VERSION 5.8 ;
BUSBITCHARS "[]" ;
DIVIDERCHAR "/" ;
UNITS
    DATABASE MICRONS 1000 ;
END UNITS

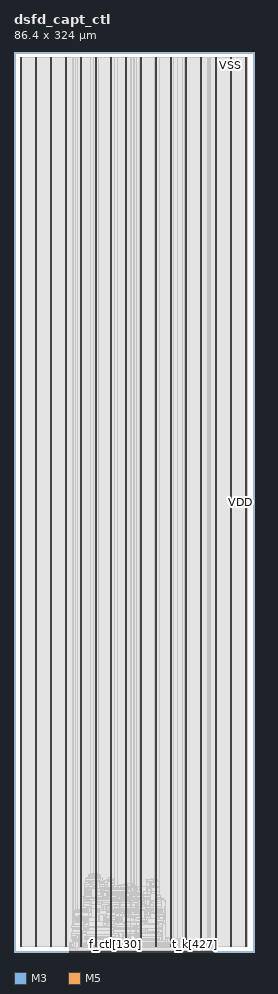
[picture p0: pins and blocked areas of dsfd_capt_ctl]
MACRO dsfd_capt_ctl
  FOREIGN dsfd_capt_ctl 0 0 ;
  CLASS BLOCK ;
  SIZE 86.4 BY 324 ;
  PIN ck[0]
    DIRECTION INPUT ;
    USE SIGNAL ;
    PORT
      LAYER M3 ;
        RECT  31.644 0 31.662 0.037 ;
    END
  END ck[0]
  PIN f_ctl[0]
    DIRECTION INPUT ;
    USE SIGNAL ;
    PORT
      LAYER M3 ;
        RECT  31.716 0 31.734 0.037 ;
    END
  END f_ctl[0]
  PIN f_ctl[100]
    DIRECTION INPUT ;
    USE SIGNAL ;
    PORT
      LAYER M5 ;
        RECT  48.816 0 48.84 0.084 ;
    END
  END f_ctl[100]
  PIN f_ctl[101]
    DIRECTION INPUT ;
    USE SIGNAL ;
    PORT
      LAYER M5 ;
        RECT  48.912 0 48.936 0.084 ;
    END
  END f_ctl[101]
  PIN f_ctl[102]
    DIRECTION INPUT ;
    USE SIGNAL ;
    PORT
      LAYER M5 ;
        RECT  49.008 0 49.032 0.084 ;
    END
  END f_ctl[102]
  PIN f_ctl[103]
    DIRECTION INPUT ;
    USE SIGNAL ;
    PORT
      LAYER M5 ;
        RECT  49.104 0 49.128 0.084 ;
    END
  END f_ctl[103]
  PIN f_ctl[104]
    DIRECTION INPUT ;
    USE SIGNAL ;
    PORT
      LAYER M5 ;
        RECT  49.2 0 49.224 0.084 ;
    END
  END f_ctl[104]
  PIN f_ctl[105]
    DIRECTION INPUT ;
    USE SIGNAL ;
    PORT
      LAYER M5 ;
        RECT  49.296 0 49.32 0.084 ;
    END
  END f_ctl[105]
  PIN f_ctl[106]
    DIRECTION INPUT ;
    USE SIGNAL ;
    PORT
      LAYER M5 ;
        RECT  49.392 0 49.416 0.084 ;
    END
  END f_ctl[106]
  PIN f_ctl[107]
    DIRECTION INPUT ;
    USE SIGNAL ;
    PORT
      LAYER M5 ;
        RECT  49.488 0 49.512 0.084 ;
    END
  END f_ctl[107]
  PIN f_ctl[108]
    DIRECTION INPUT ;
    USE SIGNAL ;
    PORT
      LAYER M5 ;
        RECT  49.584 0 49.608 0.084 ;
    END
  END f_ctl[108]
  PIN f_ctl[109]
    DIRECTION INPUT ;
    USE SIGNAL ;
    PORT
      LAYER M5 ;
        RECT  49.68 0 49.704 0.084 ;
    END
  END f_ctl[109]
  PIN f_ctl[10]
    DIRECTION INPUT ;
    USE SIGNAL ;
    PORT
      LAYER M3 ;
        RECT  32.436 0 32.454 0.037 ;
    END
  END f_ctl[10]
  PIN f_ctl[110]
    DIRECTION INPUT ;
    USE SIGNAL ;
    PORT
      LAYER M5 ;
        RECT  49.776 0 49.8 0.084 ;
    END
  END f_ctl[110]
  PIN f_ctl[111]
    DIRECTION INPUT ;
    USE SIGNAL ;
    PORT
      LAYER M5 ;
        RECT  49.872 0 49.896 0.084 ;
    END
  END f_ctl[111]
  PIN f_ctl[112]
    DIRECTION INPUT ;
    USE SIGNAL ;
    PORT
      LAYER M5 ;
        RECT  49.968 0 49.992 0.084 ;
    END
  END f_ctl[112]
  PIN f_ctl[113]
    DIRECTION INPUT ;
    USE SIGNAL ;
    PORT
      LAYER M5 ;
        RECT  50.064 0 50.088 0.084 ;
    END
  END f_ctl[113]
  PIN f_ctl[114]
    DIRECTION INPUT ;
    USE SIGNAL ;
    PORT
      LAYER M5 ;
        RECT  50.16 0 50.184 0.084 ;
    END
  END f_ctl[114]
  PIN f_ctl[115]
    DIRECTION INPUT ;
    USE SIGNAL ;
    PORT
      LAYER M5 ;
        RECT  50.256 0 50.28 0.084 ;
    END
  END f_ctl[115]
  PIN f_ctl[116]
    DIRECTION INPUT ;
    USE SIGNAL ;
    PORT
      LAYER M5 ;
        RECT  50.352 0 50.376 0.084 ;
    END
  END f_ctl[116]
  PIN f_ctl[117]
    DIRECTION INPUT ;
    USE SIGNAL ;
    PORT
      LAYER M5 ;
        RECT  50.448 0 50.472 0.084 ;
    END
  END f_ctl[117]
  PIN f_ctl[118]
    DIRECTION INPUT ;
    USE SIGNAL ;
    PORT
      LAYER M5 ;
        RECT  50.544 0 50.568 0.084 ;
    END
  END f_ctl[118]
  PIN f_ctl[119]
    DIRECTION INPUT ;
    USE SIGNAL ;
    PORT
      LAYER M5 ;
        RECT  50.64 0 50.664 0.084 ;
    END
  END f_ctl[119]
  PIN f_ctl[11]
    DIRECTION INPUT ;
    USE SIGNAL ;
    PORT
      LAYER M3 ;
        RECT  32.508 0 32.526 0.037 ;
    END
  END f_ctl[11]
  PIN f_ctl[120]
    DIRECTION INPUT ;
    USE SIGNAL ;
    PORT
      LAYER M5 ;
        RECT  50.736 0 50.76 0.084 ;
    END
  END f_ctl[120]
  PIN f_ctl[121]
    DIRECTION INPUT ;
    USE SIGNAL ;
    PORT
      LAYER M5 ;
        RECT  50.832 0 50.856 0.084 ;
    END
  END f_ctl[121]
  PIN f_ctl[122]
    DIRECTION INPUT ;
    USE SIGNAL ;
    PORT
      LAYER M5 ;
        RECT  50.928 0 50.952 0.084 ;
    END
  END f_ctl[122]
  PIN f_ctl[123]
    DIRECTION INPUT ;
    USE SIGNAL ;
    PORT
      LAYER M5 ;
        RECT  51.024 0 51.048 0.084 ;
    END
  END f_ctl[123]
  PIN f_ctl[124]
    DIRECTION INPUT ;
    USE SIGNAL ;
    PORT
      LAYER M5 ;
        RECT  51.12 0 51.144 0.084 ;
    END
  END f_ctl[124]
  PIN f_ctl[125]
    DIRECTION INPUT ;
    USE SIGNAL ;
    PORT
      LAYER M5 ;
        RECT  51.216 0 51.24 0.084 ;
    END
  END f_ctl[125]
  PIN f_ctl[126]
    DIRECTION INPUT ;
    USE SIGNAL ;
    PORT
      LAYER M5 ;
        RECT  51.312 0 51.336 0.084 ;
    END
  END f_ctl[126]
  PIN f_ctl[127]
    DIRECTION INPUT ;
    USE SIGNAL ;
    PORT
      LAYER M3 ;
        RECT  36.252 0 36.27 0.037 ;
    END
  END f_ctl[127]
  PIN f_ctl[128]
    DIRECTION INPUT ;
    USE SIGNAL ;
    PORT
      LAYER M3 ;
        RECT  36.324 0 36.342 0.037 ;
    END
  END f_ctl[128]
  PIN f_ctl[129]
    DIRECTION INPUT ;
    USE SIGNAL ;
    PORT
      LAYER M3 ;
        RECT  36.396 0 36.414 0.037 ;
    END
  END f_ctl[129]
  PIN f_ctl[12]
    DIRECTION INPUT ;
    USE SIGNAL ;
    PORT
      LAYER M3 ;
        RECT  32.58 0 32.598 0.037 ;
    END
  END f_ctl[12]
  PIN f_ctl[130]
    DIRECTION INPUT ;
    USE SIGNAL ;
    PORT
      LAYER M3 ;
        RECT  36.468 0 36.486 0.037 ;
    END
  END f_ctl[130]
  PIN f_ctl[131]
    DIRECTION INPUT ;
    USE SIGNAL ;
    PORT
      LAYER M3 ;
        RECT  36.54 0 36.558 0.037 ;
    END
  END f_ctl[131]
  PIN f_ctl[132]
    DIRECTION INPUT ;
    USE SIGNAL ;
    PORT
      LAYER M3 ;
        RECT  36.612 0 36.63 0.037 ;
    END
  END f_ctl[132]
  PIN f_ctl[133]
    DIRECTION INPUT ;
    USE SIGNAL ;
    PORT
      LAYER M3 ;
        RECT  36.684 0 36.702 0.037 ;
    END
  END f_ctl[133]
  PIN f_ctl[134]
    DIRECTION INPUT ;
    USE SIGNAL ;
    PORT
      LAYER M3 ;
        RECT  36.756 0 36.774 0.037 ;
    END
  END f_ctl[134]
  PIN f_ctl[135]
    DIRECTION INPUT ;
    USE SIGNAL ;
    PORT
      LAYER M3 ;
        RECT  36.828 0 36.846 0.037 ;
    END
  END f_ctl[135]
  PIN f_ctl[136]
    DIRECTION INPUT ;
    USE SIGNAL ;
    PORT
      LAYER M3 ;
        RECT  36.9 0 36.918 0.037 ;
    END
  END f_ctl[136]
  PIN f_ctl[137]
    DIRECTION INPUT ;
    USE SIGNAL ;
    PORT
      LAYER M3 ;
        RECT  36.972 0 36.99 0.037 ;
    END
  END f_ctl[137]
  PIN f_ctl[138]
    DIRECTION INPUT ;
    USE SIGNAL ;
    PORT
      LAYER M3 ;
        RECT  37.044 0 37.062 0.037 ;
    END
  END f_ctl[138]
  PIN f_ctl[139]
    DIRECTION INPUT ;
    USE SIGNAL ;
    PORT
      LAYER M3 ;
        RECT  37.116 0 37.134 0.037 ;
    END
  END f_ctl[139]
  PIN f_ctl[13]
    DIRECTION INPUT ;
    USE SIGNAL ;
    PORT
      LAYER M3 ;
        RECT  32.652 0 32.67 0.037 ;
    END
  END f_ctl[13]
  PIN f_ctl[140]
    DIRECTION INPUT ;
    USE SIGNAL ;
    PORT
      LAYER M3 ;
        RECT  37.188 0 37.206 0.037 ;
    END
  END f_ctl[140]
  PIN f_ctl[141]
    DIRECTION INPUT ;
    USE SIGNAL ;
    PORT
      LAYER M3 ;
        RECT  37.26 0 37.278 0.037 ;
    END
  END f_ctl[141]
  PIN f_ctl[142]
    DIRECTION INPUT ;
    USE SIGNAL ;
    PORT
      LAYER M3 ;
        RECT  37.332 0 37.35 0.037 ;
    END
  END f_ctl[142]
  PIN f_ctl[143]
    DIRECTION INPUT ;
    USE SIGNAL ;
    PORT
      LAYER M3 ;
        RECT  37.404 0 37.422 0.037 ;
    END
  END f_ctl[143]
  PIN f_ctl[144]
    DIRECTION INPUT ;
    USE SIGNAL ;
    PORT
      LAYER M3 ;
        RECT  37.476 0 37.494 0.037 ;
    END
  END f_ctl[144]
  PIN f_ctl[145]
    DIRECTION INPUT ;
    USE SIGNAL ;
    PORT
      LAYER M3 ;
        RECT  37.548 0 37.566 0.037 ;
    END
  END f_ctl[145]
  PIN f_ctl[146]
    DIRECTION INPUT ;
    USE SIGNAL ;
    PORT
      LAYER M3 ;
        RECT  37.62 0 37.638 0.037 ;
    END
  END f_ctl[146]
  PIN f_ctl[147]
    DIRECTION INPUT ;
    USE SIGNAL ;
    PORT
      LAYER M3 ;
        RECT  37.692 0 37.71 0.037 ;
    END
  END f_ctl[147]
  PIN f_ctl[148]
    DIRECTION INPUT ;
    USE SIGNAL ;
    PORT
      LAYER M3 ;
        RECT  37.764 0 37.782 0.037 ;
    END
  END f_ctl[148]
  PIN f_ctl[149]
    DIRECTION INPUT ;
    USE SIGNAL ;
    PORT
      LAYER M3 ;
        RECT  37.836 0 37.854 0.037 ;
    END
  END f_ctl[149]
  PIN f_ctl[14]
    DIRECTION INPUT ;
    USE SIGNAL ;
    PORT
      LAYER M3 ;
        RECT  32.724 0 32.742 0.037 ;
    END
  END f_ctl[14]
  PIN f_ctl[150]
    DIRECTION INPUT ;
    USE SIGNAL ;
    PORT
      LAYER M3 ;
        RECT  37.908 0 37.926 0.037 ;
    END
  END f_ctl[150]
  PIN f_ctl[151]
    DIRECTION INPUT ;
    USE SIGNAL ;
    PORT
      LAYER M3 ;
        RECT  37.98 0 37.998 0.037 ;
    END
  END f_ctl[151]
  PIN f_ctl[152]
    DIRECTION INPUT ;
    USE SIGNAL ;
    PORT
      LAYER M3 ;
        RECT  38.052 0 38.07 0.037 ;
    END
  END f_ctl[152]
  PIN f_ctl[153]
    DIRECTION INPUT ;
    USE SIGNAL ;
    PORT
      LAYER M3 ;
        RECT  38.124 0 38.142 0.037 ;
    END
  END f_ctl[153]
  PIN f_ctl[154]
    DIRECTION INPUT ;
    USE SIGNAL ;
    PORT
      LAYER M3 ;
        RECT  38.196 0 38.214 0.037 ;
    END
  END f_ctl[154]
  PIN f_ctl[155]
    DIRECTION INPUT ;
    USE SIGNAL ;
    PORT
      LAYER M3 ;
        RECT  38.268 0 38.286 0.037 ;
    END
  END f_ctl[155]
  PIN f_ctl[156]
    DIRECTION INPUT ;
    USE SIGNAL ;
    PORT
      LAYER M3 ;
        RECT  38.34 0 38.358 0.037 ;
    END
  END f_ctl[156]
  PIN f_ctl[157]
    DIRECTION INPUT ;
    USE SIGNAL ;
    PORT
      LAYER M3 ;
        RECT  38.412 0 38.43 0.037 ;
    END
  END f_ctl[157]
  PIN f_ctl[158]
    DIRECTION INPUT ;
    USE SIGNAL ;
    PORT
      LAYER M3 ;
        RECT  38.484 0 38.502 0.037 ;
    END
  END f_ctl[158]
  PIN f_ctl[159]
    DIRECTION INPUT ;
    USE SIGNAL ;
    PORT
      LAYER M3 ;
        RECT  29.34 0 29.358 0.037 ;
    END
  END f_ctl[159]
  PIN f_ctl[15]
    DIRECTION INPUT ;
    USE SIGNAL ;
    PORT
      LAYER M3 ;
        RECT  32.796 0 32.814 0.037 ;
    END
  END f_ctl[15]
  PIN f_ctl[160]
    DIRECTION INPUT ;
    USE SIGNAL ;
    PORT
      LAYER M3 ;
        RECT  29.412 0 29.43 0.037 ;
    END
  END f_ctl[160]
  PIN f_ctl[161]
    DIRECTION INPUT ;
    USE SIGNAL ;
    PORT
      LAYER M3 ;
        RECT  29.484 0 29.502 0.037 ;
    END
  END f_ctl[161]
  PIN f_ctl[162]
    DIRECTION INPUT ;
    USE SIGNAL ;
    PORT
      LAYER M3 ;
        RECT  29.556 0 29.574 0.037 ;
    END
  END f_ctl[162]
  PIN f_ctl[16]
    DIRECTION INPUT ;
    USE SIGNAL ;
    PORT
      LAYER M3 ;
        RECT  32.868 0 32.886 0.037 ;
    END
  END f_ctl[16]
  PIN f_ctl[17]
    DIRECTION INPUT ;
    USE SIGNAL ;
    PORT
      LAYER M3 ;
        RECT  32.94 0 32.958 0.037 ;
    END
  END f_ctl[17]
  PIN f_ctl[18]
    DIRECTION INPUT ;
    USE SIGNAL ;
    PORT
      LAYER M3 ;
        RECT  33.012 0 33.03 0.037 ;
    END
  END f_ctl[18]
  PIN f_ctl[19]
    DIRECTION INPUT ;
    USE SIGNAL ;
    PORT
      LAYER M3 ;
        RECT  33.084 0 33.102 0.037 ;
    END
  END f_ctl[19]
  PIN f_ctl[1]
    DIRECTION INPUT ;
    USE SIGNAL ;
    PORT
      LAYER M3 ;
        RECT  31.788 0 31.806 0.037 ;
    END
  END f_ctl[1]
  PIN f_ctl[20]
    DIRECTION INPUT ;
    USE SIGNAL ;
    PORT
      LAYER M3 ;
        RECT  33.156 0 33.174 0.037 ;
    END
  END f_ctl[20]
  PIN f_ctl[21]
    DIRECTION INPUT ;
    USE SIGNAL ;
    PORT
      LAYER M3 ;
        RECT  33.228 0 33.246 0.037 ;
    END
  END f_ctl[21]
  PIN f_ctl[22]
    DIRECTION INPUT ;
    USE SIGNAL ;
    PORT
      LAYER M3 ;
        RECT  33.3 0 33.318 0.037 ;
    END
  END f_ctl[22]
  PIN f_ctl[23]
    DIRECTION INPUT ;
    USE SIGNAL ;
    PORT
      LAYER M3 ;
        RECT  33.372 0 33.39 0.037 ;
    END
  END f_ctl[23]
  PIN f_ctl[24]
    DIRECTION INPUT ;
    USE SIGNAL ;
    PORT
      LAYER M3 ;
        RECT  33.444 0 33.462 0.037 ;
    END
  END f_ctl[24]
  PIN f_ctl[25]
    DIRECTION INPUT ;
    USE SIGNAL ;
    PORT
      LAYER M3 ;
        RECT  33.516 0 33.534 0.037 ;
    END
  END f_ctl[25]
  PIN f_ctl[26]
    DIRECTION INPUT ;
    USE SIGNAL ;
    PORT
      LAYER M3 ;
        RECT  33.588 0 33.606 0.037 ;
    END
  END f_ctl[26]
  PIN f_ctl[27]
    DIRECTION INPUT ;
    USE SIGNAL ;
    PORT
      LAYER M3 ;
        RECT  33.66 0 33.678 0.037 ;
    END
  END f_ctl[27]
  PIN f_ctl[28]
    DIRECTION INPUT ;
    USE SIGNAL ;
    PORT
      LAYER M3 ;
        RECT  33.732 0 33.75 0.037 ;
    END
  END f_ctl[28]
  PIN f_ctl[29]
    DIRECTION INPUT ;
    USE SIGNAL ;
    PORT
      LAYER M3 ;
        RECT  33.804 0 33.822 0.037 ;
    END
  END f_ctl[29]
  PIN f_ctl[2]
    DIRECTION INPUT ;
    USE SIGNAL ;
    PORT
      LAYER M3 ;
        RECT  31.86 0 31.878 0.037 ;
    END
  END f_ctl[2]
  PIN f_ctl[30]
    DIRECTION INPUT ;
    USE SIGNAL ;
    PORT
      LAYER M3 ;
        RECT  33.876 0 33.894 0.037 ;
    END
  END f_ctl[30]
  PIN f_ctl[31]
    DIRECTION INPUT ;
    USE SIGNAL ;
    PORT
      LAYER M3 ;
        RECT  33.948 0 33.966 0.037 ;
    END
  END f_ctl[31]
  PIN f_ctl[32]
    DIRECTION INPUT ;
    USE SIGNAL ;
    PORT
      LAYER M3 ;
        RECT  34.02 0 34.038 0.037 ;
    END
  END f_ctl[32]
  PIN f_ctl[33]
    DIRECTION INPUT ;
    USE SIGNAL ;
    PORT
      LAYER M3 ;
        RECT  34.092 0 34.11 0.037 ;
    END
  END f_ctl[33]
  PIN f_ctl[34]
    DIRECTION INPUT ;
    USE SIGNAL ;
    PORT
      LAYER M3 ;
        RECT  34.164 0 34.182 0.037 ;
    END
  END f_ctl[34]
  PIN f_ctl[35]
    DIRECTION INPUT ;
    USE SIGNAL ;
    PORT
      LAYER M3 ;
        RECT  34.236 0 34.254 0.037 ;
    END
  END f_ctl[35]
  PIN f_ctl[36]
    DIRECTION INPUT ;
    USE SIGNAL ;
    PORT
      LAYER M3 ;
        RECT  34.308 0 34.326 0.037 ;
    END
  END f_ctl[36]
  PIN f_ctl[37]
    DIRECTION INPUT ;
    USE SIGNAL ;
    PORT
      LAYER M3 ;
        RECT  34.38 0 34.398 0.037 ;
    END
  END f_ctl[37]
  PIN f_ctl[38]
    DIRECTION INPUT ;
    USE SIGNAL ;
    PORT
      LAYER M3 ;
        RECT  34.452 0 34.47 0.037 ;
    END
  END f_ctl[38]
  PIN f_ctl[39]
    DIRECTION INPUT ;
    USE SIGNAL ;
    PORT
      LAYER M3 ;
        RECT  34.524 0 34.542 0.037 ;
    END
  END f_ctl[39]
  PIN f_ctl[3]
    DIRECTION INPUT ;
    USE SIGNAL ;
    PORT
      LAYER M3 ;
        RECT  31.932 0 31.95 0.037 ;
    END
  END f_ctl[3]
  PIN f_ctl[40]
    DIRECTION INPUT ;
    USE SIGNAL ;
    PORT
      LAYER M3 ;
        RECT  34.596 0 34.614 0.037 ;
    END
  END f_ctl[40]
  PIN f_ctl[41]
    DIRECTION INPUT ;
    USE SIGNAL ;
    PORT
      LAYER M3 ;
        RECT  34.668 0 34.686 0.037 ;
    END
  END f_ctl[41]
  PIN f_ctl[42]
    DIRECTION INPUT ;
    USE SIGNAL ;
    PORT
      LAYER M3 ;
        RECT  34.74 0 34.758 0.037 ;
    END
  END f_ctl[42]
  PIN f_ctl[43]
    DIRECTION INPUT ;
    USE SIGNAL ;
    PORT
      LAYER M3 ;
        RECT  34.812 0 34.83 0.037 ;
    END
  END f_ctl[43]
  PIN f_ctl[44]
    DIRECTION INPUT ;
    USE SIGNAL ;
    PORT
      LAYER M3 ;
        RECT  34.884 0 34.902 0.037 ;
    END
  END f_ctl[44]
  PIN f_ctl[45]
    DIRECTION INPUT ;
    USE SIGNAL ;
    PORT
      LAYER M3 ;
        RECT  34.956 0 34.974 0.037 ;
    END
  END f_ctl[45]
  PIN f_ctl[46]
    DIRECTION INPUT ;
    USE SIGNAL ;
    PORT
      LAYER M3 ;
        RECT  35.028 0 35.046 0.037 ;
    END
  END f_ctl[46]
  PIN f_ctl[47]
    DIRECTION INPUT ;
    USE SIGNAL ;
    PORT
      LAYER M3 ;
        RECT  35.1 0 35.118 0.037 ;
    END
  END f_ctl[47]
  PIN f_ctl[48]
    DIRECTION INPUT ;
    USE SIGNAL ;
    PORT
      LAYER M3 ;
        RECT  35.172 0 35.19 0.037 ;
    END
  END f_ctl[48]
  PIN f_ctl[49]
    DIRECTION INPUT ;
    USE SIGNAL ;
    PORT
      LAYER M3 ;
        RECT  35.244 0 35.262 0.037 ;
    END
  END f_ctl[49]
  PIN f_ctl[4]
    DIRECTION INPUT ;
    USE SIGNAL ;
    PORT
      LAYER M3 ;
        RECT  32.004 0 32.022 0.037 ;
    END
  END f_ctl[4]
  PIN f_ctl[50]
    DIRECTION INPUT ;
    USE SIGNAL ;
    PORT
      LAYER M3 ;
        RECT  35.316 0 35.334 0.037 ;
    END
  END f_ctl[50]
  PIN f_ctl[51]
    DIRECTION INPUT ;
    USE SIGNAL ;
    PORT
      LAYER M3 ;
        RECT  35.388 0 35.406 0.037 ;
    END
  END f_ctl[51]
  PIN f_ctl[52]
    DIRECTION INPUT ;
    USE SIGNAL ;
    PORT
      LAYER M3 ;
        RECT  35.46 0 35.478 0.037 ;
    END
  END f_ctl[52]
  PIN f_ctl[53]
    DIRECTION INPUT ;
    USE SIGNAL ;
    PORT
      LAYER M3 ;
        RECT  35.532 0 35.55 0.037 ;
    END
  END f_ctl[53]
  PIN f_ctl[54]
    DIRECTION INPUT ;
    USE SIGNAL ;
    PORT
      LAYER M3 ;
        RECT  35.604 0 35.622 0.037 ;
    END
  END f_ctl[54]
  PIN f_ctl[55]
    DIRECTION INPUT ;
    USE SIGNAL ;
    PORT
      LAYER M3 ;
        RECT  35.676 0 35.694 0.037 ;
    END
  END f_ctl[55]
  PIN f_ctl[56]
    DIRECTION INPUT ;
    USE SIGNAL ;
    PORT
      LAYER M3 ;
        RECT  35.748 0 35.766 0.037 ;
    END
  END f_ctl[56]
  PIN f_ctl[57]
    DIRECTION INPUT ;
    USE SIGNAL ;
    PORT
      LAYER M3 ;
        RECT  35.82 0 35.838 0.037 ;
    END
  END f_ctl[57]
  PIN f_ctl[58]
    DIRECTION INPUT ;
    USE SIGNAL ;
    PORT
      LAYER M3 ;
        RECT  35.892 0 35.91 0.037 ;
    END
  END f_ctl[58]
  PIN f_ctl[59]
    DIRECTION INPUT ;
    USE SIGNAL ;
    PORT
      LAYER M3 ;
        RECT  35.964 0 35.982 0.037 ;
    END
  END f_ctl[59]
  PIN f_ctl[5]
    DIRECTION INPUT ;
    USE SIGNAL ;
    PORT
      LAYER M3 ;
        RECT  32.076 0 32.094 0.037 ;
    END
  END f_ctl[5]
  PIN f_ctl[60]
    DIRECTION INPUT ;
    USE SIGNAL ;
    PORT
      LAYER M3 ;
        RECT  36.036 0 36.054 0.037 ;
    END
  END f_ctl[60]
  PIN f_ctl[61]
    DIRECTION INPUT ;
    USE SIGNAL ;
    PORT
      LAYER M3 ;
        RECT  36.108 0 36.126 0.037 ;
    END
  END f_ctl[61]
  PIN f_ctl[62]
    DIRECTION INPUT ;
    USE SIGNAL ;
    PORT
      LAYER M3 ;
        RECT  36.18 0 36.198 0.037 ;
    END
  END f_ctl[62]
  PIN f_ctl[63]
    DIRECTION INPUT ;
    USE SIGNAL ;
    PORT
      LAYER M5 ;
        RECT  45.264 0 45.288 0.084 ;
    END
  END f_ctl[63]
  PIN f_ctl[64]
    DIRECTION INPUT ;
    USE SIGNAL ;
    PORT
      LAYER M5 ;
        RECT  45.36 0 45.384 0.084 ;
    END
  END f_ctl[64]
  PIN f_ctl[65]
    DIRECTION INPUT ;
    USE SIGNAL ;
    PORT
      LAYER M5 ;
        RECT  45.456 0 45.48 0.084 ;
    END
  END f_ctl[65]
  PIN f_ctl[66]
    DIRECTION INPUT ;
    USE SIGNAL ;
    PORT
      LAYER M5 ;
        RECT  45.552 0 45.576 0.084 ;
    END
  END f_ctl[66]
  PIN f_ctl[67]
    DIRECTION INPUT ;
    USE SIGNAL ;
    PORT
      LAYER M5 ;
        RECT  45.648 0 45.672 0.084 ;
    END
  END f_ctl[67]
  PIN f_ctl[68]
    DIRECTION INPUT ;
    USE SIGNAL ;
    PORT
      LAYER M5 ;
        RECT  45.744 0 45.768 0.084 ;
    END
  END f_ctl[68]
  PIN f_ctl[69]
    DIRECTION INPUT ;
    USE SIGNAL ;
    PORT
      LAYER M5 ;
        RECT  45.84 0 45.864 0.084 ;
    END
  END f_ctl[69]
  PIN f_ctl[6]
    DIRECTION INPUT ;
    USE SIGNAL ;
    PORT
      LAYER M3 ;
        RECT  32.148 0 32.166 0.037 ;
    END
  END f_ctl[6]
  PIN f_ctl[70]
    DIRECTION INPUT ;
    USE SIGNAL ;
    PORT
      LAYER M5 ;
        RECT  45.936 0 45.96 0.084 ;
    END
  END f_ctl[70]
  PIN f_ctl[71]
    DIRECTION INPUT ;
    USE SIGNAL ;
    PORT
      LAYER M5 ;
        RECT  46.032 0 46.056 0.084 ;
    END
  END f_ctl[71]
  PIN f_ctl[72]
    DIRECTION INPUT ;
    USE SIGNAL ;
    PORT
      LAYER M5 ;
        RECT  46.128 0 46.152 0.084 ;
    END
  END f_ctl[72]
  PIN f_ctl[73]
    DIRECTION INPUT ;
    USE SIGNAL ;
    PORT
      LAYER M5 ;
        RECT  46.224 0 46.248 0.084 ;
    END
  END f_ctl[73]
  PIN f_ctl[74]
    DIRECTION INPUT ;
    USE SIGNAL ;
    PORT
      LAYER M5 ;
        RECT  46.32 0 46.344 0.084 ;
    END
  END f_ctl[74]
  PIN f_ctl[75]
    DIRECTION INPUT ;
    USE SIGNAL ;
    PORT
      LAYER M5 ;
        RECT  46.416 0 46.44 0.084 ;
    END
  END f_ctl[75]
  PIN f_ctl[76]
    DIRECTION INPUT ;
    USE SIGNAL ;
    PORT
      LAYER M5 ;
        RECT  46.512 0 46.536 0.084 ;
    END
  END f_ctl[76]
  PIN f_ctl[77]
    DIRECTION INPUT ;
    USE SIGNAL ;
    PORT
      LAYER M5 ;
        RECT  46.608 0 46.632 0.084 ;
    END
  END f_ctl[77]
  PIN f_ctl[78]
    DIRECTION INPUT ;
    USE SIGNAL ;
    PORT
      LAYER M5 ;
        RECT  46.704 0 46.728 0.084 ;
    END
  END f_ctl[78]
  PIN f_ctl[79]
    DIRECTION INPUT ;
    USE SIGNAL ;
    PORT
      LAYER M5 ;
        RECT  46.8 0 46.824 0.084 ;
    END
  END f_ctl[79]
  PIN f_ctl[7]
    DIRECTION INPUT ;
    USE SIGNAL ;
    PORT
      LAYER M3 ;
        RECT  32.22 0 32.238 0.037 ;
    END
  END f_ctl[7]
  PIN f_ctl[80]
    DIRECTION INPUT ;
    USE SIGNAL ;
    PORT
      LAYER M5 ;
        RECT  46.896 0 46.92 0.084 ;
    END
  END f_ctl[80]
  PIN f_ctl[81]
    DIRECTION INPUT ;
    USE SIGNAL ;
    PORT
      LAYER M5 ;
        RECT  46.992 0 47.016 0.084 ;
    END
  END f_ctl[81]
  PIN f_ctl[82]
    DIRECTION INPUT ;
    USE SIGNAL ;
    PORT
      LAYER M5 ;
        RECT  47.088 0 47.112 0.084 ;
    END
  END f_ctl[82]
  PIN f_ctl[83]
    DIRECTION INPUT ;
    USE SIGNAL ;
    PORT
      LAYER M5 ;
        RECT  47.184 0 47.208 0.084 ;
    END
  END f_ctl[83]
  PIN f_ctl[84]
    DIRECTION INPUT ;
    USE SIGNAL ;
    PORT
      LAYER M5 ;
        RECT  47.28 0 47.304 0.084 ;
    END
  END f_ctl[84]
  PIN f_ctl[85]
    DIRECTION INPUT ;
    USE SIGNAL ;
    PORT
      LAYER M5 ;
        RECT  47.376 0 47.4 0.084 ;
    END
  END f_ctl[85]
  PIN f_ctl[86]
    DIRECTION INPUT ;
    USE SIGNAL ;
    PORT
      LAYER M5 ;
        RECT  47.472 0 47.496 0.084 ;
    END
  END f_ctl[86]
  PIN f_ctl[87]
    DIRECTION INPUT ;
    USE SIGNAL ;
    PORT
      LAYER M5 ;
        RECT  47.568 0 47.592 0.084 ;
    END
  END f_ctl[87]
  PIN f_ctl[88]
    DIRECTION INPUT ;
    USE SIGNAL ;
    PORT
      LAYER M5 ;
        RECT  47.664 0 47.688 0.084 ;
    END
  END f_ctl[88]
  PIN f_ctl[89]
    DIRECTION INPUT ;
    USE SIGNAL ;
    PORT
      LAYER M5 ;
        RECT  47.76 0 47.784 0.084 ;
    END
  END f_ctl[89]
  PIN f_ctl[8]
    DIRECTION INPUT ;
    USE SIGNAL ;
    PORT
      LAYER M3 ;
        RECT  32.292 0 32.31 0.037 ;
    END
  END f_ctl[8]
  PIN f_ctl[90]
    DIRECTION INPUT ;
    USE SIGNAL ;
    PORT
      LAYER M5 ;
        RECT  47.856 0 47.88 0.084 ;
    END
  END f_ctl[90]
  PIN f_ctl[91]
    DIRECTION INPUT ;
    USE SIGNAL ;
    PORT
      LAYER M5 ;
        RECT  47.952 0 47.976 0.084 ;
    END
  END f_ctl[91]
  PIN f_ctl[92]
    DIRECTION INPUT ;
    USE SIGNAL ;
    PORT
      LAYER M5 ;
        RECT  48.048 0 48.072 0.084 ;
    END
  END f_ctl[92]
  PIN f_ctl[93]
    DIRECTION INPUT ;
    USE SIGNAL ;
    PORT
      LAYER M5 ;
        RECT  48.144 0 48.168 0.084 ;
    END
  END f_ctl[93]
  PIN f_ctl[94]
    DIRECTION INPUT ;
    USE SIGNAL ;
    PORT
      LAYER M5 ;
        RECT  48.24 0 48.264 0.084 ;
    END
  END f_ctl[94]
  PIN f_ctl[95]
    DIRECTION INPUT ;
    USE SIGNAL ;
    PORT
      LAYER M5 ;
        RECT  48.336 0 48.36 0.084 ;
    END
  END f_ctl[95]
  PIN f_ctl[96]
    DIRECTION INPUT ;
    USE SIGNAL ;
    PORT
      LAYER M5 ;
        RECT  48.432 0 48.456 0.084 ;
    END
  END f_ctl[96]
  PIN f_ctl[97]
    DIRECTION INPUT ;
    USE SIGNAL ;
    PORT
      LAYER M5 ;
        RECT  48.528 0 48.552 0.084 ;
    END
  END f_ctl[97]
  PIN f_ctl[98]
    DIRECTION INPUT ;
    USE SIGNAL ;
    PORT
      LAYER M5 ;
        RECT  48.624 0 48.648 0.084 ;
    END
  END f_ctl[98]
  PIN f_ctl[99]
    DIRECTION INPUT ;
    USE SIGNAL ;
    PORT
      LAYER M5 ;
        RECT  48.72 0 48.744 0.084 ;
    END
  END f_ctl[99]
  PIN f_ctl[9]
    DIRECTION INPUT ;
    USE SIGNAL ;
    PORT
      LAYER M3 ;
        RECT  32.364 0 32.382 0.037 ;
    END
  END f_ctl[9]
  PIN f_sb[0]
    DIRECTION INPUT ;
    USE SIGNAL ;
    PORT
      LAYER M3 ;
        RECT  29.628 0 29.646 0.037 ;
    END
  END f_sb[0]
  PIN f_sb[10]
    DIRECTION INPUT ;
    USE SIGNAL ;
    PORT
      LAYER M3 ;
        RECT  30.348 0 30.366 0.037 ;
    END
  END f_sb[10]
  PIN f_sb[11]
    DIRECTION INPUT ;
    USE SIGNAL ;
    PORT
      LAYER M3 ;
        RECT  30.42 0 30.438 0.037 ;
    END
  END f_sb[11]
  PIN f_sb[12]
    DIRECTION INPUT ;
    USE SIGNAL ;
    PORT
      LAYER M3 ;
        RECT  30.492 0 30.51 0.037 ;
    END
  END f_sb[12]
  PIN f_sb[13]
    DIRECTION INPUT ;
    USE SIGNAL ;
    PORT
      LAYER M3 ;
        RECT  30.564 0 30.582 0.037 ;
    END
  END f_sb[13]
  PIN f_sb[14]
    DIRECTION INPUT ;
    USE SIGNAL ;
    PORT
      LAYER M3 ;
        RECT  30.636 0 30.654 0.037 ;
    END
  END f_sb[14]
  PIN f_sb[15]
    DIRECTION INPUT ;
    USE SIGNAL ;
    PORT
      LAYER M3 ;
        RECT  30.708 0 30.726 0.037 ;
    END
  END f_sb[15]
  PIN f_sb[1]
    DIRECTION INPUT ;
    USE SIGNAL ;
    PORT
      LAYER M3 ;
        RECT  29.7 0 29.718 0.037 ;
    END
  END f_sb[1]
  PIN f_sb[2]
    DIRECTION INPUT ;
    USE SIGNAL ;
    PORT
      LAYER M3 ;
        RECT  29.772 0 29.79 0.037 ;
    END
  END f_sb[2]
  PIN f_sb[3]
    DIRECTION INPUT ;
    USE SIGNAL ;
    PORT
      LAYER M3 ;
        RECT  29.844 0 29.862 0.037 ;
    END
  END f_sb[3]
  PIN f_sb[4]
    DIRECTION INPUT ;
    USE SIGNAL ;
    PORT
      LAYER M3 ;
        RECT  29.916 0 29.934 0.037 ;
    END
  END f_sb[4]
  PIN f_sb[5]
    DIRECTION INPUT ;
    USE SIGNAL ;
    PORT
      LAYER M3 ;
        RECT  29.988 0 30.006 0.037 ;
    END
  END f_sb[5]
  PIN f_sb[6]
    DIRECTION INPUT ;
    USE SIGNAL ;
    PORT
      LAYER M3 ;
        RECT  30.06 0 30.078 0.037 ;
    END
  END f_sb[6]
  PIN f_sb[7]
    DIRECTION INPUT ;
    USE SIGNAL ;
    PORT
      LAYER M3 ;
        RECT  30.132 0 30.15 0.037 ;
    END
  END f_sb[7]
  PIN f_sb[8]
    DIRECTION INPUT ;
    USE SIGNAL ;
    PORT
      LAYER M3 ;
        RECT  30.204 0 30.222 0.037 ;
    END
  END f_sb[8]
  PIN f_sb[9]
    DIRECTION INPUT ;
    USE SIGNAL ;
    PORT
      LAYER M3 ;
        RECT  30.276 0 30.294 0.037 ;
    END
  END f_sb[9]
  PIN rst[0]
    DIRECTION INPUT ;
    USE SIGNAL ;
    PORT
      LAYER M3 ;
        RECT  30.78 0 30.798 0.037 ;
    END
  END rst[0]
  PIN t_k[0]
    DIRECTION OUTPUT ;
    USE SIGNAL ;
    PORT
      LAYER M3 ;
        RECT  30.852 0 30.87 0.037 ;
    END
  END t_k[0]
  PIN t_k[100]
    DIRECTION OUTPUT ;
    USE SIGNAL ;
    PORT
      LAYER M5 ;
        RECT  53.808 0 53.832 0.084 ;
    END
  END t_k[100]
  PIN t_k[101]
    DIRECTION OUTPUT ;
    USE SIGNAL ;
    PORT
      LAYER M5 ;
        RECT  53.904 0 53.928 0.084 ;
    END
  END t_k[101]
  PIN t_k[102]
    DIRECTION OUTPUT ;
    USE SIGNAL ;
    PORT
      LAYER M5 ;
        RECT  54 0 54.024 0.084 ;
    END
  END t_k[102]
  PIN t_k[103]
    DIRECTION OUTPUT ;
    USE SIGNAL ;
    PORT
      LAYER M5 ;
        RECT  54.096 0 54.12 0.084 ;
    END
  END t_k[103]
  PIN t_k[104]
    DIRECTION OUTPUT ;
    USE SIGNAL ;
    PORT
      LAYER M5 ;
        RECT  54.192 0 54.216 0.084 ;
    END
  END t_k[104]
  PIN t_k[105]
    DIRECTION OUTPUT ;
    USE SIGNAL ;
    PORT
      LAYER M5 ;
        RECT  54.288 0 54.312 0.084 ;
    END
  END t_k[105]
  PIN t_k[106]
    DIRECTION OUTPUT ;
    USE SIGNAL ;
    PORT
      LAYER M5 ;
        RECT  54.384 0 54.408 0.084 ;
    END
  END t_k[106]
  PIN t_k[107]
    DIRECTION OUTPUT ;
    USE SIGNAL ;
    PORT
      LAYER M5 ;
        RECT  42.192 0 42.216 0.084 ;
    END
  END t_k[107]
  PIN t_k[108]
    DIRECTION OUTPUT ;
    USE SIGNAL ;
    PORT
      LAYER M5 ;
        RECT  42.288 0 42.312 0.084 ;
    END
  END t_k[108]
  PIN t_k[109]
    DIRECTION OUTPUT ;
    USE SIGNAL ;
    PORT
      LAYER M5 ;
        RECT  42.384 0 42.408 0.084 ;
    END
  END t_k[109]
  PIN t_k[10]
    DIRECTION OUTPUT ;
    USE SIGNAL ;
    PORT
      LAYER M3 ;
        RECT  31.572 0 31.59 0.037 ;
    END
  END t_k[10]
  PIN t_k[110]
    DIRECTION OUTPUT ;
    USE SIGNAL ;
    PORT
      LAYER M5 ;
        RECT  42.48 0 42.504 0.084 ;
    END
  END t_k[110]
  PIN t_k[111]
    DIRECTION OUTPUT ;
    USE SIGNAL ;
    PORT
      LAYER M5 ;
        RECT  42.576 0 42.6 0.084 ;
    END
  END t_k[111]
  PIN t_k[112]
    DIRECTION OUTPUT ;
    USE SIGNAL ;
    PORT
      LAYER M5 ;
        RECT  42.672 0 42.696 0.084 ;
    END
  END t_k[112]
  PIN t_k[113]
    DIRECTION OUTPUT ;
    USE SIGNAL ;
    PORT
      LAYER M5 ;
        RECT  42.768 0 42.792 0.084 ;
    END
  END t_k[113]
  PIN t_k[114]
    DIRECTION OUTPUT ;
    USE SIGNAL ;
    PORT
      LAYER M5 ;
        RECT  42.864 0 42.888 0.084 ;
    END
  END t_k[114]
  PIN t_k[115]
    DIRECTION OUTPUT ;
    USE SIGNAL ;
    PORT
      LAYER M5 ;
        RECT  42.96 0 42.984 0.084 ;
    END
  END t_k[115]
  PIN t_k[116]
    DIRECTION OUTPUT ;
    USE SIGNAL ;
    PORT
      LAYER M5 ;
        RECT  43.056 0 43.08 0.084 ;
    END
  END t_k[116]
  PIN t_k[117]
    DIRECTION OUTPUT ;
    USE SIGNAL ;
    PORT
      LAYER M5 ;
        RECT  43.152 0 43.176 0.084 ;
    END
  END t_k[117]
  PIN t_k[118]
    DIRECTION OUTPUT ;
    USE SIGNAL ;
    PORT
      LAYER M5 ;
        RECT  43.248 0 43.272 0.084 ;
    END
  END t_k[118]
  PIN t_k[119]
    DIRECTION OUTPUT ;
    USE SIGNAL ;
    PORT
      LAYER M5 ;
        RECT  43.344 0 43.368 0.084 ;
    END
  END t_k[119]
  PIN t_k[11]
    DIRECTION OUTPUT ;
    USE SIGNAL ;
    PORT
      LAYER M5 ;
        RECT  39.12 0 39.144 0.084 ;
    END
  END t_k[11]
  PIN t_k[120]
    DIRECTION OUTPUT ;
    USE SIGNAL ;
    PORT
      LAYER M5 ;
        RECT  43.44 0 43.464 0.084 ;
    END
  END t_k[120]
  PIN t_k[121]
    DIRECTION OUTPUT ;
    USE SIGNAL ;
    PORT
      LAYER M5 ;
        RECT  43.536 0 43.56 0.084 ;
    END
  END t_k[121]
  PIN t_k[122]
    DIRECTION OUTPUT ;
    USE SIGNAL ;
    PORT
      LAYER M5 ;
        RECT  43.632 0 43.656 0.084 ;
    END
  END t_k[122]
  PIN t_k[123]
    DIRECTION OUTPUT ;
    USE SIGNAL ;
    PORT
      LAYER M5 ;
        RECT  43.728 0 43.752 0.084 ;
    END
  END t_k[123]
  PIN t_k[124]
    DIRECTION OUTPUT ;
    USE SIGNAL ;
    PORT
      LAYER M5 ;
        RECT  43.824 0 43.848 0.084 ;
    END
  END t_k[124]
  PIN t_k[125]
    DIRECTION OUTPUT ;
    USE SIGNAL ;
    PORT
      LAYER M5 ;
        RECT  43.92 0 43.944 0.084 ;
    END
  END t_k[125]
  PIN t_k[126]
    DIRECTION OUTPUT ;
    USE SIGNAL ;
    PORT
      LAYER M5 ;
        RECT  44.016 0 44.04 0.084 ;
    END
  END t_k[126]
  PIN t_k[127]
    DIRECTION OUTPUT ;
    USE SIGNAL ;
    PORT
      LAYER M5 ;
        RECT  44.112 0 44.136 0.084 ;
    END
  END t_k[127]
  PIN t_k[128]
    DIRECTION OUTPUT ;
    USE SIGNAL ;
    PORT
      LAYER M5 ;
        RECT  44.208 0 44.232 0.084 ;
    END
  END t_k[128]
  PIN t_k[129]
    DIRECTION OUTPUT ;
    USE SIGNAL ;
    PORT
      LAYER M5 ;
        RECT  44.304 0 44.328 0.084 ;
    END
  END t_k[129]
  PIN t_k[12]
    DIRECTION OUTPUT ;
    USE SIGNAL ;
    PORT
      LAYER M5 ;
        RECT  39.216 0 39.24 0.084 ;
    END
  END t_k[12]
  PIN t_k[130]
    DIRECTION OUTPUT ;
    USE SIGNAL ;
    PORT
      LAYER M5 ;
        RECT  44.4 0 44.424 0.084 ;
    END
  END t_k[130]
  PIN t_k[131]
    DIRECTION OUTPUT ;
    USE SIGNAL ;
    PORT
      LAYER M5 ;
        RECT  44.496 0 44.52 0.084 ;
    END
  END t_k[131]
  PIN t_k[132]
    DIRECTION OUTPUT ;
    USE SIGNAL ;
    PORT
      LAYER M5 ;
        RECT  44.592 0 44.616 0.084 ;
    END
  END t_k[132]
  PIN t_k[133]
    DIRECTION OUTPUT ;
    USE SIGNAL ;
    PORT
      LAYER M5 ;
        RECT  44.688 0 44.712 0.084 ;
    END
  END t_k[133]
  PIN t_k[134]
    DIRECTION OUTPUT ;
    USE SIGNAL ;
    PORT
      LAYER M5 ;
        RECT  44.784 0 44.808 0.084 ;
    END
  END t_k[134]
  PIN t_k[135]
    DIRECTION OUTPUT ;
    USE SIGNAL ;
    PORT
      LAYER M5 ;
        RECT  44.88 0 44.904 0.084 ;
    END
  END t_k[135]
  PIN t_k[136]
    DIRECTION OUTPUT ;
    USE SIGNAL ;
    PORT
      LAYER M5 ;
        RECT  44.976 0 45 0.084 ;
    END
  END t_k[136]
  PIN t_k[137]
    DIRECTION OUTPUT ;
    USE SIGNAL ;
    PORT
      LAYER M5 ;
        RECT  45.072 0 45.096 0.084 ;
    END
  END t_k[137]
  PIN t_k[138]
    DIRECTION OUTPUT ;
    USE SIGNAL ;
    PORT
      LAYER M5 ;
        RECT  45.168 0 45.192 0.084 ;
    END
  END t_k[138]
  PIN t_k[139]
    DIRECTION OUTPUT ;
    USE SIGNAL ;
    PORT
      LAYER M3 ;
        RECT  52.956 0 52.974 0.037 ;
    END
  END t_k[139]
  PIN t_k[13]
    DIRECTION OUTPUT ;
    USE SIGNAL ;
    PORT
      LAYER M5 ;
        RECT  39.312 0 39.336 0.084 ;
    END
  END t_k[13]
  PIN t_k[140]
    DIRECTION OUTPUT ;
    USE SIGNAL ;
    PORT
      LAYER M3 ;
        RECT  53.028 0 53.046 0.037 ;
    END
  END t_k[140]
  PIN t_k[141]
    DIRECTION OUTPUT ;
    USE SIGNAL ;
    PORT
      LAYER M3 ;
        RECT  53.1 0 53.118 0.037 ;
    END
  END t_k[141]
  PIN t_k[142]
    DIRECTION OUTPUT ;
    USE SIGNAL ;
    PORT
      LAYER M3 ;
        RECT  53.172 0 53.19 0.037 ;
    END
  END t_k[142]
  PIN t_k[143]
    DIRECTION OUTPUT ;
    USE SIGNAL ;
    PORT
      LAYER M3 ;
        RECT  53.244 0 53.262 0.037 ;
    END
  END t_k[143]
  PIN t_k[144]
    DIRECTION OUTPUT ;
    USE SIGNAL ;
    PORT
      LAYER M3 ;
        RECT  53.316 0 53.334 0.037 ;
    END
  END t_k[144]
  PIN t_k[145]
    DIRECTION OUTPUT ;
    USE SIGNAL ;
    PORT
      LAYER M3 ;
        RECT  53.388 0 53.406 0.037 ;
    END
  END t_k[145]
  PIN t_k[146]
    DIRECTION OUTPUT ;
    USE SIGNAL ;
    PORT
      LAYER M3 ;
        RECT  53.46 0 53.478 0.037 ;
    END
  END t_k[146]
  PIN t_k[147]
    DIRECTION OUTPUT ;
    USE SIGNAL ;
    PORT
      LAYER M3 ;
        RECT  53.532 0 53.55 0.037 ;
    END
  END t_k[147]
  PIN t_k[148]
    DIRECTION OUTPUT ;
    USE SIGNAL ;
    PORT
      LAYER M3 ;
        RECT  53.604 0 53.622 0.037 ;
    END
  END t_k[148]
  PIN t_k[149]
    DIRECTION OUTPUT ;
    USE SIGNAL ;
    PORT
      LAYER M3 ;
        RECT  53.676 0 53.694 0.037 ;
    END
  END t_k[149]
  PIN t_k[14]
    DIRECTION OUTPUT ;
    USE SIGNAL ;
    PORT
      LAYER M5 ;
        RECT  39.408 0 39.432 0.084 ;
    END
  END t_k[14]
  PIN t_k[150]
    DIRECTION OUTPUT ;
    USE SIGNAL ;
    PORT
      LAYER M3 ;
        RECT  53.748 0 53.766 0.037 ;
    END
  END t_k[150]
  PIN t_k[151]
    DIRECTION OUTPUT ;
    USE SIGNAL ;
    PORT
      LAYER M3 ;
        RECT  53.82 0 53.838 0.037 ;
    END
  END t_k[151]
  PIN t_k[152]
    DIRECTION OUTPUT ;
    USE SIGNAL ;
    PORT
      LAYER M3 ;
        RECT  53.892 0 53.91 0.037 ;
    END
  END t_k[152]
  PIN t_k[153]
    DIRECTION OUTPUT ;
    USE SIGNAL ;
    PORT
      LAYER M3 ;
        RECT  53.964 0 53.982 0.037 ;
    END
  END t_k[153]
  PIN t_k[154]
    DIRECTION OUTPUT ;
    USE SIGNAL ;
    PORT
      LAYER M3 ;
        RECT  54.036 0 54.054 0.037 ;
    END
  END t_k[154]
  PIN t_k[155]
    DIRECTION OUTPUT ;
    USE SIGNAL ;
    PORT
      LAYER M3 ;
        RECT  54.108 0 54.126 0.037 ;
    END
  END t_k[155]
  PIN t_k[156]
    DIRECTION OUTPUT ;
    USE SIGNAL ;
    PORT
      LAYER M3 ;
        RECT  54.18 0 54.198 0.037 ;
    END
  END t_k[156]
  PIN t_k[157]
    DIRECTION OUTPUT ;
    USE SIGNAL ;
    PORT
      LAYER M3 ;
        RECT  54.252 0 54.27 0.037 ;
    END
  END t_k[157]
  PIN t_k[158]
    DIRECTION OUTPUT ;
    USE SIGNAL ;
    PORT
      LAYER M3 ;
        RECT  54.324 0 54.342 0.037 ;
    END
  END t_k[158]
  PIN t_k[159]
    DIRECTION OUTPUT ;
    USE SIGNAL ;
    PORT
      LAYER M3 ;
        RECT  54.396 0 54.414 0.037 ;
    END
  END t_k[159]
  PIN t_k[15]
    DIRECTION OUTPUT ;
    USE SIGNAL ;
    PORT
      LAYER M5 ;
        RECT  39.504 0 39.528 0.084 ;
    END
  END t_k[15]
  PIN t_k[160]
    DIRECTION OUTPUT ;
    USE SIGNAL ;
    PORT
      LAYER M3 ;
        RECT  54.468 0 54.486 0.037 ;
    END
  END t_k[160]
  PIN t_k[161]
    DIRECTION OUTPUT ;
    USE SIGNAL ;
    PORT
      LAYER M3 ;
        RECT  54.54 0 54.558 0.037 ;
    END
  END t_k[161]
  PIN t_k[162]
    DIRECTION OUTPUT ;
    USE SIGNAL ;
    PORT
      LAYER M3 ;
        RECT  54.612 0 54.63 0.037 ;
    END
  END t_k[162]
  PIN t_k[163]
    DIRECTION OUTPUT ;
    USE SIGNAL ;
    PORT
      LAYER M3 ;
        RECT  54.684 0 54.702 0.037 ;
    END
  END t_k[163]
  PIN t_k[164]
    DIRECTION OUTPUT ;
    USE SIGNAL ;
    PORT
      LAYER M3 ;
        RECT  54.756 0 54.774 0.037 ;
    END
  END t_k[164]
  PIN t_k[165]
    DIRECTION OUTPUT ;
    USE SIGNAL ;
    PORT
      LAYER M3 ;
        RECT  54.828 0 54.846 0.037 ;
    END
  END t_k[165]
  PIN t_k[166]
    DIRECTION OUTPUT ;
    USE SIGNAL ;
    PORT
      LAYER M3 ;
        RECT  54.9 0 54.918 0.037 ;
    END
  END t_k[166]
  PIN t_k[167]
    DIRECTION OUTPUT ;
    USE SIGNAL ;
    PORT
      LAYER M3 ;
        RECT  54.972 0 54.99 0.037 ;
    END
  END t_k[167]
  PIN t_k[168]
    DIRECTION OUTPUT ;
    USE SIGNAL ;
    PORT
      LAYER M3 ;
        RECT  55.044 0 55.062 0.037 ;
    END
  END t_k[168]
  PIN t_k[169]
    DIRECTION OUTPUT ;
    USE SIGNAL ;
    PORT
      LAYER M3 ;
        RECT  55.116 0 55.134 0.037 ;
    END
  END t_k[169]
  PIN t_k[16]
    DIRECTION OUTPUT ;
    USE SIGNAL ;
    PORT
      LAYER M5 ;
        RECT  39.6 0 39.624 0.084 ;
    END
  END t_k[16]
  PIN t_k[170]
    DIRECTION OUTPUT ;
    USE SIGNAL ;
    PORT
      LAYER M3 ;
        RECT  55.188 0 55.206 0.037 ;
    END
  END t_k[170]
  PIN t_k[171]
    DIRECTION OUTPUT ;
    USE SIGNAL ;
    PORT
      LAYER M3 ;
        RECT  48.348 0 48.366 0.037 ;
    END
  END t_k[171]
  PIN t_k[172]
    DIRECTION OUTPUT ;
    USE SIGNAL ;
    PORT
      LAYER M3 ;
        RECT  48.42 0 48.438 0.037 ;
    END
  END t_k[172]
  PIN t_k[173]
    DIRECTION OUTPUT ;
    USE SIGNAL ;
    PORT
      LAYER M3 ;
        RECT  48.492 0 48.51 0.037 ;
    END
  END t_k[173]
  PIN t_k[174]
    DIRECTION OUTPUT ;
    USE SIGNAL ;
    PORT
      LAYER M3 ;
        RECT  48.564 0 48.582 0.037 ;
    END
  END t_k[174]
  PIN t_k[175]
    DIRECTION OUTPUT ;
    USE SIGNAL ;
    PORT
      LAYER M3 ;
        RECT  48.636 0 48.654 0.037 ;
    END
  END t_k[175]
  PIN t_k[176]
    DIRECTION OUTPUT ;
    USE SIGNAL ;
    PORT
      LAYER M3 ;
        RECT  48.708 0 48.726 0.037 ;
    END
  END t_k[176]
  PIN t_k[177]
    DIRECTION OUTPUT ;
    USE SIGNAL ;
    PORT
      LAYER M3 ;
        RECT  48.78 0 48.798 0.037 ;
    END
  END t_k[177]
  PIN t_k[178]
    DIRECTION OUTPUT ;
    USE SIGNAL ;
    PORT
      LAYER M3 ;
        RECT  48.852 0 48.87 0.037 ;
    END
  END t_k[178]
  PIN t_k[179]
    DIRECTION OUTPUT ;
    USE SIGNAL ;
    PORT
      LAYER M3 ;
        RECT  48.924 0 48.942 0.037 ;
    END
  END t_k[179]
  PIN t_k[17]
    DIRECTION OUTPUT ;
    USE SIGNAL ;
    PORT
      LAYER M5 ;
        RECT  39.696 0 39.72 0.084 ;
    END
  END t_k[17]
  PIN t_k[180]
    DIRECTION OUTPUT ;
    USE SIGNAL ;
    PORT
      LAYER M3 ;
        RECT  48.996 0 49.014 0.037 ;
    END
  END t_k[180]
  PIN t_k[181]
    DIRECTION OUTPUT ;
    USE SIGNAL ;
    PORT
      LAYER M3 ;
        RECT  49.068 0 49.086 0.037 ;
    END
  END t_k[181]
  PIN t_k[182]
    DIRECTION OUTPUT ;
    USE SIGNAL ;
    PORT
      LAYER M3 ;
        RECT  49.14 0 49.158 0.037 ;
    END
  END t_k[182]
  PIN t_k[183]
    DIRECTION OUTPUT ;
    USE SIGNAL ;
    PORT
      LAYER M3 ;
        RECT  49.212 0 49.23 0.037 ;
    END
  END t_k[183]
  PIN t_k[184]
    DIRECTION OUTPUT ;
    USE SIGNAL ;
    PORT
      LAYER M3 ;
        RECT  49.284 0 49.302 0.037 ;
    END
  END t_k[184]
  PIN t_k[185]
    DIRECTION OUTPUT ;
    USE SIGNAL ;
    PORT
      LAYER M3 ;
        RECT  49.356 0 49.374 0.037 ;
    END
  END t_k[185]
  PIN t_k[186]
    DIRECTION OUTPUT ;
    USE SIGNAL ;
    PORT
      LAYER M3 ;
        RECT  49.428 0 49.446 0.037 ;
    END
  END t_k[186]
  PIN t_k[187]
    DIRECTION OUTPUT ;
    USE SIGNAL ;
    PORT
      LAYER M3 ;
        RECT  49.5 0 49.518 0.037 ;
    END
  END t_k[187]
  PIN t_k[188]
    DIRECTION OUTPUT ;
    USE SIGNAL ;
    PORT
      LAYER M3 ;
        RECT  49.572 0 49.59 0.037 ;
    END
  END t_k[188]
  PIN t_k[189]
    DIRECTION OUTPUT ;
    USE SIGNAL ;
    PORT
      LAYER M3 ;
        RECT  49.644 0 49.662 0.037 ;
    END
  END t_k[189]
  PIN t_k[18]
    DIRECTION OUTPUT ;
    USE SIGNAL ;
    PORT
      LAYER M5 ;
        RECT  39.792 0 39.816 0.084 ;
    END
  END t_k[18]
  PIN t_k[190]
    DIRECTION OUTPUT ;
    USE SIGNAL ;
    PORT
      LAYER M3 ;
        RECT  49.716 0 49.734 0.037 ;
    END
  END t_k[190]
  PIN t_k[191]
    DIRECTION OUTPUT ;
    USE SIGNAL ;
    PORT
      LAYER M3 ;
        RECT  49.788 0 49.806 0.037 ;
    END
  END t_k[191]
  PIN t_k[192]
    DIRECTION OUTPUT ;
    USE SIGNAL ;
    PORT
      LAYER M3 ;
        RECT  49.86 0 49.878 0.037 ;
    END
  END t_k[192]
  PIN t_k[193]
    DIRECTION OUTPUT ;
    USE SIGNAL ;
    PORT
      LAYER M3 ;
        RECT  49.932 0 49.95 0.037 ;
    END
  END t_k[193]
  PIN t_k[194]
    DIRECTION OUTPUT ;
    USE SIGNAL ;
    PORT
      LAYER M3 ;
        RECT  50.004 0 50.022 0.037 ;
    END
  END t_k[194]
  PIN t_k[195]
    DIRECTION OUTPUT ;
    USE SIGNAL ;
    PORT
      LAYER M3 ;
        RECT  50.076 0 50.094 0.037 ;
    END
  END t_k[195]
  PIN t_k[196]
    DIRECTION OUTPUT ;
    USE SIGNAL ;
    PORT
      LAYER M3 ;
        RECT  50.148 0 50.166 0.037 ;
    END
  END t_k[196]
  PIN t_k[197]
    DIRECTION OUTPUT ;
    USE SIGNAL ;
    PORT
      LAYER M3 ;
        RECT  50.22 0 50.238 0.037 ;
    END
  END t_k[197]
  PIN t_k[198]
    DIRECTION OUTPUT ;
    USE SIGNAL ;
    PORT
      LAYER M3 ;
        RECT  50.292 0 50.31 0.037 ;
    END
  END t_k[198]
  PIN t_k[199]
    DIRECTION OUTPUT ;
    USE SIGNAL ;
    PORT
      LAYER M3 ;
        RECT  50.364 0 50.382 0.037 ;
    END
  END t_k[199]
  PIN t_k[19]
    DIRECTION OUTPUT ;
    USE SIGNAL ;
    PORT
      LAYER M5 ;
        RECT  39.888 0 39.912 0.084 ;
    END
  END t_k[19]
  PIN t_k[1]
    DIRECTION OUTPUT ;
    USE SIGNAL ;
    PORT
      LAYER M3 ;
        RECT  30.924 0 30.942 0.037 ;
    END
  END t_k[1]
  PIN t_k[200]
    DIRECTION OUTPUT ;
    USE SIGNAL ;
    PORT
      LAYER M3 ;
        RECT  50.436 0 50.454 0.037 ;
    END
  END t_k[200]
  PIN t_k[201]
    DIRECTION OUTPUT ;
    USE SIGNAL ;
    PORT
      LAYER M3 ;
        RECT  50.508 0 50.526 0.037 ;
    END
  END t_k[201]
  PIN t_k[202]
    DIRECTION OUTPUT ;
    USE SIGNAL ;
    PORT
      LAYER M3 ;
        RECT  50.58 0 50.598 0.037 ;
    END
  END t_k[202]
  PIN t_k[203]
    DIRECTION OUTPUT ;
    USE SIGNAL ;
    PORT
      LAYER M3 ;
        RECT  46.044 0 46.062 0.037 ;
    END
  END t_k[203]
  PIN t_k[204]
    DIRECTION OUTPUT ;
    USE SIGNAL ;
    PORT
      LAYER M3 ;
        RECT  46.116 0 46.134 0.037 ;
    END
  END t_k[204]
  PIN t_k[205]
    DIRECTION OUTPUT ;
    USE SIGNAL ;
    PORT
      LAYER M3 ;
        RECT  46.188 0 46.206 0.037 ;
    END
  END t_k[205]
  PIN t_k[206]
    DIRECTION OUTPUT ;
    USE SIGNAL ;
    PORT
      LAYER M3 ;
        RECT  46.26 0 46.278 0.037 ;
    END
  END t_k[206]
  PIN t_k[207]
    DIRECTION OUTPUT ;
    USE SIGNAL ;
    PORT
      LAYER M3 ;
        RECT  46.332 0 46.35 0.037 ;
    END
  END t_k[207]
  PIN t_k[208]
    DIRECTION OUTPUT ;
    USE SIGNAL ;
    PORT
      LAYER M3 ;
        RECT  46.404 0 46.422 0.037 ;
    END
  END t_k[208]
  PIN t_k[209]
    DIRECTION OUTPUT ;
    USE SIGNAL ;
    PORT
      LAYER M3 ;
        RECT  46.476 0 46.494 0.037 ;
    END
  END t_k[209]
  PIN t_k[20]
    DIRECTION OUTPUT ;
    USE SIGNAL ;
    PORT
      LAYER M5 ;
        RECT  39.984 0 40.008 0.084 ;
    END
  END t_k[20]
  PIN t_k[210]
    DIRECTION OUTPUT ;
    USE SIGNAL ;
    PORT
      LAYER M3 ;
        RECT  46.548 0 46.566 0.037 ;
    END
  END t_k[210]
  PIN t_k[211]
    DIRECTION OUTPUT ;
    USE SIGNAL ;
    PORT
      LAYER M3 ;
        RECT  46.62 0 46.638 0.037 ;
    END
  END t_k[211]
  PIN t_k[212]
    DIRECTION OUTPUT ;
    USE SIGNAL ;
    PORT
      LAYER M3 ;
        RECT  46.692 0 46.71 0.037 ;
    END
  END t_k[212]
  PIN t_k[213]
    DIRECTION OUTPUT ;
    USE SIGNAL ;
    PORT
      LAYER M3 ;
        RECT  46.764 0 46.782 0.037 ;
    END
  END t_k[213]
  PIN t_k[214]
    DIRECTION OUTPUT ;
    USE SIGNAL ;
    PORT
      LAYER M3 ;
        RECT  46.836 0 46.854 0.037 ;
    END
  END t_k[214]
  PIN t_k[215]
    DIRECTION OUTPUT ;
    USE SIGNAL ;
    PORT
      LAYER M3 ;
        RECT  46.908 0 46.926 0.037 ;
    END
  END t_k[215]
  PIN t_k[216]
    DIRECTION OUTPUT ;
    USE SIGNAL ;
    PORT
      LAYER M3 ;
        RECT  46.98 0 46.998 0.037 ;
    END
  END t_k[216]
  PIN t_k[217]
    DIRECTION OUTPUT ;
    USE SIGNAL ;
    PORT
      LAYER M3 ;
        RECT  47.052 0 47.07 0.037 ;
    END
  END t_k[217]
  PIN t_k[218]
    DIRECTION OUTPUT ;
    USE SIGNAL ;
    PORT
      LAYER M3 ;
        RECT  47.124 0 47.142 0.037 ;
    END
  END t_k[218]
  PIN t_k[219]
    DIRECTION OUTPUT ;
    USE SIGNAL ;
    PORT
      LAYER M3 ;
        RECT  47.196 0 47.214 0.037 ;
    END
  END t_k[219]
  PIN t_k[21]
    DIRECTION OUTPUT ;
    USE SIGNAL ;
    PORT
      LAYER M5 ;
        RECT  40.08 0 40.104 0.084 ;
    END
  END t_k[21]
  PIN t_k[220]
    DIRECTION OUTPUT ;
    USE SIGNAL ;
    PORT
      LAYER M3 ;
        RECT  47.268 0 47.286 0.037 ;
    END
  END t_k[220]
  PIN t_k[221]
    DIRECTION OUTPUT ;
    USE SIGNAL ;
    PORT
      LAYER M3 ;
        RECT  47.34 0 47.358 0.037 ;
    END
  END t_k[221]
  PIN t_k[222]
    DIRECTION OUTPUT ;
    USE SIGNAL ;
    PORT
      LAYER M3 ;
        RECT  47.412 0 47.43 0.037 ;
    END
  END t_k[222]
  PIN t_k[223]
    DIRECTION OUTPUT ;
    USE SIGNAL ;
    PORT
      LAYER M3 ;
        RECT  47.484 0 47.502 0.037 ;
    END
  END t_k[223]
  PIN t_k[224]
    DIRECTION OUTPUT ;
    USE SIGNAL ;
    PORT
      LAYER M3 ;
        RECT  47.556 0 47.574 0.037 ;
    END
  END t_k[224]
  PIN t_k[225]
    DIRECTION OUTPUT ;
    USE SIGNAL ;
    PORT
      LAYER M3 ;
        RECT  47.628 0 47.646 0.037 ;
    END
  END t_k[225]
  PIN t_k[226]
    DIRECTION OUTPUT ;
    USE SIGNAL ;
    PORT
      LAYER M3 ;
        RECT  47.7 0 47.718 0.037 ;
    END
  END t_k[226]
  PIN t_k[227]
    DIRECTION OUTPUT ;
    USE SIGNAL ;
    PORT
      LAYER M3 ;
        RECT  47.772 0 47.79 0.037 ;
    END
  END t_k[227]
  PIN t_k[228]
    DIRECTION OUTPUT ;
    USE SIGNAL ;
    PORT
      LAYER M3 ;
        RECT  47.844 0 47.862 0.037 ;
    END
  END t_k[228]
  PIN t_k[229]
    DIRECTION OUTPUT ;
    USE SIGNAL ;
    PORT
      LAYER M3 ;
        RECT  47.916 0 47.934 0.037 ;
    END
  END t_k[229]
  PIN t_k[22]
    DIRECTION OUTPUT ;
    USE SIGNAL ;
    PORT
      LAYER M5 ;
        RECT  40.176 0 40.2 0.084 ;
    END
  END t_k[22]
  PIN t_k[230]
    DIRECTION OUTPUT ;
    USE SIGNAL ;
    PORT
      LAYER M3 ;
        RECT  47.988 0 48.006 0.037 ;
    END
  END t_k[230]
  PIN t_k[231]
    DIRECTION OUTPUT ;
    USE SIGNAL ;
    PORT
      LAYER M3 ;
        RECT  48.06 0 48.078 0.037 ;
    END
  END t_k[231]
  PIN t_k[232]
    DIRECTION OUTPUT ;
    USE SIGNAL ;
    PORT
      LAYER M3 ;
        RECT  48.132 0 48.15 0.037 ;
    END
  END t_k[232]
  PIN t_k[233]
    DIRECTION OUTPUT ;
    USE SIGNAL ;
    PORT
      LAYER M3 ;
        RECT  48.204 0 48.222 0.037 ;
    END
  END t_k[233]
  PIN t_k[234]
    DIRECTION OUTPUT ;
    USE SIGNAL ;
    PORT
      LAYER M3 ;
        RECT  48.276 0 48.294 0.037 ;
    END
  END t_k[234]
  PIN t_k[235]
    DIRECTION OUTPUT ;
    USE SIGNAL ;
    PORT
      LAYER M3 ;
        RECT  55.26 0 55.278 0.037 ;
    END
  END t_k[235]
  PIN t_k[236]
    DIRECTION OUTPUT ;
    USE SIGNAL ;
    PORT
      LAYER M3 ;
        RECT  55.332 0 55.35 0.037 ;
    END
  END t_k[236]
  PIN t_k[237]
    DIRECTION OUTPUT ;
    USE SIGNAL ;
    PORT
      LAYER M3 ;
        RECT  55.404 0 55.422 0.037 ;
    END
  END t_k[237]
  PIN t_k[238]
    DIRECTION OUTPUT ;
    USE SIGNAL ;
    PORT
      LAYER M3 ;
        RECT  55.476 0 55.494 0.037 ;
    END
  END t_k[238]
  PIN t_k[239]
    DIRECTION OUTPUT ;
    USE SIGNAL ;
    PORT
      LAYER M3 ;
        RECT  55.548 0 55.566 0.037 ;
    END
  END t_k[239]
  PIN t_k[23]
    DIRECTION OUTPUT ;
    USE SIGNAL ;
    PORT
      LAYER M5 ;
        RECT  40.272 0 40.296 0.084 ;
    END
  END t_k[23]
  PIN t_k[240]
    DIRECTION OUTPUT ;
    USE SIGNAL ;
    PORT
      LAYER M3 ;
        RECT  55.62 0 55.638 0.037 ;
    END
  END t_k[240]
  PIN t_k[241]
    DIRECTION OUTPUT ;
    USE SIGNAL ;
    PORT
      LAYER M3 ;
        RECT  55.692 0 55.71 0.037 ;
    END
  END t_k[241]
  PIN t_k[242]
    DIRECTION OUTPUT ;
    USE SIGNAL ;
    PORT
      LAYER M3 ;
        RECT  55.764 0 55.782 0.037 ;
    END
  END t_k[242]
  PIN t_k[243]
    DIRECTION OUTPUT ;
    USE SIGNAL ;
    PORT
      LAYER M3 ;
        RECT  55.836 0 55.854 0.037 ;
    END
  END t_k[243]
  PIN t_k[244]
    DIRECTION OUTPUT ;
    USE SIGNAL ;
    PORT
      LAYER M3 ;
        RECT  55.908 0 55.926 0.037 ;
    END
  END t_k[244]
  PIN t_k[245]
    DIRECTION OUTPUT ;
    USE SIGNAL ;
    PORT
      LAYER M3 ;
        RECT  55.98 0 55.998 0.037 ;
    END
  END t_k[245]
  PIN t_k[246]
    DIRECTION OUTPUT ;
    USE SIGNAL ;
    PORT
      LAYER M3 ;
        RECT  56.052 0 56.07 0.037 ;
    END
  END t_k[246]
  PIN t_k[247]
    DIRECTION OUTPUT ;
    USE SIGNAL ;
    PORT
      LAYER M3 ;
        RECT  56.124 0 56.142 0.037 ;
    END
  END t_k[247]
  PIN t_k[248]
    DIRECTION OUTPUT ;
    USE SIGNAL ;
    PORT
      LAYER M3 ;
        RECT  56.196 0 56.214 0.037 ;
    END
  END t_k[248]
  PIN t_k[249]
    DIRECTION OUTPUT ;
    USE SIGNAL ;
    PORT
      LAYER M3 ;
        RECT  56.268 0 56.286 0.037 ;
    END
  END t_k[249]
  PIN t_k[24]
    DIRECTION OUTPUT ;
    USE SIGNAL ;
    PORT
      LAYER M5 ;
        RECT  40.368 0 40.392 0.084 ;
    END
  END t_k[24]
  PIN t_k[250]
    DIRECTION OUTPUT ;
    USE SIGNAL ;
    PORT
      LAYER M3 ;
        RECT  56.34 0 56.358 0.037 ;
    END
  END t_k[250]
  PIN t_k[251]
    DIRECTION OUTPUT ;
    USE SIGNAL ;
    PORT
      LAYER M3 ;
        RECT  56.412 0 56.43 0.037 ;
    END
  END t_k[251]
  PIN t_k[252]
    DIRECTION OUTPUT ;
    USE SIGNAL ;
    PORT
      LAYER M3 ;
        RECT  56.484 0 56.502 0.037 ;
    END
  END t_k[252]
  PIN t_k[253]
    DIRECTION OUTPUT ;
    USE SIGNAL ;
    PORT
      LAYER M3 ;
        RECT  56.556 0 56.574 0.037 ;
    END
  END t_k[253]
  PIN t_k[254]
    DIRECTION OUTPUT ;
    USE SIGNAL ;
    PORT
      LAYER M3 ;
        RECT  56.628 0 56.646 0.037 ;
    END
  END t_k[254]
  PIN t_k[255]
    DIRECTION OUTPUT ;
    USE SIGNAL ;
    PORT
      LAYER M3 ;
        RECT  56.7 0 56.718 0.037 ;
    END
  END t_k[255]
  PIN t_k[256]
    DIRECTION OUTPUT ;
    USE SIGNAL ;
    PORT
      LAYER M3 ;
        RECT  56.772 0 56.79 0.037 ;
    END
  END t_k[256]
  PIN t_k[257]
    DIRECTION OUTPUT ;
    USE SIGNAL ;
    PORT
      LAYER M3 ;
        RECT  56.844 0 56.862 0.037 ;
    END
  END t_k[257]
  PIN t_k[258]
    DIRECTION OUTPUT ;
    USE SIGNAL ;
    PORT
      LAYER M3 ;
        RECT  56.916 0 56.934 0.037 ;
    END
  END t_k[258]
  PIN t_k[259]
    DIRECTION OUTPUT ;
    USE SIGNAL ;
    PORT
      LAYER M3 ;
        RECT  56.988 0 57.006 0.037 ;
    END
  END t_k[259]
  PIN t_k[25]
    DIRECTION OUTPUT ;
    USE SIGNAL ;
    PORT
      LAYER M5 ;
        RECT  40.464 0 40.488 0.084 ;
    END
  END t_k[25]
  PIN t_k[260]
    DIRECTION OUTPUT ;
    USE SIGNAL ;
    PORT
      LAYER M3 ;
        RECT  57.06 0 57.078 0.037 ;
    END
  END t_k[260]
  PIN t_k[261]
    DIRECTION OUTPUT ;
    USE SIGNAL ;
    PORT
      LAYER M3 ;
        RECT  57.132 0 57.15 0.037 ;
    END
  END t_k[261]
  PIN t_k[262]
    DIRECTION OUTPUT ;
    USE SIGNAL ;
    PORT
      LAYER M3 ;
        RECT  57.204 0 57.222 0.037 ;
    END
  END t_k[262]
  PIN t_k[263]
    DIRECTION OUTPUT ;
    USE SIGNAL ;
    PORT
      LAYER M3 ;
        RECT  57.276 0 57.294 0.037 ;
    END
  END t_k[263]
  PIN t_k[264]
    DIRECTION OUTPUT ;
    USE SIGNAL ;
    PORT
      LAYER M3 ;
        RECT  57.348 0 57.366 0.037 ;
    END
  END t_k[264]
  PIN t_k[265]
    DIRECTION OUTPUT ;
    USE SIGNAL ;
    PORT
      LAYER M3 ;
        RECT  57.42 0 57.438 0.037 ;
    END
  END t_k[265]
  PIN t_k[266]
    DIRECTION OUTPUT ;
    USE SIGNAL ;
    PORT
      LAYER M3 ;
        RECT  57.492 0 57.51 0.037 ;
    END
  END t_k[266]
  PIN t_k[267]
    DIRECTION OUTPUT ;
    USE SIGNAL ;
    PORT
      LAYER M3 ;
        RECT  50.652 0 50.67 0.037 ;
    END
  END t_k[267]
  PIN t_k[268]
    DIRECTION OUTPUT ;
    USE SIGNAL ;
    PORT
      LAYER M3 ;
        RECT  50.724 0 50.742 0.037 ;
    END
  END t_k[268]
  PIN t_k[269]
    DIRECTION OUTPUT ;
    USE SIGNAL ;
    PORT
      LAYER M3 ;
        RECT  50.796 0 50.814 0.037 ;
    END
  END t_k[269]
  PIN t_k[26]
    DIRECTION OUTPUT ;
    USE SIGNAL ;
    PORT
      LAYER M5 ;
        RECT  40.56 0 40.584 0.084 ;
    END
  END t_k[26]
  PIN t_k[270]
    DIRECTION OUTPUT ;
    USE SIGNAL ;
    PORT
      LAYER M3 ;
        RECT  50.868 0 50.886 0.037 ;
    END
  END t_k[270]
  PIN t_k[271]
    DIRECTION OUTPUT ;
    USE SIGNAL ;
    PORT
      LAYER M3 ;
        RECT  50.94 0 50.958 0.037 ;
    END
  END t_k[271]
  PIN t_k[272]
    DIRECTION OUTPUT ;
    USE SIGNAL ;
    PORT
      LAYER M3 ;
        RECT  51.012 0 51.03 0.037 ;
    END
  END t_k[272]
  PIN t_k[273]
    DIRECTION OUTPUT ;
    USE SIGNAL ;
    PORT
      LAYER M3 ;
        RECT  51.084 0 51.102 0.037 ;
    END
  END t_k[273]
  PIN t_k[274]
    DIRECTION OUTPUT ;
    USE SIGNAL ;
    PORT
      LAYER M3 ;
        RECT  51.156 0 51.174 0.037 ;
    END
  END t_k[274]
  PIN t_k[275]
    DIRECTION OUTPUT ;
    USE SIGNAL ;
    PORT
      LAYER M3 ;
        RECT  51.228 0 51.246 0.037 ;
    END
  END t_k[275]
  PIN t_k[276]
    DIRECTION OUTPUT ;
    USE SIGNAL ;
    PORT
      LAYER M3 ;
        RECT  51.3 0 51.318 0.037 ;
    END
  END t_k[276]
  PIN t_k[277]
    DIRECTION OUTPUT ;
    USE SIGNAL ;
    PORT
      LAYER M3 ;
        RECT  51.372 0 51.39 0.037 ;
    END
  END t_k[277]
  PIN t_k[278]
    DIRECTION OUTPUT ;
    USE SIGNAL ;
    PORT
      LAYER M3 ;
        RECT  51.444 0 51.462 0.037 ;
    END
  END t_k[278]
  PIN t_k[279]
    DIRECTION OUTPUT ;
    USE SIGNAL ;
    PORT
      LAYER M3 ;
        RECT  51.516 0 51.534 0.037 ;
    END
  END t_k[279]
  PIN t_k[27]
    DIRECTION OUTPUT ;
    USE SIGNAL ;
    PORT
      LAYER M5 ;
        RECT  40.656 0 40.68 0.084 ;
    END
  END t_k[27]
  PIN t_k[280]
    DIRECTION OUTPUT ;
    USE SIGNAL ;
    PORT
      LAYER M3 ;
        RECT  51.588 0 51.606 0.037 ;
    END
  END t_k[280]
  PIN t_k[281]
    DIRECTION OUTPUT ;
    USE SIGNAL ;
    PORT
      LAYER M3 ;
        RECT  51.66 0 51.678 0.037 ;
    END
  END t_k[281]
  PIN t_k[282]
    DIRECTION OUTPUT ;
    USE SIGNAL ;
    PORT
      LAYER M3 ;
        RECT  51.732 0 51.75 0.037 ;
    END
  END t_k[282]
  PIN t_k[283]
    DIRECTION OUTPUT ;
    USE SIGNAL ;
    PORT
      LAYER M3 ;
        RECT  51.804 0 51.822 0.037 ;
    END
  END t_k[283]
  PIN t_k[284]
    DIRECTION OUTPUT ;
    USE SIGNAL ;
    PORT
      LAYER M3 ;
        RECT  51.876 0 51.894 0.037 ;
    END
  END t_k[284]
  PIN t_k[285]
    DIRECTION OUTPUT ;
    USE SIGNAL ;
    PORT
      LAYER M3 ;
        RECT  51.948 0 51.966 0.037 ;
    END
  END t_k[285]
  PIN t_k[286]
    DIRECTION OUTPUT ;
    USE SIGNAL ;
    PORT
      LAYER M3 ;
        RECT  52.02 0 52.038 0.037 ;
    END
  END t_k[286]
  PIN t_k[287]
    DIRECTION OUTPUT ;
    USE SIGNAL ;
    PORT
      LAYER M3 ;
        RECT  52.092 0 52.11 0.037 ;
    END
  END t_k[287]
  PIN t_k[288]
    DIRECTION OUTPUT ;
    USE SIGNAL ;
    PORT
      LAYER M3 ;
        RECT  52.164 0 52.182 0.037 ;
    END
  END t_k[288]
  PIN t_k[289]
    DIRECTION OUTPUT ;
    USE SIGNAL ;
    PORT
      LAYER M3 ;
        RECT  52.236 0 52.254 0.037 ;
    END
  END t_k[289]
  PIN t_k[28]
    DIRECTION OUTPUT ;
    USE SIGNAL ;
    PORT
      LAYER M5 ;
        RECT  40.752 0 40.776 0.084 ;
    END
  END t_k[28]
  PIN t_k[290]
    DIRECTION OUTPUT ;
    USE SIGNAL ;
    PORT
      LAYER M3 ;
        RECT  52.308 0 52.326 0.037 ;
    END
  END t_k[290]
  PIN t_k[291]
    DIRECTION OUTPUT ;
    USE SIGNAL ;
    PORT
      LAYER M3 ;
        RECT  52.38 0 52.398 0.037 ;
    END
  END t_k[291]
  PIN t_k[292]
    DIRECTION OUTPUT ;
    USE SIGNAL ;
    PORT
      LAYER M3 ;
        RECT  52.452 0 52.47 0.037 ;
    END
  END t_k[292]
  PIN t_k[293]
    DIRECTION OUTPUT ;
    USE SIGNAL ;
    PORT
      LAYER M3 ;
        RECT  52.524 0 52.542 0.037 ;
    END
  END t_k[293]
  PIN t_k[294]
    DIRECTION OUTPUT ;
    USE SIGNAL ;
    PORT
      LAYER M3 ;
        RECT  52.596 0 52.614 0.037 ;
    END
  END t_k[294]
  PIN t_k[295]
    DIRECTION OUTPUT ;
    USE SIGNAL ;
    PORT
      LAYER M3 ;
        RECT  52.668 0 52.686 0.037 ;
    END
  END t_k[295]
  PIN t_k[296]
    DIRECTION OUTPUT ;
    USE SIGNAL ;
    PORT
      LAYER M3 ;
        RECT  52.74 0 52.758 0.037 ;
    END
  END t_k[296]
  PIN t_k[297]
    DIRECTION OUTPUT ;
    USE SIGNAL ;
    PORT
      LAYER M3 ;
        RECT  52.812 0 52.83 0.037 ;
    END
  END t_k[297]
  PIN t_k[298]
    DIRECTION OUTPUT ;
    USE SIGNAL ;
    PORT
      LAYER M3 ;
        RECT  52.884 0 52.902 0.037 ;
    END
  END t_k[298]
  PIN t_k[299]
    DIRECTION OUTPUT ;
    USE SIGNAL ;
    PORT
      LAYER M3 ;
        RECT  43.74 0 43.758 0.037 ;
    END
  END t_k[299]
  PIN t_k[29]
    DIRECTION OUTPUT ;
    USE SIGNAL ;
    PORT
      LAYER M5 ;
        RECT  40.848 0 40.872 0.084 ;
    END
  END t_k[29]
  PIN t_k[2]
    DIRECTION OUTPUT ;
    USE SIGNAL ;
    PORT
      LAYER M3 ;
        RECT  30.996 0 31.014 0.037 ;
    END
  END t_k[2]
  PIN t_k[300]
    DIRECTION OUTPUT ;
    USE SIGNAL ;
    PORT
      LAYER M3 ;
        RECT  43.812 0 43.83 0.037 ;
    END
  END t_k[300]
  PIN t_k[301]
    DIRECTION OUTPUT ;
    USE SIGNAL ;
    PORT
      LAYER M3 ;
        RECT  43.884 0 43.902 0.037 ;
    END
  END t_k[301]
  PIN t_k[302]
    DIRECTION OUTPUT ;
    USE SIGNAL ;
    PORT
      LAYER M3 ;
        RECT  43.956 0 43.974 0.037 ;
    END
  END t_k[302]
  PIN t_k[303]
    DIRECTION OUTPUT ;
    USE SIGNAL ;
    PORT
      LAYER M3 ;
        RECT  44.028 0 44.046 0.037 ;
    END
  END t_k[303]
  PIN t_k[304]
    DIRECTION OUTPUT ;
    USE SIGNAL ;
    PORT
      LAYER M3 ;
        RECT  44.1 0 44.118 0.037 ;
    END
  END t_k[304]
  PIN t_k[305]
    DIRECTION OUTPUT ;
    USE SIGNAL ;
    PORT
      LAYER M3 ;
        RECT  44.172 0 44.19 0.037 ;
    END
  END t_k[305]
  PIN t_k[306]
    DIRECTION OUTPUT ;
    USE SIGNAL ;
    PORT
      LAYER M3 ;
        RECT  44.244 0 44.262 0.037 ;
    END
  END t_k[306]
  PIN t_k[307]
    DIRECTION OUTPUT ;
    USE SIGNAL ;
    PORT
      LAYER M3 ;
        RECT  44.316 0 44.334 0.037 ;
    END
  END t_k[307]
  PIN t_k[308]
    DIRECTION OUTPUT ;
    USE SIGNAL ;
    PORT
      LAYER M3 ;
        RECT  44.388 0 44.406 0.037 ;
    END
  END t_k[308]
  PIN t_k[309]
    DIRECTION OUTPUT ;
    USE SIGNAL ;
    PORT
      LAYER M3 ;
        RECT  44.46 0 44.478 0.037 ;
    END
  END t_k[309]
  PIN t_k[30]
    DIRECTION OUTPUT ;
    USE SIGNAL ;
    PORT
      LAYER M5 ;
        RECT  40.944 0 40.968 0.084 ;
    END
  END t_k[30]
  PIN t_k[310]
    DIRECTION OUTPUT ;
    USE SIGNAL ;
    PORT
      LAYER M3 ;
        RECT  44.532 0 44.55 0.037 ;
    END
  END t_k[310]
  PIN t_k[311]
    DIRECTION OUTPUT ;
    USE SIGNAL ;
    PORT
      LAYER M3 ;
        RECT  44.604 0 44.622 0.037 ;
    END
  END t_k[311]
  PIN t_k[312]
    DIRECTION OUTPUT ;
    USE SIGNAL ;
    PORT
      LAYER M3 ;
        RECT  44.676 0 44.694 0.037 ;
    END
  END t_k[312]
  PIN t_k[313]
    DIRECTION OUTPUT ;
    USE SIGNAL ;
    PORT
      LAYER M3 ;
        RECT  44.748 0 44.766 0.037 ;
    END
  END t_k[313]
  PIN t_k[314]
    DIRECTION OUTPUT ;
    USE SIGNAL ;
    PORT
      LAYER M3 ;
        RECT  44.82 0 44.838 0.037 ;
    END
  END t_k[314]
  PIN t_k[315]
    DIRECTION OUTPUT ;
    USE SIGNAL ;
    PORT
      LAYER M3 ;
        RECT  44.892 0 44.91 0.037 ;
    END
  END t_k[315]
  PIN t_k[316]
    DIRECTION OUTPUT ;
    USE SIGNAL ;
    PORT
      LAYER M3 ;
        RECT  44.964 0 44.982 0.037 ;
    END
  END t_k[316]
  PIN t_k[317]
    DIRECTION OUTPUT ;
    USE SIGNAL ;
    PORT
      LAYER M3 ;
        RECT  45.036 0 45.054 0.037 ;
    END
  END t_k[317]
  PIN t_k[318]
    DIRECTION OUTPUT ;
    USE SIGNAL ;
    PORT
      LAYER M3 ;
        RECT  45.108 0 45.126 0.037 ;
    END
  END t_k[318]
  PIN t_k[319]
    DIRECTION OUTPUT ;
    USE SIGNAL ;
    PORT
      LAYER M3 ;
        RECT  45.18 0 45.198 0.037 ;
    END
  END t_k[319]
  PIN t_k[31]
    DIRECTION OUTPUT ;
    USE SIGNAL ;
    PORT
      LAYER M5 ;
        RECT  41.04 0 41.064 0.084 ;
    END
  END t_k[31]
  PIN t_k[320]
    DIRECTION OUTPUT ;
    USE SIGNAL ;
    PORT
      LAYER M3 ;
        RECT  45.252 0 45.27 0.037 ;
    END
  END t_k[320]
  PIN t_k[321]
    DIRECTION OUTPUT ;
    USE SIGNAL ;
    PORT
      LAYER M3 ;
        RECT  45.324 0 45.342 0.037 ;
    END
  END t_k[321]
  PIN t_k[322]
    DIRECTION OUTPUT ;
    USE SIGNAL ;
    PORT
      LAYER M3 ;
        RECT  45.396 0 45.414 0.037 ;
    END
  END t_k[322]
  PIN t_k[323]
    DIRECTION OUTPUT ;
    USE SIGNAL ;
    PORT
      LAYER M3 ;
        RECT  45.468 0 45.486 0.037 ;
    END
  END t_k[323]
  PIN t_k[324]
    DIRECTION OUTPUT ;
    USE SIGNAL ;
    PORT
      LAYER M3 ;
        RECT  45.54 0 45.558 0.037 ;
    END
  END t_k[324]
  PIN t_k[325]
    DIRECTION OUTPUT ;
    USE SIGNAL ;
    PORT
      LAYER M3 ;
        RECT  45.612 0 45.63 0.037 ;
    END
  END t_k[325]
  PIN t_k[326]
    DIRECTION OUTPUT ;
    USE SIGNAL ;
    PORT
      LAYER M3 ;
        RECT  45.684 0 45.702 0.037 ;
    END
  END t_k[326]
  PIN t_k[327]
    DIRECTION OUTPUT ;
    USE SIGNAL ;
    PORT
      LAYER M3 ;
        RECT  45.756 0 45.774 0.037 ;
    END
  END t_k[327]
  PIN t_k[328]
    DIRECTION OUTPUT ;
    USE SIGNAL ;
    PORT
      LAYER M3 ;
        RECT  45.828 0 45.846 0.037 ;
    END
  END t_k[328]
  PIN t_k[329]
    DIRECTION OUTPUT ;
    USE SIGNAL ;
    PORT
      LAYER M3 ;
        RECT  45.9 0 45.918 0.037 ;
    END
  END t_k[329]
  PIN t_k[32]
    DIRECTION OUTPUT ;
    USE SIGNAL ;
    PORT
      LAYER M5 ;
        RECT  41.136 0 41.16 0.084 ;
    END
  END t_k[32]
  PIN t_k[330]
    DIRECTION OUTPUT ;
    USE SIGNAL ;
    PORT
      LAYER M3 ;
        RECT  45.972 0 45.99 0.037 ;
    END
  END t_k[330]
  PIN t_k[331]
    DIRECTION OUTPUT ;
    USE SIGNAL ;
    PORT
      LAYER M3 ;
        RECT  38.556 0 38.574 0.037 ;
    END
  END t_k[331]
  PIN t_k[332]
    DIRECTION OUTPUT ;
    USE SIGNAL ;
    PORT
      LAYER M3 ;
        RECT  38.628 0 38.646 0.037 ;
    END
  END t_k[332]
  PIN t_k[333]
    DIRECTION OUTPUT ;
    USE SIGNAL ;
    PORT
      LAYER M3 ;
        RECT  38.7 0 38.718 0.037 ;
    END
  END t_k[333]
  PIN t_k[334]
    DIRECTION OUTPUT ;
    USE SIGNAL ;
    PORT
      LAYER M3 ;
        RECT  38.772 0 38.79 0.037 ;
    END
  END t_k[334]
  PIN t_k[335]
    DIRECTION OUTPUT ;
    USE SIGNAL ;
    PORT
      LAYER M3 ;
        RECT  38.844 0 38.862 0.037 ;
    END
  END t_k[335]
  PIN t_k[336]
    DIRECTION OUTPUT ;
    USE SIGNAL ;
    PORT
      LAYER M3 ;
        RECT  38.916 0 38.934 0.037 ;
    END
  END t_k[336]
  PIN t_k[337]
    DIRECTION OUTPUT ;
    USE SIGNAL ;
    PORT
      LAYER M3 ;
        RECT  38.988 0 39.006 0.037 ;
    END
  END t_k[337]
  PIN t_k[338]
    DIRECTION OUTPUT ;
    USE SIGNAL ;
    PORT
      LAYER M3 ;
        RECT  39.06 0 39.078 0.037 ;
    END
  END t_k[338]
  PIN t_k[339]
    DIRECTION OUTPUT ;
    USE SIGNAL ;
    PORT
      LAYER M3 ;
        RECT  39.132 0 39.15 0.037 ;
    END
  END t_k[339]
  PIN t_k[33]
    DIRECTION OUTPUT ;
    USE SIGNAL ;
    PORT
      LAYER M5 ;
        RECT  41.232 0 41.256 0.084 ;
    END
  END t_k[33]
  PIN t_k[340]
    DIRECTION OUTPUT ;
    USE SIGNAL ;
    PORT
      LAYER M3 ;
        RECT  39.204 0 39.222 0.037 ;
    END
  END t_k[340]
  PIN t_k[341]
    DIRECTION OUTPUT ;
    USE SIGNAL ;
    PORT
      LAYER M3 ;
        RECT  39.276 0 39.294 0.037 ;
    END
  END t_k[341]
  PIN t_k[342]
    DIRECTION OUTPUT ;
    USE SIGNAL ;
    PORT
      LAYER M3 ;
        RECT  39.348 0 39.366 0.037 ;
    END
  END t_k[342]
  PIN t_k[343]
    DIRECTION OUTPUT ;
    USE SIGNAL ;
    PORT
      LAYER M3 ;
        RECT  39.42 0 39.438 0.037 ;
    END
  END t_k[343]
  PIN t_k[344]
    DIRECTION OUTPUT ;
    USE SIGNAL ;
    PORT
      LAYER M3 ;
        RECT  39.492 0 39.51 0.037 ;
    END
  END t_k[344]
  PIN t_k[345]
    DIRECTION OUTPUT ;
    USE SIGNAL ;
    PORT
      LAYER M3 ;
        RECT  39.564 0 39.582 0.037 ;
    END
  END t_k[345]
  PIN t_k[346]
    DIRECTION OUTPUT ;
    USE SIGNAL ;
    PORT
      LAYER M3 ;
        RECT  39.636 0 39.654 0.037 ;
    END
  END t_k[346]
  PIN t_k[347]
    DIRECTION OUTPUT ;
    USE SIGNAL ;
    PORT
      LAYER M3 ;
        RECT  39.708 0 39.726 0.037 ;
    END
  END t_k[347]
  PIN t_k[348]
    DIRECTION OUTPUT ;
    USE SIGNAL ;
    PORT
      LAYER M3 ;
        RECT  39.78 0 39.798 0.037 ;
    END
  END t_k[348]
  PIN t_k[349]
    DIRECTION OUTPUT ;
    USE SIGNAL ;
    PORT
      LAYER M3 ;
        RECT  39.852 0 39.87 0.037 ;
    END
  END t_k[349]
  PIN t_k[34]
    DIRECTION OUTPUT ;
    USE SIGNAL ;
    PORT
      LAYER M5 ;
        RECT  41.328 0 41.352 0.084 ;
    END
  END t_k[34]
  PIN t_k[350]
    DIRECTION OUTPUT ;
    USE SIGNAL ;
    PORT
      LAYER M3 ;
        RECT  39.924 0 39.942 0.037 ;
    END
  END t_k[350]
  PIN t_k[351]
    DIRECTION OUTPUT ;
    USE SIGNAL ;
    PORT
      LAYER M3 ;
        RECT  39.996 0 40.014 0.037 ;
    END
  END t_k[351]
  PIN t_k[352]
    DIRECTION OUTPUT ;
    USE SIGNAL ;
    PORT
      LAYER M3 ;
        RECT  40.068 0 40.086 0.037 ;
    END
  END t_k[352]
  PIN t_k[353]
    DIRECTION OUTPUT ;
    USE SIGNAL ;
    PORT
      LAYER M3 ;
        RECT  40.14 0 40.158 0.037 ;
    END
  END t_k[353]
  PIN t_k[354]
    DIRECTION OUTPUT ;
    USE SIGNAL ;
    PORT
      LAYER M3 ;
        RECT  40.212 0 40.23 0.037 ;
    END
  END t_k[354]
  PIN t_k[355]
    DIRECTION OUTPUT ;
    USE SIGNAL ;
    PORT
      LAYER M3 ;
        RECT  40.284 0 40.302 0.037 ;
    END
  END t_k[355]
  PIN t_k[356]
    DIRECTION OUTPUT ;
    USE SIGNAL ;
    PORT
      LAYER M3 ;
        RECT  40.356 0 40.374 0.037 ;
    END
  END t_k[356]
  PIN t_k[357]
    DIRECTION OUTPUT ;
    USE SIGNAL ;
    PORT
      LAYER M3 ;
        RECT  40.428 0 40.446 0.037 ;
    END
  END t_k[357]
  PIN t_k[358]
    DIRECTION OUTPUT ;
    USE SIGNAL ;
    PORT
      LAYER M3 ;
        RECT  40.5 0 40.518 0.037 ;
    END
  END t_k[358]
  PIN t_k[359]
    DIRECTION OUTPUT ;
    USE SIGNAL ;
    PORT
      LAYER M3 ;
        RECT  40.572 0 40.59 0.037 ;
    END
  END t_k[359]
  PIN t_k[35]
    DIRECTION OUTPUT ;
    USE SIGNAL ;
    PORT
      LAYER M5 ;
        RECT  41.424 0 41.448 0.084 ;
    END
  END t_k[35]
  PIN t_k[360]
    DIRECTION OUTPUT ;
    USE SIGNAL ;
    PORT
      LAYER M3 ;
        RECT  40.644 0 40.662 0.037 ;
    END
  END t_k[360]
  PIN t_k[361]
    DIRECTION OUTPUT ;
    USE SIGNAL ;
    PORT
      LAYER M3 ;
        RECT  40.716 0 40.734 0.037 ;
    END
  END t_k[361]
  PIN t_k[362]
    DIRECTION OUTPUT ;
    USE SIGNAL ;
    PORT
      LAYER M3 ;
        RECT  40.788 0 40.806 0.037 ;
    END
  END t_k[362]
  PIN t_k[363]
    DIRECTION OUTPUT ;
    USE SIGNAL ;
    PORT
      LAYER M3 ;
        RECT  40.86 0 40.878 0.037 ;
    END
  END t_k[363]
  PIN t_k[364]
    DIRECTION OUTPUT ;
    USE SIGNAL ;
    PORT
      LAYER M3 ;
        RECT  40.932 0 40.95 0.037 ;
    END
  END t_k[364]
  PIN t_k[365]
    DIRECTION OUTPUT ;
    USE SIGNAL ;
    PORT
      LAYER M3 ;
        RECT  41.004 0 41.022 0.037 ;
    END
  END t_k[365]
  PIN t_k[366]
    DIRECTION OUTPUT ;
    USE SIGNAL ;
    PORT
      LAYER M3 ;
        RECT  41.076 0 41.094 0.037 ;
    END
  END t_k[366]
  PIN t_k[367]
    DIRECTION OUTPUT ;
    USE SIGNAL ;
    PORT
      LAYER M3 ;
        RECT  41.148 0 41.166 0.037 ;
    END
  END t_k[367]
  PIN t_k[368]
    DIRECTION OUTPUT ;
    USE SIGNAL ;
    PORT
      LAYER M3 ;
        RECT  41.22 0 41.238 0.037 ;
    END
  END t_k[368]
  PIN t_k[369]
    DIRECTION OUTPUT ;
    USE SIGNAL ;
    PORT
      LAYER M3 ;
        RECT  41.292 0 41.31 0.037 ;
    END
  END t_k[369]
  PIN t_k[36]
    DIRECTION OUTPUT ;
    USE SIGNAL ;
    PORT
      LAYER M5 ;
        RECT  41.52 0 41.544 0.084 ;
    END
  END t_k[36]
  PIN t_k[370]
    DIRECTION OUTPUT ;
    USE SIGNAL ;
    PORT
      LAYER M3 ;
        RECT  41.364 0 41.382 0.037 ;
    END
  END t_k[370]
  PIN t_k[371]
    DIRECTION OUTPUT ;
    USE SIGNAL ;
    PORT
      LAYER M3 ;
        RECT  41.436 0 41.454 0.037 ;
    END
  END t_k[371]
  PIN t_k[372]
    DIRECTION OUTPUT ;
    USE SIGNAL ;
    PORT
      LAYER M3 ;
        RECT  41.508 0 41.526 0.037 ;
    END
  END t_k[372]
  PIN t_k[373]
    DIRECTION OUTPUT ;
    USE SIGNAL ;
    PORT
      LAYER M3 ;
        RECT  41.58 0 41.598 0.037 ;
    END
  END t_k[373]
  PIN t_k[374]
    DIRECTION OUTPUT ;
    USE SIGNAL ;
    PORT
      LAYER M3 ;
        RECT  41.652 0 41.67 0.037 ;
    END
  END t_k[374]
  PIN t_k[375]
    DIRECTION OUTPUT ;
    USE SIGNAL ;
    PORT
      LAYER M3 ;
        RECT  41.724 0 41.742 0.037 ;
    END
  END t_k[375]
  PIN t_k[376]
    DIRECTION OUTPUT ;
    USE SIGNAL ;
    PORT
      LAYER M3 ;
        RECT  41.796 0 41.814 0.037 ;
    END
  END t_k[376]
  PIN t_k[377]
    DIRECTION OUTPUT ;
    USE SIGNAL ;
    PORT
      LAYER M3 ;
        RECT  41.868 0 41.886 0.037 ;
    END
  END t_k[377]
  PIN t_k[378]
    DIRECTION OUTPUT ;
    USE SIGNAL ;
    PORT
      LAYER M3 ;
        RECT  41.94 0 41.958 0.037 ;
    END
  END t_k[378]
  PIN t_k[379]
    DIRECTION OUTPUT ;
    USE SIGNAL ;
    PORT
      LAYER M3 ;
        RECT  42.012 0 42.03 0.037 ;
    END
  END t_k[379]
  PIN t_k[37]
    DIRECTION OUTPUT ;
    USE SIGNAL ;
    PORT
      LAYER M5 ;
        RECT  41.616 0 41.64 0.084 ;
    END
  END t_k[37]
  PIN t_k[380]
    DIRECTION OUTPUT ;
    USE SIGNAL ;
    PORT
      LAYER M3 ;
        RECT  42.084 0 42.102 0.037 ;
    END
  END t_k[380]
  PIN t_k[381]
    DIRECTION OUTPUT ;
    USE SIGNAL ;
    PORT
      LAYER M3 ;
        RECT  42.156 0 42.174 0.037 ;
    END
  END t_k[381]
  PIN t_k[382]
    DIRECTION OUTPUT ;
    USE SIGNAL ;
    PORT
      LAYER M3 ;
        RECT  42.228 0 42.246 0.037 ;
    END
  END t_k[382]
  PIN t_k[383]
    DIRECTION OUTPUT ;
    USE SIGNAL ;
    PORT
      LAYER M3 ;
        RECT  42.3 0 42.318 0.037 ;
    END
  END t_k[383]
  PIN t_k[384]
    DIRECTION OUTPUT ;
    USE SIGNAL ;
    PORT
      LAYER M3 ;
        RECT  42.372 0 42.39 0.037 ;
    END
  END t_k[384]
  PIN t_k[385]
    DIRECTION OUTPUT ;
    USE SIGNAL ;
    PORT
      LAYER M3 ;
        RECT  42.444 0 42.462 0.037 ;
    END
  END t_k[385]
  PIN t_k[386]
    DIRECTION OUTPUT ;
    USE SIGNAL ;
    PORT
      LAYER M3 ;
        RECT  42.516 0 42.534 0.037 ;
    END
  END t_k[386]
  PIN t_k[387]
    DIRECTION OUTPUT ;
    USE SIGNAL ;
    PORT
      LAYER M3 ;
        RECT  42.588 0 42.606 0.037 ;
    END
  END t_k[387]
  PIN t_k[388]
    DIRECTION OUTPUT ;
    USE SIGNAL ;
    PORT
      LAYER M3 ;
        RECT  42.66 0 42.678 0.037 ;
    END
  END t_k[388]
  PIN t_k[389]
    DIRECTION OUTPUT ;
    USE SIGNAL ;
    PORT
      LAYER M3 ;
        RECT  42.732 0 42.75 0.037 ;
    END
  END t_k[389]
  PIN t_k[38]
    DIRECTION OUTPUT ;
    USE SIGNAL ;
    PORT
      LAYER M5 ;
        RECT  41.712 0 41.736 0.084 ;
    END
  END t_k[38]
  PIN t_k[390]
    DIRECTION OUTPUT ;
    USE SIGNAL ;
    PORT
      LAYER M3 ;
        RECT  42.804 0 42.822 0.037 ;
    END
  END t_k[390]
  PIN t_k[391]
    DIRECTION OUTPUT ;
    USE SIGNAL ;
    PORT
      LAYER M3 ;
        RECT  42.876 0 42.894 0.037 ;
    END
  END t_k[391]
  PIN t_k[392]
    DIRECTION OUTPUT ;
    USE SIGNAL ;
    PORT
      LAYER M3 ;
        RECT  42.948 0 42.966 0.037 ;
    END
  END t_k[392]
  PIN t_k[393]
    DIRECTION OUTPUT ;
    USE SIGNAL ;
    PORT
      LAYER M3 ;
        RECT  43.02 0 43.038 0.037 ;
    END
  END t_k[393]
  PIN t_k[394]
    DIRECTION OUTPUT ;
    USE SIGNAL ;
    PORT
      LAYER M3 ;
        RECT  43.092 0 43.11 0.037 ;
    END
  END t_k[394]
  PIN t_k[395]
    DIRECTION OUTPUT ;
    USE SIGNAL ;
    PORT
      LAYER M5 ;
        RECT  26.064 0 26.088 0.084 ;
    END
  END t_k[395]
  PIN t_k[396]
    DIRECTION OUTPUT ;
    USE SIGNAL ;
    PORT
      LAYER M5 ;
        RECT  26.16 0 26.184 0.084 ;
    END
  END t_k[396]
  PIN t_k[397]
    DIRECTION OUTPUT ;
    USE SIGNAL ;
    PORT
      LAYER M5 ;
        RECT  26.256 0 26.28 0.084 ;
    END
  END t_k[397]
  PIN t_k[398]
    DIRECTION OUTPUT ;
    USE SIGNAL ;
    PORT
      LAYER M5 ;
        RECT  26.352 0 26.376 0.084 ;
    END
  END t_k[398]
  PIN t_k[399]
    DIRECTION OUTPUT ;
    USE SIGNAL ;
    PORT
      LAYER M5 ;
        RECT  26.448 0 26.472 0.084 ;
    END
  END t_k[399]
  PIN t_k[39]
    DIRECTION OUTPUT ;
    USE SIGNAL ;
    PORT
      LAYER M5 ;
        RECT  41.808 0 41.832 0.084 ;
    END
  END t_k[39]
  PIN t_k[3]
    DIRECTION OUTPUT ;
    USE SIGNAL ;
    PORT
      LAYER M3 ;
        RECT  31.068 0 31.086 0.037 ;
    END
  END t_k[3]
  PIN t_k[400]
    DIRECTION OUTPUT ;
    USE SIGNAL ;
    PORT
      LAYER M5 ;
        RECT  26.544 0 26.568 0.084 ;
    END
  END t_k[400]
  PIN t_k[401]
    DIRECTION OUTPUT ;
    USE SIGNAL ;
    PORT
      LAYER M5 ;
        RECT  26.64 0 26.664 0.084 ;
    END
  END t_k[401]
  PIN t_k[402]
    DIRECTION OUTPUT ;
    USE SIGNAL ;
    PORT
      LAYER M5 ;
        RECT  26.736 0 26.76 0.084 ;
    END
  END t_k[402]
  PIN t_k[403]
    DIRECTION OUTPUT ;
    USE SIGNAL ;
    PORT
      LAYER M5 ;
        RECT  26.832 0 26.856 0.084 ;
    END
  END t_k[403]
  PIN t_k[404]
    DIRECTION OUTPUT ;
    USE SIGNAL ;
    PORT
      LAYER M5 ;
        RECT  26.928 0 26.952 0.084 ;
    END
  END t_k[404]
  PIN t_k[405]
    DIRECTION OUTPUT ;
    USE SIGNAL ;
    PORT
      LAYER M5 ;
        RECT  27.024 0 27.048 0.084 ;
    END
  END t_k[405]
  PIN t_k[406]
    DIRECTION OUTPUT ;
    USE SIGNAL ;
    PORT
      LAYER M5 ;
        RECT  27.12 0 27.144 0.084 ;
    END
  END t_k[406]
  PIN t_k[407]
    DIRECTION OUTPUT ;
    USE SIGNAL ;
    PORT
      LAYER M5 ;
        RECT  27.216 0 27.24 0.084 ;
    END
  END t_k[407]
  PIN t_k[408]
    DIRECTION OUTPUT ;
    USE SIGNAL ;
    PORT
      LAYER M5 ;
        RECT  27.312 0 27.336 0.084 ;
    END
  END t_k[408]
  PIN t_k[409]
    DIRECTION OUTPUT ;
    USE SIGNAL ;
    PORT
      LAYER M5 ;
        RECT  27.408 0 27.432 0.084 ;
    END
  END t_k[409]
  PIN t_k[40]
    DIRECTION OUTPUT ;
    USE SIGNAL ;
    PORT
      LAYER M5 ;
        RECT  41.904 0 41.928 0.084 ;
    END
  END t_k[40]
  PIN t_k[410]
    DIRECTION OUTPUT ;
    USE SIGNAL ;
    PORT
      LAYER M5 ;
        RECT  27.504 0 27.528 0.084 ;
    END
  END t_k[410]
  PIN t_k[411]
    DIRECTION OUTPUT ;
    USE SIGNAL ;
    PORT
      LAYER M5 ;
        RECT  27.6 0 27.624 0.084 ;
    END
  END t_k[411]
  PIN t_k[412]
    DIRECTION OUTPUT ;
    USE SIGNAL ;
    PORT
      LAYER M5 ;
        RECT  27.696 0 27.72 0.084 ;
    END
  END t_k[412]
  PIN t_k[413]
    DIRECTION OUTPUT ;
    USE SIGNAL ;
    PORT
      LAYER M5 ;
        RECT  27.792 0 27.816 0.084 ;
    END
  END t_k[413]
  PIN t_k[414]
    DIRECTION OUTPUT ;
    USE SIGNAL ;
    PORT
      LAYER M5 ;
        RECT  27.888 0 27.912 0.084 ;
    END
  END t_k[414]
  PIN t_k[415]
    DIRECTION OUTPUT ;
    USE SIGNAL ;
    PORT
      LAYER M5 ;
        RECT  27.984 0 28.008 0.084 ;
    END
  END t_k[415]
  PIN t_k[416]
    DIRECTION OUTPUT ;
    USE SIGNAL ;
    PORT
      LAYER M5 ;
        RECT  28.08 0 28.104 0.084 ;
    END
  END t_k[416]
  PIN t_k[417]
    DIRECTION OUTPUT ;
    USE SIGNAL ;
    PORT
      LAYER M5 ;
        RECT  28.176 0 28.2 0.084 ;
    END
  END t_k[417]
  PIN t_k[418]
    DIRECTION OUTPUT ;
    USE SIGNAL ;
    PORT
      LAYER M5 ;
        RECT  28.272 0 28.296 0.084 ;
    END
  END t_k[418]
  PIN t_k[419]
    DIRECTION OUTPUT ;
    USE SIGNAL ;
    PORT
      LAYER M5 ;
        RECT  28.368 0 28.392 0.084 ;
    END
  END t_k[419]
  PIN t_k[41]
    DIRECTION OUTPUT ;
    USE SIGNAL ;
    PORT
      LAYER M5 ;
        RECT  42 0 42.024 0.084 ;
    END
  END t_k[41]
  PIN t_k[420]
    DIRECTION OUTPUT ;
    USE SIGNAL ;
    PORT
      LAYER M5 ;
        RECT  28.464 0 28.488 0.084 ;
    END
  END t_k[420]
  PIN t_k[421]
    DIRECTION OUTPUT ;
    USE SIGNAL ;
    PORT
      LAYER M5 ;
        RECT  28.56 0 28.584 0.084 ;
    END
  END t_k[421]
  PIN t_k[422]
    DIRECTION OUTPUT ;
    USE SIGNAL ;
    PORT
      LAYER M5 ;
        RECT  28.656 0 28.68 0.084 ;
    END
  END t_k[422]
  PIN t_k[423]
    DIRECTION OUTPUT ;
    USE SIGNAL ;
    PORT
      LAYER M5 ;
        RECT  28.752 0 28.776 0.084 ;
    END
  END t_k[423]
  PIN t_k[424]
    DIRECTION OUTPUT ;
    USE SIGNAL ;
    PORT
      LAYER M5 ;
        RECT  28.848 0 28.872 0.084 ;
    END
  END t_k[424]
  PIN t_k[425]
    DIRECTION OUTPUT ;
    USE SIGNAL ;
    PORT
      LAYER M5 ;
        RECT  28.944 0 28.968 0.084 ;
    END
  END t_k[425]
  PIN t_k[426]
    DIRECTION OUTPUT ;
    USE SIGNAL ;
    PORT
      LAYER M5 ;
        RECT  29.04 0 29.064 0.084 ;
    END
  END t_k[426]
  PIN t_k[427]
    DIRECTION OUTPUT ;
    USE SIGNAL ;
    PORT
      LAYER M3 ;
        RECT  65.052 0 65.07 0.037 ;
    END
  END t_k[427]
  PIN t_k[428]
    DIRECTION OUTPUT ;
    USE SIGNAL ;
    PORT
      LAYER M3 ;
        RECT  65.124 0 65.142 0.037 ;
    END
  END t_k[428]
  PIN t_k[429]
    DIRECTION OUTPUT ;
    USE SIGNAL ;
    PORT
      LAYER M3 ;
        RECT  65.196 0 65.214 0.037 ;
    END
  END t_k[429]
  PIN t_k[42]
    DIRECTION OUTPUT ;
    USE SIGNAL ;
    PORT
      LAYER M5 ;
        RECT  42.096 0 42.12 0.084 ;
    END
  END t_k[42]
  PIN t_k[430]
    DIRECTION OUTPUT ;
    USE SIGNAL ;
    PORT
      LAYER M3 ;
        RECT  65.268 0 65.286 0.037 ;
    END
  END t_k[430]
  PIN t_k[431]
    DIRECTION OUTPUT ;
    USE SIGNAL ;
    PORT
      LAYER M3 ;
        RECT  65.34 0 65.358 0.037 ;
    END
  END t_k[431]
  PIN t_k[432]
    DIRECTION OUTPUT ;
    USE SIGNAL ;
    PORT
      LAYER M3 ;
        RECT  65.412 0 65.43 0.037 ;
    END
  END t_k[432]
  PIN t_k[433]
    DIRECTION OUTPUT ;
    USE SIGNAL ;
    PORT
      LAYER M3 ;
        RECT  65.484 0 65.502 0.037 ;
    END
  END t_k[433]
  PIN t_k[434]
    DIRECTION OUTPUT ;
    USE SIGNAL ;
    PORT
      LAYER M3 ;
        RECT  65.556 0 65.574 0.037 ;
    END
  END t_k[434]
  PIN t_k[435]
    DIRECTION OUTPUT ;
    USE SIGNAL ;
    PORT
      LAYER M3 ;
        RECT  65.628 0 65.646 0.037 ;
    END
  END t_k[435]
  PIN t_k[436]
    DIRECTION OUTPUT ;
    USE SIGNAL ;
    PORT
      LAYER M3 ;
        RECT  65.7 0 65.718 0.037 ;
    END
  END t_k[436]
  PIN t_k[437]
    DIRECTION OUTPUT ;
    USE SIGNAL ;
    PORT
      LAYER M3 ;
        RECT  65.772 0 65.79 0.037 ;
    END
  END t_k[437]
  PIN t_k[438]
    DIRECTION OUTPUT ;
    USE SIGNAL ;
    PORT
      LAYER M3 ;
        RECT  65.844 0 65.862 0.037 ;
    END
  END t_k[438]
  PIN t_k[439]
    DIRECTION OUTPUT ;
    USE SIGNAL ;
    PORT
      LAYER M3 ;
        RECT  65.916 0 65.934 0.037 ;
    END
  END t_k[439]
  PIN t_k[43]
    DIRECTION OUTPUT ;
    USE SIGNAL ;
    PORT
      LAYER M5 ;
        RECT  54.48 0 54.504 0.084 ;
    END
  END t_k[43]
  PIN t_k[440]
    DIRECTION OUTPUT ;
    USE SIGNAL ;
    PORT
      LAYER M3 ;
        RECT  65.988 0 66.006 0.037 ;
    END
  END t_k[440]
  PIN t_k[441]
    DIRECTION OUTPUT ;
    USE SIGNAL ;
    PORT
      LAYER M3 ;
        RECT  66.06 0 66.078 0.037 ;
    END
  END t_k[441]
  PIN t_k[442]
    DIRECTION OUTPUT ;
    USE SIGNAL ;
    PORT
      LAYER M3 ;
        RECT  66.132 0 66.15 0.037 ;
    END
  END t_k[442]
  PIN t_k[443]
    DIRECTION OUTPUT ;
    USE SIGNAL ;
    PORT
      LAYER M3 ;
        RECT  66.204 0 66.222 0.037 ;
    END
  END t_k[443]
  PIN t_k[444]
    DIRECTION OUTPUT ;
    USE SIGNAL ;
    PORT
      LAYER M3 ;
        RECT  66.276 0 66.294 0.037 ;
    END
  END t_k[444]
  PIN t_k[445]
    DIRECTION OUTPUT ;
    USE SIGNAL ;
    PORT
      LAYER M3 ;
        RECT  66.348 0 66.366 0.037 ;
    END
  END t_k[445]
  PIN t_k[446]
    DIRECTION OUTPUT ;
    USE SIGNAL ;
    PORT
      LAYER M3 ;
        RECT  66.42 0 66.438 0.037 ;
    END
  END t_k[446]
  PIN t_k[447]
    DIRECTION OUTPUT ;
    USE SIGNAL ;
    PORT
      LAYER M3 ;
        RECT  66.492 0 66.51 0.037 ;
    END
  END t_k[447]
  PIN t_k[448]
    DIRECTION OUTPUT ;
    USE SIGNAL ;
    PORT
      LAYER M3 ;
        RECT  66.564 0 66.582 0.037 ;
    END
  END t_k[448]
  PIN t_k[449]
    DIRECTION OUTPUT ;
    USE SIGNAL ;
    PORT
      LAYER M3 ;
        RECT  66.636 0 66.654 0.037 ;
    END
  END t_k[449]
  PIN t_k[44]
    DIRECTION OUTPUT ;
    USE SIGNAL ;
    PORT
      LAYER M5 ;
        RECT  54.576 0 54.6 0.084 ;
    END
  END t_k[44]
  PIN t_k[450]
    DIRECTION OUTPUT ;
    USE SIGNAL ;
    PORT
      LAYER M3 ;
        RECT  66.708 0 66.726 0.037 ;
    END
  END t_k[450]
  PIN t_k[451]
    DIRECTION OUTPUT ;
    USE SIGNAL ;
    PORT
      LAYER M3 ;
        RECT  66.78 0 66.798 0.037 ;
    END
  END t_k[451]
  PIN t_k[452]
    DIRECTION OUTPUT ;
    USE SIGNAL ;
    PORT
      LAYER M3 ;
        RECT  66.852 0 66.87 0.037 ;
    END
  END t_k[452]
  PIN t_k[453]
    DIRECTION OUTPUT ;
    USE SIGNAL ;
    PORT
      LAYER M3 ;
        RECT  66.924 0 66.942 0.037 ;
    END
  END t_k[453]
  PIN t_k[454]
    DIRECTION OUTPUT ;
    USE SIGNAL ;
    PORT
      LAYER M3 ;
        RECT  66.996 0 67.014 0.037 ;
    END
  END t_k[454]
  PIN t_k[455]
    DIRECTION OUTPUT ;
    USE SIGNAL ;
    PORT
      LAYER M3 ;
        RECT  67.068 0 67.086 0.037 ;
    END
  END t_k[455]
  PIN t_k[456]
    DIRECTION OUTPUT ;
    USE SIGNAL ;
    PORT
      LAYER M3 ;
        RECT  67.14 0 67.158 0.037 ;
    END
  END t_k[456]
  PIN t_k[457]
    DIRECTION OUTPUT ;
    USE SIGNAL ;
    PORT
      LAYER M3 ;
        RECT  67.212 0 67.23 0.037 ;
    END
  END t_k[457]
  PIN t_k[458]
    DIRECTION OUTPUT ;
    USE SIGNAL ;
    PORT
      LAYER M3 ;
        RECT  67.284 0 67.302 0.037 ;
    END
  END t_k[458]
  PIN t_k[459]
    DIRECTION OUTPUT ;
    USE SIGNAL ;
    PORT
      LAYER M3 ;
        RECT  58.14 0 58.158 0.037 ;
    END
  END t_k[459]
  PIN t_k[45]
    DIRECTION OUTPUT ;
    USE SIGNAL ;
    PORT
      LAYER M5 ;
        RECT  54.672 0 54.696 0.084 ;
    END
  END t_k[45]
  PIN t_k[460]
    DIRECTION OUTPUT ;
    USE SIGNAL ;
    PORT
      LAYER M3 ;
        RECT  58.212 0 58.23 0.037 ;
    END
  END t_k[460]
  PIN t_k[461]
    DIRECTION OUTPUT ;
    USE SIGNAL ;
    PORT
      LAYER M3 ;
        RECT  58.284 0 58.302 0.037 ;
    END
  END t_k[461]
  PIN t_k[462]
    DIRECTION OUTPUT ;
    USE SIGNAL ;
    PORT
      LAYER M3 ;
        RECT  58.356 0 58.374 0.037 ;
    END
  END t_k[462]
  PIN t_k[463]
    DIRECTION OUTPUT ;
    USE SIGNAL ;
    PORT
      LAYER M3 ;
        RECT  58.428 0 58.446 0.037 ;
    END
  END t_k[463]
  PIN t_k[464]
    DIRECTION OUTPUT ;
    USE SIGNAL ;
    PORT
      LAYER M3 ;
        RECT  58.5 0 58.518 0.037 ;
    END
  END t_k[464]
  PIN t_k[465]
    DIRECTION OUTPUT ;
    USE SIGNAL ;
    PORT
      LAYER M3 ;
        RECT  58.572 0 58.59 0.037 ;
    END
  END t_k[465]
  PIN t_k[466]
    DIRECTION OUTPUT ;
    USE SIGNAL ;
    PORT
      LAYER M3 ;
        RECT  58.644 0 58.662 0.037 ;
    END
  END t_k[466]
  PIN t_k[467]
    DIRECTION OUTPUT ;
    USE SIGNAL ;
    PORT
      LAYER M3 ;
        RECT  58.716 0 58.734 0.037 ;
    END
  END t_k[467]
  PIN t_k[468]
    DIRECTION OUTPUT ;
    USE SIGNAL ;
    PORT
      LAYER M3 ;
        RECT  58.788 0 58.806 0.037 ;
    END
  END t_k[468]
  PIN t_k[469]
    DIRECTION OUTPUT ;
    USE SIGNAL ;
    PORT
      LAYER M3 ;
        RECT  58.86 0 58.878 0.037 ;
    END
  END t_k[469]
  PIN t_k[46]
    DIRECTION OUTPUT ;
    USE SIGNAL ;
    PORT
      LAYER M5 ;
        RECT  54.768 0 54.792 0.084 ;
    END
  END t_k[46]
  PIN t_k[470]
    DIRECTION OUTPUT ;
    USE SIGNAL ;
    PORT
      LAYER M3 ;
        RECT  58.932 0 58.95 0.037 ;
    END
  END t_k[470]
  PIN t_k[471]
    DIRECTION OUTPUT ;
    USE SIGNAL ;
    PORT
      LAYER M3 ;
        RECT  59.004 0 59.022 0.037 ;
    END
  END t_k[471]
  PIN t_k[472]
    DIRECTION OUTPUT ;
    USE SIGNAL ;
    PORT
      LAYER M3 ;
        RECT  59.076 0 59.094 0.037 ;
    END
  END t_k[472]
  PIN t_k[473]
    DIRECTION OUTPUT ;
    USE SIGNAL ;
    PORT
      LAYER M3 ;
        RECT  59.148 0 59.166 0.037 ;
    END
  END t_k[473]
  PIN t_k[474]
    DIRECTION OUTPUT ;
    USE SIGNAL ;
    PORT
      LAYER M3 ;
        RECT  59.22 0 59.238 0.037 ;
    END
  END t_k[474]
  PIN t_k[475]
    DIRECTION OUTPUT ;
    USE SIGNAL ;
    PORT
      LAYER M3 ;
        RECT  59.292 0 59.31 0.037 ;
    END
  END t_k[475]
  PIN t_k[476]
    DIRECTION OUTPUT ;
    USE SIGNAL ;
    PORT
      LAYER M3 ;
        RECT  59.364 0 59.382 0.037 ;
    END
  END t_k[476]
  PIN t_k[477]
    DIRECTION OUTPUT ;
    USE SIGNAL ;
    PORT
      LAYER M3 ;
        RECT  59.436 0 59.454 0.037 ;
    END
  END t_k[477]
  PIN t_k[478]
    DIRECTION OUTPUT ;
    USE SIGNAL ;
    PORT
      LAYER M3 ;
        RECT  59.508 0 59.526 0.037 ;
    END
  END t_k[478]
  PIN t_k[479]
    DIRECTION OUTPUT ;
    USE SIGNAL ;
    PORT
      LAYER M3 ;
        RECT  59.58 0 59.598 0.037 ;
    END
  END t_k[479]
  PIN t_k[47]
    DIRECTION OUTPUT ;
    USE SIGNAL ;
    PORT
      LAYER M5 ;
        RECT  54.864 0 54.888 0.084 ;
    END
  END t_k[47]
  PIN t_k[480]
    DIRECTION OUTPUT ;
    USE SIGNAL ;
    PORT
      LAYER M3 ;
        RECT  59.652 0 59.67 0.037 ;
    END
  END t_k[480]
  PIN t_k[481]
    DIRECTION OUTPUT ;
    USE SIGNAL ;
    PORT
      LAYER M3 ;
        RECT  59.724 0 59.742 0.037 ;
    END
  END t_k[481]
  PIN t_k[482]
    DIRECTION OUTPUT ;
    USE SIGNAL ;
    PORT
      LAYER M3 ;
        RECT  59.796 0 59.814 0.037 ;
    END
  END t_k[482]
  PIN t_k[483]
    DIRECTION OUTPUT ;
    USE SIGNAL ;
    PORT
      LAYER M3 ;
        RECT  59.868 0 59.886 0.037 ;
    END
  END t_k[483]
  PIN t_k[484]
    DIRECTION OUTPUT ;
    USE SIGNAL ;
    PORT
      LAYER M3 ;
        RECT  59.94 0 59.958 0.037 ;
    END
  END t_k[484]
  PIN t_k[485]
    DIRECTION OUTPUT ;
    USE SIGNAL ;
    PORT
      LAYER M3 ;
        RECT  60.012 0 60.03 0.037 ;
    END
  END t_k[485]
  PIN t_k[486]
    DIRECTION OUTPUT ;
    USE SIGNAL ;
    PORT
      LAYER M3 ;
        RECT  60.084 0 60.102 0.037 ;
    END
  END t_k[486]
  PIN t_k[487]
    DIRECTION OUTPUT ;
    USE SIGNAL ;
    PORT
      LAYER M3 ;
        RECT  60.156 0 60.174 0.037 ;
    END
  END t_k[487]
  PIN t_k[488]
    DIRECTION OUTPUT ;
    USE SIGNAL ;
    PORT
      LAYER M3 ;
        RECT  60.228 0 60.246 0.037 ;
    END
  END t_k[488]
  PIN t_k[489]
    DIRECTION OUTPUT ;
    USE SIGNAL ;
    PORT
      LAYER M3 ;
        RECT  60.3 0 60.318 0.037 ;
    END
  END t_k[489]
  PIN t_k[48]
    DIRECTION OUTPUT ;
    USE SIGNAL ;
    PORT
      LAYER M5 ;
        RECT  54.96 0 54.984 0.084 ;
    END
  END t_k[48]
  PIN t_k[490]
    DIRECTION OUTPUT ;
    USE SIGNAL ;
    PORT
      LAYER M3 ;
        RECT  60.372 0 60.39 0.037 ;
    END
  END t_k[490]
  PIN t_k[491]
    DIRECTION OUTPUT ;
    USE SIGNAL ;
    PORT
      LAYER M5 ;
        RECT  32.208 0 32.232 0.084 ;
    END
  END t_k[491]
  PIN t_k[492]
    DIRECTION OUTPUT ;
    USE SIGNAL ;
    PORT
      LAYER M5 ;
        RECT  32.304 0 32.328 0.084 ;
    END
  END t_k[492]
  PIN t_k[493]
    DIRECTION OUTPUT ;
    USE SIGNAL ;
    PORT
      LAYER M5 ;
        RECT  32.4 0 32.424 0.084 ;
    END
  END t_k[493]
  PIN t_k[494]
    DIRECTION OUTPUT ;
    USE SIGNAL ;
    PORT
      LAYER M5 ;
        RECT  32.496 0 32.52 0.084 ;
    END
  END t_k[494]
  PIN t_k[495]
    DIRECTION OUTPUT ;
    USE SIGNAL ;
    PORT
      LAYER M5 ;
        RECT  32.592 0 32.616 0.084 ;
    END
  END t_k[495]
  PIN t_k[496]
    DIRECTION OUTPUT ;
    USE SIGNAL ;
    PORT
      LAYER M5 ;
        RECT  32.688 0 32.712 0.084 ;
    END
  END t_k[496]
  PIN t_k[497]
    DIRECTION OUTPUT ;
    USE SIGNAL ;
    PORT
      LAYER M5 ;
        RECT  32.784 0 32.808 0.084 ;
    END
  END t_k[497]
  PIN t_k[498]
    DIRECTION OUTPUT ;
    USE SIGNAL ;
    PORT
      LAYER M5 ;
        RECT  32.88 0 32.904 0.084 ;
    END
  END t_k[498]
  PIN t_k[499]
    DIRECTION OUTPUT ;
    USE SIGNAL ;
    PORT
      LAYER M5 ;
        RECT  32.976 0 33 0.084 ;
    END
  END t_k[499]
  PIN t_k[49]
    DIRECTION OUTPUT ;
    USE SIGNAL ;
    PORT
      LAYER M5 ;
        RECT  55.056 0 55.08 0.084 ;
    END
  END t_k[49]
  PIN t_k[4]
    DIRECTION OUTPUT ;
    USE SIGNAL ;
    PORT
      LAYER M3 ;
        RECT  31.14 0 31.158 0.037 ;
    END
  END t_k[4]
  PIN t_k[500]
    DIRECTION OUTPUT ;
    USE SIGNAL ;
    PORT
      LAYER M5 ;
        RECT  33.072 0 33.096 0.084 ;
    END
  END t_k[500]
  PIN t_k[501]
    DIRECTION OUTPUT ;
    USE SIGNAL ;
    PORT
      LAYER M5 ;
        RECT  33.168 0 33.192 0.084 ;
    END
  END t_k[501]
  PIN t_k[502]
    DIRECTION OUTPUT ;
    USE SIGNAL ;
    PORT
      LAYER M5 ;
        RECT  33.264 0 33.288 0.084 ;
    END
  END t_k[502]
  PIN t_k[503]
    DIRECTION OUTPUT ;
    USE SIGNAL ;
    PORT
      LAYER M5 ;
        RECT  33.36 0 33.384 0.084 ;
    END
  END t_k[503]
  PIN t_k[504]
    DIRECTION OUTPUT ;
    USE SIGNAL ;
    PORT
      LAYER M5 ;
        RECT  33.456 0 33.48 0.084 ;
    END
  END t_k[504]
  PIN t_k[505]
    DIRECTION OUTPUT ;
    USE SIGNAL ;
    PORT
      LAYER M5 ;
        RECT  33.552 0 33.576 0.084 ;
    END
  END t_k[505]
  PIN t_k[506]
    DIRECTION OUTPUT ;
    USE SIGNAL ;
    PORT
      LAYER M5 ;
        RECT  33.648 0 33.672 0.084 ;
    END
  END t_k[506]
  PIN t_k[507]
    DIRECTION OUTPUT ;
    USE SIGNAL ;
    PORT
      LAYER M5 ;
        RECT  33.744 0 33.768 0.084 ;
    END
  END t_k[507]
  PIN t_k[508]
    DIRECTION OUTPUT ;
    USE SIGNAL ;
    PORT
      LAYER M5 ;
        RECT  33.84 0 33.864 0.084 ;
    END
  END t_k[508]
  PIN t_k[509]
    DIRECTION OUTPUT ;
    USE SIGNAL ;
    PORT
      LAYER M5 ;
        RECT  33.936 0 33.96 0.084 ;
    END
  END t_k[509]
  PIN t_k[50]
    DIRECTION OUTPUT ;
    USE SIGNAL ;
    PORT
      LAYER M5 ;
        RECT  55.152 0 55.176 0.084 ;
    END
  END t_k[50]
  PIN t_k[510]
    DIRECTION OUTPUT ;
    USE SIGNAL ;
    PORT
      LAYER M5 ;
        RECT  34.032 0 34.056 0.084 ;
    END
  END t_k[510]
  PIN t_k[511]
    DIRECTION OUTPUT ;
    USE SIGNAL ;
    PORT
      LAYER M5 ;
        RECT  34.128 0 34.152 0.084 ;
    END
  END t_k[511]
  PIN t_k[512]
    DIRECTION OUTPUT ;
    USE SIGNAL ;
    PORT
      LAYER M5 ;
        RECT  34.224 0 34.248 0.084 ;
    END
  END t_k[512]
  PIN t_k[513]
    DIRECTION OUTPUT ;
    USE SIGNAL ;
    PORT
      LAYER M5 ;
        RECT  34.32 0 34.344 0.084 ;
    END
  END t_k[513]
  PIN t_k[514]
    DIRECTION OUTPUT ;
    USE SIGNAL ;
    PORT
      LAYER M5 ;
        RECT  34.416 0 34.44 0.084 ;
    END
  END t_k[514]
  PIN t_k[515]
    DIRECTION OUTPUT ;
    USE SIGNAL ;
    PORT
      LAYER M5 ;
        RECT  34.512 0 34.536 0.084 ;
    END
  END t_k[515]
  PIN t_k[516]
    DIRECTION OUTPUT ;
    USE SIGNAL ;
    PORT
      LAYER M5 ;
        RECT  34.608 0 34.632 0.084 ;
    END
  END t_k[516]
  PIN t_k[517]
    DIRECTION OUTPUT ;
    USE SIGNAL ;
    PORT
      LAYER M5 ;
        RECT  34.704 0 34.728 0.084 ;
    END
  END t_k[517]
  PIN t_k[518]
    DIRECTION OUTPUT ;
    USE SIGNAL ;
    PORT
      LAYER M5 ;
        RECT  34.8 0 34.824 0.084 ;
    END
  END t_k[518]
  PIN t_k[519]
    DIRECTION OUTPUT ;
    USE SIGNAL ;
    PORT
      LAYER M5 ;
        RECT  34.896 0 34.92 0.084 ;
    END
  END t_k[519]
  PIN t_k[51]
    DIRECTION OUTPUT ;
    USE SIGNAL ;
    PORT
      LAYER M5 ;
        RECT  55.248 0 55.272 0.084 ;
    END
  END t_k[51]
  PIN t_k[520]
    DIRECTION OUTPUT ;
    USE SIGNAL ;
    PORT
      LAYER M5 ;
        RECT  34.992 0 35.016 0.084 ;
    END
  END t_k[520]
  PIN t_k[521]
    DIRECTION OUTPUT ;
    USE SIGNAL ;
    PORT
      LAYER M5 ;
        RECT  35.088 0 35.112 0.084 ;
    END
  END t_k[521]
  PIN t_k[522]
    DIRECTION OUTPUT ;
    USE SIGNAL ;
    PORT
      LAYER M5 ;
        RECT  35.184 0 35.208 0.084 ;
    END
  END t_k[522]
  PIN t_k[523]
    DIRECTION OUTPUT ;
    USE SIGNAL ;
    PORT
      LAYER M3 ;
        RECT  62.748 0 62.766 0.037 ;
    END
  END t_k[523]
  PIN t_k[524]
    DIRECTION OUTPUT ;
    USE SIGNAL ;
    PORT
      LAYER M3 ;
        RECT  62.82 0 62.838 0.037 ;
    END
  END t_k[524]
  PIN t_k[525]
    DIRECTION OUTPUT ;
    USE SIGNAL ;
    PORT
      LAYER M3 ;
        RECT  62.892 0 62.91 0.037 ;
    END
  END t_k[525]
  PIN t_k[526]
    DIRECTION OUTPUT ;
    USE SIGNAL ;
    PORT
      LAYER M3 ;
        RECT  62.964 0 62.982 0.037 ;
    END
  END t_k[526]
  PIN t_k[527]
    DIRECTION OUTPUT ;
    USE SIGNAL ;
    PORT
      LAYER M3 ;
        RECT  63.036 0 63.054 0.037 ;
    END
  END t_k[527]
  PIN t_k[528]
    DIRECTION OUTPUT ;
    USE SIGNAL ;
    PORT
      LAYER M3 ;
        RECT  63.108 0 63.126 0.037 ;
    END
  END t_k[528]
  PIN t_k[529]
    DIRECTION OUTPUT ;
    USE SIGNAL ;
    PORT
      LAYER M3 ;
        RECT  63.18 0 63.198 0.037 ;
    END
  END t_k[529]
  PIN t_k[52]
    DIRECTION OUTPUT ;
    USE SIGNAL ;
    PORT
      LAYER M5 ;
        RECT  55.344 0 55.368 0.084 ;
    END
  END t_k[52]
  PIN t_k[530]
    DIRECTION OUTPUT ;
    USE SIGNAL ;
    PORT
      LAYER M3 ;
        RECT  63.252 0 63.27 0.037 ;
    END
  END t_k[530]
  PIN t_k[531]
    DIRECTION OUTPUT ;
    USE SIGNAL ;
    PORT
      LAYER M3 ;
        RECT  63.324 0 63.342 0.037 ;
    END
  END t_k[531]
  PIN t_k[532]
    DIRECTION OUTPUT ;
    USE SIGNAL ;
    PORT
      LAYER M3 ;
        RECT  63.396 0 63.414 0.037 ;
    END
  END t_k[532]
  PIN t_k[533]
    DIRECTION OUTPUT ;
    USE SIGNAL ;
    PORT
      LAYER M3 ;
        RECT  63.468 0 63.486 0.037 ;
    END
  END t_k[533]
  PIN t_k[534]
    DIRECTION OUTPUT ;
    USE SIGNAL ;
    PORT
      LAYER M3 ;
        RECT  63.54 0 63.558 0.037 ;
    END
  END t_k[534]
  PIN t_k[535]
    DIRECTION OUTPUT ;
    USE SIGNAL ;
    PORT
      LAYER M3 ;
        RECT  63.612 0 63.63 0.037 ;
    END
  END t_k[535]
  PIN t_k[536]
    DIRECTION OUTPUT ;
    USE SIGNAL ;
    PORT
      LAYER M3 ;
        RECT  63.684 0 63.702 0.037 ;
    END
  END t_k[536]
  PIN t_k[537]
    DIRECTION OUTPUT ;
    USE SIGNAL ;
    PORT
      LAYER M3 ;
        RECT  63.756 0 63.774 0.037 ;
    END
  END t_k[537]
  PIN t_k[538]
    DIRECTION OUTPUT ;
    USE SIGNAL ;
    PORT
      LAYER M3 ;
        RECT  63.828 0 63.846 0.037 ;
    END
  END t_k[538]
  PIN t_k[539]
    DIRECTION OUTPUT ;
    USE SIGNAL ;
    PORT
      LAYER M3 ;
        RECT  63.9 0 63.918 0.037 ;
    END
  END t_k[539]
  PIN t_k[53]
    DIRECTION OUTPUT ;
    USE SIGNAL ;
    PORT
      LAYER M5 ;
        RECT  55.44 0 55.464 0.084 ;
    END
  END t_k[53]
  PIN t_k[540]
    DIRECTION OUTPUT ;
    USE SIGNAL ;
    PORT
      LAYER M3 ;
        RECT  63.972 0 63.99 0.037 ;
    END
  END t_k[540]
  PIN t_k[541]
    DIRECTION OUTPUT ;
    USE SIGNAL ;
    PORT
      LAYER M3 ;
        RECT  64.044 0 64.062 0.037 ;
    END
  END t_k[541]
  PIN t_k[542]
    DIRECTION OUTPUT ;
    USE SIGNAL ;
    PORT
      LAYER M3 ;
        RECT  64.116 0 64.134 0.037 ;
    END
  END t_k[542]
  PIN t_k[543]
    DIRECTION OUTPUT ;
    USE SIGNAL ;
    PORT
      LAYER M3 ;
        RECT  64.188 0 64.206 0.037 ;
    END
  END t_k[543]
  PIN t_k[544]
    DIRECTION OUTPUT ;
    USE SIGNAL ;
    PORT
      LAYER M3 ;
        RECT  64.26 0 64.278 0.037 ;
    END
  END t_k[544]
  PIN t_k[545]
    DIRECTION OUTPUT ;
    USE SIGNAL ;
    PORT
      LAYER M3 ;
        RECT  64.332 0 64.35 0.037 ;
    END
  END t_k[545]
  PIN t_k[546]
    DIRECTION OUTPUT ;
    USE SIGNAL ;
    PORT
      LAYER M3 ;
        RECT  64.404 0 64.422 0.037 ;
    END
  END t_k[546]
  PIN t_k[547]
    DIRECTION OUTPUT ;
    USE SIGNAL ;
    PORT
      LAYER M3 ;
        RECT  64.476 0 64.494 0.037 ;
    END
  END t_k[547]
  PIN t_k[548]
    DIRECTION OUTPUT ;
    USE SIGNAL ;
    PORT
      LAYER M3 ;
        RECT  64.548 0 64.566 0.037 ;
    END
  END t_k[548]
  PIN t_k[549]
    DIRECTION OUTPUT ;
    USE SIGNAL ;
    PORT
      LAYER M3 ;
        RECT  64.62 0 64.638 0.037 ;
    END
  END t_k[549]
  PIN t_k[54]
    DIRECTION OUTPUT ;
    USE SIGNAL ;
    PORT
      LAYER M5 ;
        RECT  55.536 0 55.56 0.084 ;
    END
  END t_k[54]
  PIN t_k[550]
    DIRECTION OUTPUT ;
    USE SIGNAL ;
    PORT
      LAYER M3 ;
        RECT  64.692 0 64.71 0.037 ;
    END
  END t_k[550]
  PIN t_k[551]
    DIRECTION OUTPUT ;
    USE SIGNAL ;
    PORT
      LAYER M3 ;
        RECT  64.764 0 64.782 0.037 ;
    END
  END t_k[551]
  PIN t_k[552]
    DIRECTION OUTPUT ;
    USE SIGNAL ;
    PORT
      LAYER M3 ;
        RECT  64.836 0 64.854 0.037 ;
    END
  END t_k[552]
  PIN t_k[553]
    DIRECTION OUTPUT ;
    USE SIGNAL ;
    PORT
      LAYER M3 ;
        RECT  64.908 0 64.926 0.037 ;
    END
  END t_k[553]
  PIN t_k[554]
    DIRECTION OUTPUT ;
    USE SIGNAL ;
    PORT
      LAYER M3 ;
        RECT  64.98 0 64.998 0.037 ;
    END
  END t_k[554]
  PIN t_k[555]
    DIRECTION OUTPUT ;
    USE SIGNAL ;
    PORT
      LAYER M3 ;
        RECT  69.66 0 69.678 0.037 ;
    END
  END t_k[555]
  PIN t_k[556]
    DIRECTION OUTPUT ;
    USE SIGNAL ;
    PORT
      LAYER M3 ;
        RECT  69.732 0 69.75 0.037 ;
    END
  END t_k[556]
  PIN t_k[557]
    DIRECTION OUTPUT ;
    USE SIGNAL ;
    PORT
      LAYER M3 ;
        RECT  69.804 0 69.822 0.037 ;
    END
  END t_k[557]
  PIN t_k[558]
    DIRECTION OUTPUT ;
    USE SIGNAL ;
    PORT
      LAYER M3 ;
        RECT  69.876 0 69.894 0.037 ;
    END
  END t_k[558]
  PIN t_k[559]
    DIRECTION OUTPUT ;
    USE SIGNAL ;
    PORT
      LAYER M3 ;
        RECT  69.948 0 69.966 0.037 ;
    END
  END t_k[559]
  PIN t_k[55]
    DIRECTION OUTPUT ;
    USE SIGNAL ;
    PORT
      LAYER M5 ;
        RECT  55.632 0 55.656 0.084 ;
    END
  END t_k[55]
  PIN t_k[560]
    DIRECTION OUTPUT ;
    USE SIGNAL ;
    PORT
      LAYER M3 ;
        RECT  70.02 0 70.038 0.037 ;
    END
  END t_k[560]
  PIN t_k[561]
    DIRECTION OUTPUT ;
    USE SIGNAL ;
    PORT
      LAYER M3 ;
        RECT  70.092 0 70.11 0.037 ;
    END
  END t_k[561]
  PIN t_k[562]
    DIRECTION OUTPUT ;
    USE SIGNAL ;
    PORT
      LAYER M3 ;
        RECT  70.164 0 70.182 0.037 ;
    END
  END t_k[562]
  PIN t_k[563]
    DIRECTION OUTPUT ;
    USE SIGNAL ;
    PORT
      LAYER M3 ;
        RECT  70.236 0 70.254 0.037 ;
    END
  END t_k[563]
  PIN t_k[564]
    DIRECTION OUTPUT ;
    USE SIGNAL ;
    PORT
      LAYER M3 ;
        RECT  70.308 0 70.326 0.037 ;
    END
  END t_k[564]
  PIN t_k[565]
    DIRECTION OUTPUT ;
    USE SIGNAL ;
    PORT
      LAYER M3 ;
        RECT  70.38 0 70.398 0.037 ;
    END
  END t_k[565]
  PIN t_k[566]
    DIRECTION OUTPUT ;
    USE SIGNAL ;
    PORT
      LAYER M3 ;
        RECT  70.452 0 70.47 0.037 ;
    END
  END t_k[566]
  PIN t_k[567]
    DIRECTION OUTPUT ;
    USE SIGNAL ;
    PORT
      LAYER M3 ;
        RECT  70.524 0 70.542 0.037 ;
    END
  END t_k[567]
  PIN t_k[568]
    DIRECTION OUTPUT ;
    USE SIGNAL ;
    PORT
      LAYER M3 ;
        RECT  70.596 0 70.614 0.037 ;
    END
  END t_k[568]
  PIN t_k[569]
    DIRECTION OUTPUT ;
    USE SIGNAL ;
    PORT
      LAYER M3 ;
        RECT  70.668 0 70.686 0.037 ;
    END
  END t_k[569]
  PIN t_k[56]
    DIRECTION OUTPUT ;
    USE SIGNAL ;
    PORT
      LAYER M5 ;
        RECT  55.728 0 55.752 0.084 ;
    END
  END t_k[56]
  PIN t_k[570]
    DIRECTION OUTPUT ;
    USE SIGNAL ;
    PORT
      LAYER M3 ;
        RECT  70.74 0 70.758 0.037 ;
    END
  END t_k[570]
  PIN t_k[571]
    DIRECTION OUTPUT ;
    USE SIGNAL ;
    PORT
      LAYER M3 ;
        RECT  70.812 0 70.83 0.037 ;
    END
  END t_k[571]
  PIN t_k[572]
    DIRECTION OUTPUT ;
    USE SIGNAL ;
    PORT
      LAYER M3 ;
        RECT  70.884 0 70.902 0.037 ;
    END
  END t_k[572]
  PIN t_k[573]
    DIRECTION OUTPUT ;
    USE SIGNAL ;
    PORT
      LAYER M3 ;
        RECT  70.956 0 70.974 0.037 ;
    END
  END t_k[573]
  PIN t_k[574]
    DIRECTION OUTPUT ;
    USE SIGNAL ;
    PORT
      LAYER M3 ;
        RECT  71.028 0 71.046 0.037 ;
    END
  END t_k[574]
  PIN t_k[575]
    DIRECTION OUTPUT ;
    USE SIGNAL ;
    PORT
      LAYER M3 ;
        RECT  71.1 0 71.118 0.037 ;
    END
  END t_k[575]
  PIN t_k[576]
    DIRECTION OUTPUT ;
    USE SIGNAL ;
    PORT
      LAYER M3 ;
        RECT  71.172 0 71.19 0.037 ;
    END
  END t_k[576]
  PIN t_k[577]
    DIRECTION OUTPUT ;
    USE SIGNAL ;
    PORT
      LAYER M3 ;
        RECT  71.244 0 71.262 0.037 ;
    END
  END t_k[577]
  PIN t_k[578]
    DIRECTION OUTPUT ;
    USE SIGNAL ;
    PORT
      LAYER M3 ;
        RECT  71.316 0 71.334 0.037 ;
    END
  END t_k[578]
  PIN t_k[579]
    DIRECTION OUTPUT ;
    USE SIGNAL ;
    PORT
      LAYER M3 ;
        RECT  71.388 0 71.406 0.037 ;
    END
  END t_k[579]
  PIN t_k[57]
    DIRECTION OUTPUT ;
    USE SIGNAL ;
    PORT
      LAYER M5 ;
        RECT  55.824 0 55.848 0.084 ;
    END
  END t_k[57]
  PIN t_k[580]
    DIRECTION OUTPUT ;
    USE SIGNAL ;
    PORT
      LAYER M3 ;
        RECT  71.46 0 71.478 0.037 ;
    END
  END t_k[580]
  PIN t_k[581]
    DIRECTION OUTPUT ;
    USE SIGNAL ;
    PORT
      LAYER M3 ;
        RECT  71.532 0 71.55 0.037 ;
    END
  END t_k[581]
  PIN t_k[582]
    DIRECTION OUTPUT ;
    USE SIGNAL ;
    PORT
      LAYER M3 ;
        RECT  71.604 0 71.622 0.037 ;
    END
  END t_k[582]
  PIN t_k[583]
    DIRECTION OUTPUT ;
    USE SIGNAL ;
    PORT
      LAYER M3 ;
        RECT  71.676 0 71.694 0.037 ;
    END
  END t_k[583]
  PIN t_k[584]
    DIRECTION OUTPUT ;
    USE SIGNAL ;
    PORT
      LAYER M3 ;
        RECT  71.748 0 71.766 0.037 ;
    END
  END t_k[584]
  PIN t_k[585]
    DIRECTION OUTPUT ;
    USE SIGNAL ;
    PORT
      LAYER M3 ;
        RECT  71.82 0 71.838 0.037 ;
    END
  END t_k[585]
  PIN t_k[586]
    DIRECTION OUTPUT ;
    USE SIGNAL ;
    PORT
      LAYER M3 ;
        RECT  71.892 0 71.91 0.037 ;
    END
  END t_k[586]
  PIN t_k[587]
    DIRECTION OUTPUT ;
    USE SIGNAL ;
    PORT
      LAYER M5 ;
        RECT  22.992 0 23.016 0.084 ;
    END
  END t_k[587]
  PIN t_k[588]
    DIRECTION OUTPUT ;
    USE SIGNAL ;
    PORT
      LAYER M5 ;
        RECT  23.088 0 23.112 0.084 ;
    END
  END t_k[588]
  PIN t_k[589]
    DIRECTION OUTPUT ;
    USE SIGNAL ;
    PORT
      LAYER M5 ;
        RECT  23.184 0 23.208 0.084 ;
    END
  END t_k[589]
  PIN t_k[58]
    DIRECTION OUTPUT ;
    USE SIGNAL ;
    PORT
      LAYER M5 ;
        RECT  55.92 0 55.944 0.084 ;
    END
  END t_k[58]
  PIN t_k[590]
    DIRECTION OUTPUT ;
    USE SIGNAL ;
    PORT
      LAYER M5 ;
        RECT  23.28 0 23.304 0.084 ;
    END
  END t_k[590]
  PIN t_k[591]
    DIRECTION OUTPUT ;
    USE SIGNAL ;
    PORT
      LAYER M5 ;
        RECT  23.376 0 23.4 0.084 ;
    END
  END t_k[591]
  PIN t_k[592]
    DIRECTION OUTPUT ;
    USE SIGNAL ;
    PORT
      LAYER M5 ;
        RECT  23.472 0 23.496 0.084 ;
    END
  END t_k[592]
  PIN t_k[593]
    DIRECTION OUTPUT ;
    USE SIGNAL ;
    PORT
      LAYER M5 ;
        RECT  23.568 0 23.592 0.084 ;
    END
  END t_k[593]
  PIN t_k[594]
    DIRECTION OUTPUT ;
    USE SIGNAL ;
    PORT
      LAYER M5 ;
        RECT  23.664 0 23.688 0.084 ;
    END
  END t_k[594]
  PIN t_k[595]
    DIRECTION OUTPUT ;
    USE SIGNAL ;
    PORT
      LAYER M5 ;
        RECT  23.76 0 23.784 0.084 ;
    END
  END t_k[595]
  PIN t_k[596]
    DIRECTION OUTPUT ;
    USE SIGNAL ;
    PORT
      LAYER M5 ;
        RECT  23.856 0 23.88 0.084 ;
    END
  END t_k[596]
  PIN t_k[597]
    DIRECTION OUTPUT ;
    USE SIGNAL ;
    PORT
      LAYER M5 ;
        RECT  23.952 0 23.976 0.084 ;
    END
  END t_k[597]
  PIN t_k[598]
    DIRECTION OUTPUT ;
    USE SIGNAL ;
    PORT
      LAYER M5 ;
        RECT  24.048 0 24.072 0.084 ;
    END
  END t_k[598]
  PIN t_k[599]
    DIRECTION OUTPUT ;
    USE SIGNAL ;
    PORT
      LAYER M5 ;
        RECT  24.144 0 24.168 0.084 ;
    END
  END t_k[599]
  PIN t_k[59]
    DIRECTION OUTPUT ;
    USE SIGNAL ;
    PORT
      LAYER M5 ;
        RECT  56.016 0 56.04 0.084 ;
    END
  END t_k[59]
  PIN t_k[5]
    DIRECTION OUTPUT ;
    USE SIGNAL ;
    PORT
      LAYER M3 ;
        RECT  31.212 0 31.23 0.037 ;
    END
  END t_k[5]
  PIN t_k[600]
    DIRECTION OUTPUT ;
    USE SIGNAL ;
    PORT
      LAYER M5 ;
        RECT  24.24 0 24.264 0.084 ;
    END
  END t_k[600]
  PIN t_k[601]
    DIRECTION OUTPUT ;
    USE SIGNAL ;
    PORT
      LAYER M5 ;
        RECT  24.336 0 24.36 0.084 ;
    END
  END t_k[601]
  PIN t_k[602]
    DIRECTION OUTPUT ;
    USE SIGNAL ;
    PORT
      LAYER M5 ;
        RECT  24.432 0 24.456 0.084 ;
    END
  END t_k[602]
  PIN t_k[603]
    DIRECTION OUTPUT ;
    USE SIGNAL ;
    PORT
      LAYER M5 ;
        RECT  24.528 0 24.552 0.084 ;
    END
  END t_k[603]
  PIN t_k[604]
    DIRECTION OUTPUT ;
    USE SIGNAL ;
    PORT
      LAYER M5 ;
        RECT  24.624 0 24.648 0.084 ;
    END
  END t_k[604]
  PIN t_k[605]
    DIRECTION OUTPUT ;
    USE SIGNAL ;
    PORT
      LAYER M5 ;
        RECT  24.72 0 24.744 0.084 ;
    END
  END t_k[605]
  PIN t_k[606]
    DIRECTION OUTPUT ;
    USE SIGNAL ;
    PORT
      LAYER M5 ;
        RECT  24.816 0 24.84 0.084 ;
    END
  END t_k[606]
  PIN t_k[607]
    DIRECTION OUTPUT ;
    USE SIGNAL ;
    PORT
      LAYER M5 ;
        RECT  24.912 0 24.936 0.084 ;
    END
  END t_k[607]
  PIN t_k[608]
    DIRECTION OUTPUT ;
    USE SIGNAL ;
    PORT
      LAYER M5 ;
        RECT  25.008 0 25.032 0.084 ;
    END
  END t_k[608]
  PIN t_k[609]
    DIRECTION OUTPUT ;
    USE SIGNAL ;
    PORT
      LAYER M5 ;
        RECT  25.104 0 25.128 0.084 ;
    END
  END t_k[609]
  PIN t_k[60]
    DIRECTION OUTPUT ;
    USE SIGNAL ;
    PORT
      LAYER M5 ;
        RECT  56.112 0 56.136 0.084 ;
    END
  END t_k[60]
  PIN t_k[610]
    DIRECTION OUTPUT ;
    USE SIGNAL ;
    PORT
      LAYER M5 ;
        RECT  25.2 0 25.224 0.084 ;
    END
  END t_k[610]
  PIN t_k[611]
    DIRECTION OUTPUT ;
    USE SIGNAL ;
    PORT
      LAYER M5 ;
        RECT  25.296 0 25.32 0.084 ;
    END
  END t_k[611]
  PIN t_k[612]
    DIRECTION OUTPUT ;
    USE SIGNAL ;
    PORT
      LAYER M5 ;
        RECT  25.392 0 25.416 0.084 ;
    END
  END t_k[612]
  PIN t_k[613]
    DIRECTION OUTPUT ;
    USE SIGNAL ;
    PORT
      LAYER M5 ;
        RECT  25.488 0 25.512 0.084 ;
    END
  END t_k[613]
  PIN t_k[614]
    DIRECTION OUTPUT ;
    USE SIGNAL ;
    PORT
      LAYER M5 ;
        RECT  25.584 0 25.608 0.084 ;
    END
  END t_k[614]
  PIN t_k[615]
    DIRECTION OUTPUT ;
    USE SIGNAL ;
    PORT
      LAYER M5 ;
        RECT  25.68 0 25.704 0.084 ;
    END
  END t_k[615]
  PIN t_k[616]
    DIRECTION OUTPUT ;
    USE SIGNAL ;
    PORT
      LAYER M5 ;
        RECT  25.776 0 25.8 0.084 ;
    END
  END t_k[616]
  PIN t_k[617]
    DIRECTION OUTPUT ;
    USE SIGNAL ;
    PORT
      LAYER M5 ;
        RECT  25.872 0 25.896 0.084 ;
    END
  END t_k[617]
  PIN t_k[618]
    DIRECTION OUTPUT ;
    USE SIGNAL ;
    PORT
      LAYER M5 ;
        RECT  25.968 0 25.992 0.084 ;
    END
  END t_k[618]
  PIN t_k[619]
    DIRECTION OUTPUT ;
    USE SIGNAL ;
    PORT
      LAYER M3 ;
        RECT  67.356 0 67.374 0.037 ;
    END
  END t_k[619]
  PIN t_k[61]
    DIRECTION OUTPUT ;
    USE SIGNAL ;
    PORT
      LAYER M5 ;
        RECT  56.208 0 56.232 0.084 ;
    END
  END t_k[61]
  PIN t_k[620]
    DIRECTION OUTPUT ;
    USE SIGNAL ;
    PORT
      LAYER M3 ;
        RECT  67.428 0 67.446 0.037 ;
    END
  END t_k[620]
  PIN t_k[621]
    DIRECTION OUTPUT ;
    USE SIGNAL ;
    PORT
      LAYER M3 ;
        RECT  67.5 0 67.518 0.037 ;
    END
  END t_k[621]
  PIN t_k[622]
    DIRECTION OUTPUT ;
    USE SIGNAL ;
    PORT
      LAYER M3 ;
        RECT  67.572 0 67.59 0.037 ;
    END
  END t_k[622]
  PIN t_k[623]
    DIRECTION OUTPUT ;
    USE SIGNAL ;
    PORT
      LAYER M3 ;
        RECT  67.644 0 67.662 0.037 ;
    END
  END t_k[623]
  PIN t_k[624]
    DIRECTION OUTPUT ;
    USE SIGNAL ;
    PORT
      LAYER M3 ;
        RECT  67.716 0 67.734 0.037 ;
    END
  END t_k[624]
  PIN t_k[625]
    DIRECTION OUTPUT ;
    USE SIGNAL ;
    PORT
      LAYER M3 ;
        RECT  67.788 0 67.806 0.037 ;
    END
  END t_k[625]
  PIN t_k[626]
    DIRECTION OUTPUT ;
    USE SIGNAL ;
    PORT
      LAYER M3 ;
        RECT  67.86 0 67.878 0.037 ;
    END
  END t_k[626]
  PIN t_k[627]
    DIRECTION OUTPUT ;
    USE SIGNAL ;
    PORT
      LAYER M3 ;
        RECT  67.932 0 67.95 0.037 ;
    END
  END t_k[627]
  PIN t_k[628]
    DIRECTION OUTPUT ;
    USE SIGNAL ;
    PORT
      LAYER M3 ;
        RECT  68.004 0 68.022 0.037 ;
    END
  END t_k[628]
  PIN t_k[629]
    DIRECTION OUTPUT ;
    USE SIGNAL ;
    PORT
      LAYER M3 ;
        RECT  68.076 0 68.094 0.037 ;
    END
  END t_k[629]
  PIN t_k[62]
    DIRECTION OUTPUT ;
    USE SIGNAL ;
    PORT
      LAYER M5 ;
        RECT  56.304 0 56.328 0.084 ;
    END
  END t_k[62]
  PIN t_k[630]
    DIRECTION OUTPUT ;
    USE SIGNAL ;
    PORT
      LAYER M3 ;
        RECT  68.148 0 68.166 0.037 ;
    END
  END t_k[630]
  PIN t_k[631]
    DIRECTION OUTPUT ;
    USE SIGNAL ;
    PORT
      LAYER M3 ;
        RECT  68.22 0 68.238 0.037 ;
    END
  END t_k[631]
  PIN t_k[632]
    DIRECTION OUTPUT ;
    USE SIGNAL ;
    PORT
      LAYER M3 ;
        RECT  68.292 0 68.31 0.037 ;
    END
  END t_k[632]
  PIN t_k[633]
    DIRECTION OUTPUT ;
    USE SIGNAL ;
    PORT
      LAYER M3 ;
        RECT  68.364 0 68.382 0.037 ;
    END
  END t_k[633]
  PIN t_k[634]
    DIRECTION OUTPUT ;
    USE SIGNAL ;
    PORT
      LAYER M3 ;
        RECT  68.436 0 68.454 0.037 ;
    END
  END t_k[634]
  PIN t_k[635]
    DIRECTION OUTPUT ;
    USE SIGNAL ;
    PORT
      LAYER M3 ;
        RECT  68.508 0 68.526 0.037 ;
    END
  END t_k[635]
  PIN t_k[636]
    DIRECTION OUTPUT ;
    USE SIGNAL ;
    PORT
      LAYER M3 ;
        RECT  68.58 0 68.598 0.037 ;
    END
  END t_k[636]
  PIN t_k[637]
    DIRECTION OUTPUT ;
    USE SIGNAL ;
    PORT
      LAYER M3 ;
        RECT  68.652 0 68.67 0.037 ;
    END
  END t_k[637]
  PIN t_k[638]
    DIRECTION OUTPUT ;
    USE SIGNAL ;
    PORT
      LAYER M3 ;
        RECT  68.724 0 68.742 0.037 ;
    END
  END t_k[638]
  PIN t_k[639]
    DIRECTION OUTPUT ;
    USE SIGNAL ;
    PORT
      LAYER M3 ;
        RECT  68.796 0 68.814 0.037 ;
    END
  END t_k[639]
  PIN t_k[63]
    DIRECTION OUTPUT ;
    USE SIGNAL ;
    PORT
      LAYER M5 ;
        RECT  56.4 0 56.424 0.084 ;
    END
  END t_k[63]
  PIN t_k[640]
    DIRECTION OUTPUT ;
    USE SIGNAL ;
    PORT
      LAYER M3 ;
        RECT  68.868 0 68.886 0.037 ;
    END
  END t_k[640]
  PIN t_k[641]
    DIRECTION OUTPUT ;
    USE SIGNAL ;
    PORT
      LAYER M3 ;
        RECT  68.94 0 68.958 0.037 ;
    END
  END t_k[641]
  PIN t_k[642]
    DIRECTION OUTPUT ;
    USE SIGNAL ;
    PORT
      LAYER M3 ;
        RECT  69.012 0 69.03 0.037 ;
    END
  END t_k[642]
  PIN t_k[643]
    DIRECTION OUTPUT ;
    USE SIGNAL ;
    PORT
      LAYER M3 ;
        RECT  69.084 0 69.102 0.037 ;
    END
  END t_k[643]
  PIN t_k[644]
    DIRECTION OUTPUT ;
    USE SIGNAL ;
    PORT
      LAYER M3 ;
        RECT  69.156 0 69.174 0.037 ;
    END
  END t_k[644]
  PIN t_k[645]
    DIRECTION OUTPUT ;
    USE SIGNAL ;
    PORT
      LAYER M3 ;
        RECT  69.228 0 69.246 0.037 ;
    END
  END t_k[645]
  PIN t_k[646]
    DIRECTION OUTPUT ;
    USE SIGNAL ;
    PORT
      LAYER M3 ;
        RECT  69.3 0 69.318 0.037 ;
    END
  END t_k[646]
  PIN t_k[647]
    DIRECTION OUTPUT ;
    USE SIGNAL ;
    PORT
      LAYER M3 ;
        RECT  69.372 0 69.39 0.037 ;
    END
  END t_k[647]
  PIN t_k[648]
    DIRECTION OUTPUT ;
    USE SIGNAL ;
    PORT
      LAYER M3 ;
        RECT  69.444 0 69.462 0.037 ;
    END
  END t_k[648]
  PIN t_k[649]
    DIRECTION OUTPUT ;
    USE SIGNAL ;
    PORT
      LAYER M3 ;
        RECT  69.516 0 69.534 0.037 ;
    END
  END t_k[649]
  PIN t_k[64]
    DIRECTION OUTPUT ;
    USE SIGNAL ;
    PORT
      LAYER M5 ;
        RECT  56.496 0 56.52 0.084 ;
    END
  END t_k[64]
  PIN t_k[650]
    DIRECTION OUTPUT ;
    USE SIGNAL ;
    PORT
      LAYER M3 ;
        RECT  69.588 0 69.606 0.037 ;
    END
  END t_k[650]
  PIN t_k[651]
    DIRECTION OUTPUT ;
    USE SIGNAL ;
    PORT
      LAYER M3 ;
        RECT  60.444 0 60.462 0.037 ;
    END
  END t_k[651]
  PIN t_k[652]
    DIRECTION OUTPUT ;
    USE SIGNAL ;
    PORT
      LAYER M3 ;
        RECT  60.516 0 60.534 0.037 ;
    END
  END t_k[652]
  PIN t_k[653]
    DIRECTION OUTPUT ;
    USE SIGNAL ;
    PORT
      LAYER M3 ;
        RECT  60.588 0 60.606 0.037 ;
    END
  END t_k[653]
  PIN t_k[654]
    DIRECTION OUTPUT ;
    USE SIGNAL ;
    PORT
      LAYER M3 ;
        RECT  60.66 0 60.678 0.037 ;
    END
  END t_k[654]
  PIN t_k[655]
    DIRECTION OUTPUT ;
    USE SIGNAL ;
    PORT
      LAYER M3 ;
        RECT  60.732 0 60.75 0.037 ;
    END
  END t_k[655]
  PIN t_k[656]
    DIRECTION OUTPUT ;
    USE SIGNAL ;
    PORT
      LAYER M3 ;
        RECT  60.804 0 60.822 0.037 ;
    END
  END t_k[656]
  PIN t_k[657]
    DIRECTION OUTPUT ;
    USE SIGNAL ;
    PORT
      LAYER M3 ;
        RECT  60.876 0 60.894 0.037 ;
    END
  END t_k[657]
  PIN t_k[658]
    DIRECTION OUTPUT ;
    USE SIGNAL ;
    PORT
      LAYER M3 ;
        RECT  60.948 0 60.966 0.037 ;
    END
  END t_k[658]
  PIN t_k[659]
    DIRECTION OUTPUT ;
    USE SIGNAL ;
    PORT
      LAYER M3 ;
        RECT  61.02 0 61.038 0.037 ;
    END
  END t_k[659]
  PIN t_k[65]
    DIRECTION OUTPUT ;
    USE SIGNAL ;
    PORT
      LAYER M5 ;
        RECT  56.592 0 56.616 0.084 ;
    END
  END t_k[65]
  PIN t_k[660]
    DIRECTION OUTPUT ;
    USE SIGNAL ;
    PORT
      LAYER M3 ;
        RECT  61.092 0 61.11 0.037 ;
    END
  END t_k[660]
  PIN t_k[661]
    DIRECTION OUTPUT ;
    USE SIGNAL ;
    PORT
      LAYER M3 ;
        RECT  61.164 0 61.182 0.037 ;
    END
  END t_k[661]
  PIN t_k[662]
    DIRECTION OUTPUT ;
    USE SIGNAL ;
    PORT
      LAYER M3 ;
        RECT  61.236 0 61.254 0.037 ;
    END
  END t_k[662]
  PIN t_k[663]
    DIRECTION OUTPUT ;
    USE SIGNAL ;
    PORT
      LAYER M3 ;
        RECT  61.308 0 61.326 0.037 ;
    END
  END t_k[663]
  PIN t_k[664]
    DIRECTION OUTPUT ;
    USE SIGNAL ;
    PORT
      LAYER M3 ;
        RECT  61.38 0 61.398 0.037 ;
    END
  END t_k[664]
  PIN t_k[665]
    DIRECTION OUTPUT ;
    USE SIGNAL ;
    PORT
      LAYER M3 ;
        RECT  61.452 0 61.47 0.037 ;
    END
  END t_k[665]
  PIN t_k[666]
    DIRECTION OUTPUT ;
    USE SIGNAL ;
    PORT
      LAYER M3 ;
        RECT  61.524 0 61.542 0.037 ;
    END
  END t_k[666]
  PIN t_k[667]
    DIRECTION OUTPUT ;
    USE SIGNAL ;
    PORT
      LAYER M3 ;
        RECT  61.596 0 61.614 0.037 ;
    END
  END t_k[667]
  PIN t_k[668]
    DIRECTION OUTPUT ;
    USE SIGNAL ;
    PORT
      LAYER M3 ;
        RECT  61.668 0 61.686 0.037 ;
    END
  END t_k[668]
  PIN t_k[669]
    DIRECTION OUTPUT ;
    USE SIGNAL ;
    PORT
      LAYER M3 ;
        RECT  61.74 0 61.758 0.037 ;
    END
  END t_k[669]
  PIN t_k[66]
    DIRECTION OUTPUT ;
    USE SIGNAL ;
    PORT
      LAYER M5 ;
        RECT  56.688 0 56.712 0.084 ;
    END
  END t_k[66]
  PIN t_k[670]
    DIRECTION OUTPUT ;
    USE SIGNAL ;
    PORT
      LAYER M3 ;
        RECT  61.812 0 61.83 0.037 ;
    END
  END t_k[670]
  PIN t_k[671]
    DIRECTION OUTPUT ;
    USE SIGNAL ;
    PORT
      LAYER M3 ;
        RECT  61.884 0 61.902 0.037 ;
    END
  END t_k[671]
  PIN t_k[672]
    DIRECTION OUTPUT ;
    USE SIGNAL ;
    PORT
      LAYER M3 ;
        RECT  61.956 0 61.974 0.037 ;
    END
  END t_k[672]
  PIN t_k[673]
    DIRECTION OUTPUT ;
    USE SIGNAL ;
    PORT
      LAYER M3 ;
        RECT  62.028 0 62.046 0.037 ;
    END
  END t_k[673]
  PIN t_k[674]
    DIRECTION OUTPUT ;
    USE SIGNAL ;
    PORT
      LAYER M3 ;
        RECT  62.1 0 62.118 0.037 ;
    END
  END t_k[674]
  PIN t_k[675]
    DIRECTION OUTPUT ;
    USE SIGNAL ;
    PORT
      LAYER M3 ;
        RECT  62.172 0 62.19 0.037 ;
    END
  END t_k[675]
  PIN t_k[676]
    DIRECTION OUTPUT ;
    USE SIGNAL ;
    PORT
      LAYER M3 ;
        RECT  62.244 0 62.262 0.037 ;
    END
  END t_k[676]
  PIN t_k[677]
    DIRECTION OUTPUT ;
    USE SIGNAL ;
    PORT
      LAYER M3 ;
        RECT  62.316 0 62.334 0.037 ;
    END
  END t_k[677]
  PIN t_k[678]
    DIRECTION OUTPUT ;
    USE SIGNAL ;
    PORT
      LAYER M3 ;
        RECT  62.388 0 62.406 0.037 ;
    END
  END t_k[678]
  PIN t_k[679]
    DIRECTION OUTPUT ;
    USE SIGNAL ;
    PORT
      LAYER M3 ;
        RECT  62.46 0 62.478 0.037 ;
    END
  END t_k[679]
  PIN t_k[67]
    DIRECTION OUTPUT ;
    USE SIGNAL ;
    PORT
      LAYER M5 ;
        RECT  56.784 0 56.808 0.084 ;
    END
  END t_k[67]
  PIN t_k[680]
    DIRECTION OUTPUT ;
    USE SIGNAL ;
    PORT
      LAYER M3 ;
        RECT  62.532 0 62.55 0.037 ;
    END
  END t_k[680]
  PIN t_k[681]
    DIRECTION OUTPUT ;
    USE SIGNAL ;
    PORT
      LAYER M3 ;
        RECT  62.604 0 62.622 0.037 ;
    END
  END t_k[681]
  PIN t_k[682]
    DIRECTION OUTPUT ;
    USE SIGNAL ;
    PORT
      LAYER M3 ;
        RECT  62.676 0 62.694 0.037 ;
    END
  END t_k[682]
  PIN t_k[683]
    DIRECTION OUTPUT ;
    USE SIGNAL ;
    PORT
      LAYER M5 ;
        RECT  35.28 0 35.304 0.084 ;
    END
  END t_k[683]
  PIN t_k[684]
    DIRECTION OUTPUT ;
    USE SIGNAL ;
    PORT
      LAYER M5 ;
        RECT  35.376 0 35.4 0.084 ;
    END
  END t_k[684]
  PIN t_k[685]
    DIRECTION OUTPUT ;
    USE SIGNAL ;
    PORT
      LAYER M5 ;
        RECT  35.472 0 35.496 0.084 ;
    END
  END t_k[685]
  PIN t_k[686]
    DIRECTION OUTPUT ;
    USE SIGNAL ;
    PORT
      LAYER M5 ;
        RECT  35.568 0 35.592 0.084 ;
    END
  END t_k[686]
  PIN t_k[687]
    DIRECTION OUTPUT ;
    USE SIGNAL ;
    PORT
      LAYER M5 ;
        RECT  35.664 0 35.688 0.084 ;
    END
  END t_k[687]
  PIN t_k[688]
    DIRECTION OUTPUT ;
    USE SIGNAL ;
    PORT
      LAYER M5 ;
        RECT  35.76 0 35.784 0.084 ;
    END
  END t_k[688]
  PIN t_k[689]
    DIRECTION OUTPUT ;
    USE SIGNAL ;
    PORT
      LAYER M5 ;
        RECT  35.856 0 35.88 0.084 ;
    END
  END t_k[689]
  PIN t_k[68]
    DIRECTION OUTPUT ;
    USE SIGNAL ;
    PORT
      LAYER M5 ;
        RECT  56.88 0 56.904 0.084 ;
    END
  END t_k[68]
  PIN t_k[690]
    DIRECTION OUTPUT ;
    USE SIGNAL ;
    PORT
      LAYER M5 ;
        RECT  35.952 0 35.976 0.084 ;
    END
  END t_k[690]
  PIN t_k[691]
    DIRECTION OUTPUT ;
    USE SIGNAL ;
    PORT
      LAYER M5 ;
        RECT  36.048 0 36.072 0.084 ;
    END
  END t_k[691]
  PIN t_k[692]
    DIRECTION OUTPUT ;
    USE SIGNAL ;
    PORT
      LAYER M5 ;
        RECT  36.144 0 36.168 0.084 ;
    END
  END t_k[692]
  PIN t_k[693]
    DIRECTION OUTPUT ;
    USE SIGNAL ;
    PORT
      LAYER M5 ;
        RECT  36.24 0 36.264 0.084 ;
    END
  END t_k[693]
  PIN t_k[694]
    DIRECTION OUTPUT ;
    USE SIGNAL ;
    PORT
      LAYER M5 ;
        RECT  36.336 0 36.36 0.084 ;
    END
  END t_k[694]
  PIN t_k[695]
    DIRECTION OUTPUT ;
    USE SIGNAL ;
    PORT
      LAYER M5 ;
        RECT  36.432 0 36.456 0.084 ;
    END
  END t_k[695]
  PIN t_k[696]
    DIRECTION OUTPUT ;
    USE SIGNAL ;
    PORT
      LAYER M5 ;
        RECT  36.528 0 36.552 0.084 ;
    END
  END t_k[696]
  PIN t_k[697]
    DIRECTION OUTPUT ;
    USE SIGNAL ;
    PORT
      LAYER M5 ;
        RECT  36.624 0 36.648 0.084 ;
    END
  END t_k[697]
  PIN t_k[698]
    DIRECTION OUTPUT ;
    USE SIGNAL ;
    PORT
      LAYER M5 ;
        RECT  36.72 0 36.744 0.084 ;
    END
  END t_k[698]
  PIN t_k[699]
    DIRECTION OUTPUT ;
    USE SIGNAL ;
    PORT
      LAYER M5 ;
        RECT  36.816 0 36.84 0.084 ;
    END
  END t_k[699]
  PIN t_k[69]
    DIRECTION OUTPUT ;
    USE SIGNAL ;
    PORT
      LAYER M5 ;
        RECT  56.976 0 57 0.084 ;
    END
  END t_k[69]
  PIN t_k[6]
    DIRECTION OUTPUT ;
    USE SIGNAL ;
    PORT
      LAYER M3 ;
        RECT  31.284 0 31.302 0.037 ;
    END
  END t_k[6]
  PIN t_k[700]
    DIRECTION OUTPUT ;
    USE SIGNAL ;
    PORT
      LAYER M5 ;
        RECT  36.912 0 36.936 0.084 ;
    END
  END t_k[700]
  PIN t_k[701]
    DIRECTION OUTPUT ;
    USE SIGNAL ;
    PORT
      LAYER M5 ;
        RECT  37.008 0 37.032 0.084 ;
    END
  END t_k[701]
  PIN t_k[702]
    DIRECTION OUTPUT ;
    USE SIGNAL ;
    PORT
      LAYER M5 ;
        RECT  37.104 0 37.128 0.084 ;
    END
  END t_k[702]
  PIN t_k[703]
    DIRECTION OUTPUT ;
    USE SIGNAL ;
    PORT
      LAYER M5 ;
        RECT  37.2 0 37.224 0.084 ;
    END
  END t_k[703]
  PIN t_k[704]
    DIRECTION OUTPUT ;
    USE SIGNAL ;
    PORT
      LAYER M5 ;
        RECT  37.296 0 37.32 0.084 ;
    END
  END t_k[704]
  PIN t_k[705]
    DIRECTION OUTPUT ;
    USE SIGNAL ;
    PORT
      LAYER M5 ;
        RECT  37.392 0 37.416 0.084 ;
    END
  END t_k[705]
  PIN t_k[706]
    DIRECTION OUTPUT ;
    USE SIGNAL ;
    PORT
      LAYER M5 ;
        RECT  37.488 0 37.512 0.084 ;
    END
  END t_k[706]
  PIN t_k[707]
    DIRECTION OUTPUT ;
    USE SIGNAL ;
    PORT
      LAYER M5 ;
        RECT  37.584 0 37.608 0.084 ;
    END
  END t_k[707]
  PIN t_k[708]
    DIRECTION OUTPUT ;
    USE SIGNAL ;
    PORT
      LAYER M5 ;
        RECT  37.68 0 37.704 0.084 ;
    END
  END t_k[708]
  PIN t_k[709]
    DIRECTION OUTPUT ;
    USE SIGNAL ;
    PORT
      LAYER M5 ;
        RECT  37.776 0 37.8 0.084 ;
    END
  END t_k[709]
  PIN t_k[70]
    DIRECTION OUTPUT ;
    USE SIGNAL ;
    PORT
      LAYER M5 ;
        RECT  57.072 0 57.096 0.084 ;
    END
  END t_k[70]
  PIN t_k[710]
    DIRECTION OUTPUT ;
    USE SIGNAL ;
    PORT
      LAYER M5 ;
        RECT  37.872 0 37.896 0.084 ;
    END
  END t_k[710]
  PIN t_k[711]
    DIRECTION OUTPUT ;
    USE SIGNAL ;
    PORT
      LAYER M5 ;
        RECT  37.968 0 37.992 0.084 ;
    END
  END t_k[711]
  PIN t_k[712]
    DIRECTION OUTPUT ;
    USE SIGNAL ;
    PORT
      LAYER M5 ;
        RECT  38.064 0 38.088 0.084 ;
    END
  END t_k[712]
  PIN t_k[713]
    DIRECTION OUTPUT ;
    USE SIGNAL ;
    PORT
      LAYER M5 ;
        RECT  38.16 0 38.184 0.084 ;
    END
  END t_k[713]
  PIN t_k[714]
    DIRECTION OUTPUT ;
    USE SIGNAL ;
    PORT
      LAYER M5 ;
        RECT  38.256 0 38.28 0.084 ;
    END
  END t_k[714]
  PIN t_k[715]
    DIRECTION OUTPUT ;
    USE SIGNAL ;
    PORT
      LAYER M5 ;
        RECT  29.136 0 29.16 0.084 ;
    END
  END t_k[715]
  PIN t_k[716]
    DIRECTION OUTPUT ;
    USE SIGNAL ;
    PORT
      LAYER M5 ;
        RECT  29.232 0 29.256 0.084 ;
    END
  END t_k[716]
  PIN t_k[717]
    DIRECTION OUTPUT ;
    USE SIGNAL ;
    PORT
      LAYER M5 ;
        RECT  29.328 0 29.352 0.084 ;
    END
  END t_k[717]
  PIN t_k[718]
    DIRECTION OUTPUT ;
    USE SIGNAL ;
    PORT
      LAYER M5 ;
        RECT  29.424 0 29.448 0.084 ;
    END
  END t_k[718]
  PIN t_k[719]
    DIRECTION OUTPUT ;
    USE SIGNAL ;
    PORT
      LAYER M5 ;
        RECT  29.52 0 29.544 0.084 ;
    END
  END t_k[719]
  PIN t_k[71]
    DIRECTION OUTPUT ;
    USE SIGNAL ;
    PORT
      LAYER M5 ;
        RECT  57.168 0 57.192 0.084 ;
    END
  END t_k[71]
  PIN t_k[720]
    DIRECTION OUTPUT ;
    USE SIGNAL ;
    PORT
      LAYER M5 ;
        RECT  29.616 0 29.64 0.084 ;
    END
  END t_k[720]
  PIN t_k[721]
    DIRECTION OUTPUT ;
    USE SIGNAL ;
    PORT
      LAYER M5 ;
        RECT  29.712 0 29.736 0.084 ;
    END
  END t_k[721]
  PIN t_k[722]
    DIRECTION OUTPUT ;
    USE SIGNAL ;
    PORT
      LAYER M5 ;
        RECT  29.808 0 29.832 0.084 ;
    END
  END t_k[722]
  PIN t_k[723]
    DIRECTION OUTPUT ;
    USE SIGNAL ;
    PORT
      LAYER M5 ;
        RECT  29.904 0 29.928 0.084 ;
    END
  END t_k[723]
  PIN t_k[724]
    DIRECTION OUTPUT ;
    USE SIGNAL ;
    PORT
      LAYER M5 ;
        RECT  30 0 30.024 0.084 ;
    END
  END t_k[724]
  PIN t_k[725]
    DIRECTION OUTPUT ;
    USE SIGNAL ;
    PORT
      LAYER M5 ;
        RECT  30.096 0 30.12 0.084 ;
    END
  END t_k[725]
  PIN t_k[726]
    DIRECTION OUTPUT ;
    USE SIGNAL ;
    PORT
      LAYER M5 ;
        RECT  30.192 0 30.216 0.084 ;
    END
  END t_k[726]
  PIN t_k[727]
    DIRECTION OUTPUT ;
    USE SIGNAL ;
    PORT
      LAYER M5 ;
        RECT  30.288 0 30.312 0.084 ;
    END
  END t_k[727]
  PIN t_k[728]
    DIRECTION OUTPUT ;
    USE SIGNAL ;
    PORT
      LAYER M5 ;
        RECT  30.384 0 30.408 0.084 ;
    END
  END t_k[728]
  PIN t_k[729]
    DIRECTION OUTPUT ;
    USE SIGNAL ;
    PORT
      LAYER M5 ;
        RECT  30.48 0 30.504 0.084 ;
    END
  END t_k[729]
  PIN t_k[72]
    DIRECTION OUTPUT ;
    USE SIGNAL ;
    PORT
      LAYER M5 ;
        RECT  57.264 0 57.288 0.084 ;
    END
  END t_k[72]
  PIN t_k[730]
    DIRECTION OUTPUT ;
    USE SIGNAL ;
    PORT
      LAYER M5 ;
        RECT  30.576 0 30.6 0.084 ;
    END
  END t_k[730]
  PIN t_k[731]
    DIRECTION OUTPUT ;
    USE SIGNAL ;
    PORT
      LAYER M5 ;
        RECT  30.672 0 30.696 0.084 ;
    END
  END t_k[731]
  PIN t_k[732]
    DIRECTION OUTPUT ;
    USE SIGNAL ;
    PORT
      LAYER M5 ;
        RECT  30.768 0 30.792 0.084 ;
    END
  END t_k[732]
  PIN t_k[733]
    DIRECTION OUTPUT ;
    USE SIGNAL ;
    PORT
      LAYER M5 ;
        RECT  30.864 0 30.888 0.084 ;
    END
  END t_k[733]
  PIN t_k[734]
    DIRECTION OUTPUT ;
    USE SIGNAL ;
    PORT
      LAYER M5 ;
        RECT  30.96 0 30.984 0.084 ;
    END
  END t_k[734]
  PIN t_k[735]
    DIRECTION OUTPUT ;
    USE SIGNAL ;
    PORT
      LAYER M5 ;
        RECT  31.056 0 31.08 0.084 ;
    END
  END t_k[735]
  PIN t_k[736]
    DIRECTION OUTPUT ;
    USE SIGNAL ;
    PORT
      LAYER M5 ;
        RECT  31.152 0 31.176 0.084 ;
    END
  END t_k[736]
  PIN t_k[737]
    DIRECTION OUTPUT ;
    USE SIGNAL ;
    PORT
      LAYER M5 ;
        RECT  31.248 0 31.272 0.084 ;
    END
  END t_k[737]
  PIN t_k[738]
    DIRECTION OUTPUT ;
    USE SIGNAL ;
    PORT
      LAYER M5 ;
        RECT  31.344 0 31.368 0.084 ;
    END
  END t_k[738]
  PIN t_k[739]
    DIRECTION OUTPUT ;
    USE SIGNAL ;
    PORT
      LAYER M5 ;
        RECT  31.44 0 31.464 0.084 ;
    END
  END t_k[739]
  PIN t_k[73]
    DIRECTION OUTPUT ;
    USE SIGNAL ;
    PORT
      LAYER M5 ;
        RECT  57.36 0 57.384 0.084 ;
    END
  END t_k[73]
  PIN t_k[740]
    DIRECTION OUTPUT ;
    USE SIGNAL ;
    PORT
      LAYER M5 ;
        RECT  31.536 0 31.56 0.084 ;
    END
  END t_k[740]
  PIN t_k[741]
    DIRECTION OUTPUT ;
    USE SIGNAL ;
    PORT
      LAYER M5 ;
        RECT  31.632 0 31.656 0.084 ;
    END
  END t_k[741]
  PIN t_k[742]
    DIRECTION OUTPUT ;
    USE SIGNAL ;
    PORT
      LAYER M5 ;
        RECT  31.728 0 31.752 0.084 ;
    END
  END t_k[742]
  PIN t_k[743]
    DIRECTION OUTPUT ;
    USE SIGNAL ;
    PORT
      LAYER M5 ;
        RECT  31.824 0 31.848 0.084 ;
    END
  END t_k[743]
  PIN t_k[744]
    DIRECTION OUTPUT ;
    USE SIGNAL ;
    PORT
      LAYER M5 ;
        RECT  31.92 0 31.944 0.084 ;
    END
  END t_k[744]
  PIN t_k[745]
    DIRECTION OUTPUT ;
    USE SIGNAL ;
    PORT
      LAYER M5 ;
        RECT  32.016 0 32.04 0.084 ;
    END
  END t_k[745]
  PIN t_k[746]
    DIRECTION OUTPUT ;
    USE SIGNAL ;
    PORT
      LAYER M5 ;
        RECT  32.112 0 32.136 0.084 ;
    END
  END t_k[746]
  PIN t_k[747]
    DIRECTION OUTPUT ;
    USE SIGNAL ;
    PORT
      LAYER M5 ;
        RECT  19.92 0 19.944 0.084 ;
    END
  END t_k[747]
  PIN t_k[748]
    DIRECTION OUTPUT ;
    USE SIGNAL ;
    PORT
      LAYER M5 ;
        RECT  20.016 0 20.04 0.084 ;
    END
  END t_k[748]
  PIN t_k[749]
    DIRECTION OUTPUT ;
    USE SIGNAL ;
    PORT
      LAYER M5 ;
        RECT  20.112 0 20.136 0.084 ;
    END
  END t_k[749]
  PIN t_k[74]
    DIRECTION OUTPUT ;
    USE SIGNAL ;
    PORT
      LAYER M5 ;
        RECT  57.456 0 57.48 0.084 ;
    END
  END t_k[74]
  PIN t_k[750]
    DIRECTION OUTPUT ;
    USE SIGNAL ;
    PORT
      LAYER M5 ;
        RECT  20.208 0 20.232 0.084 ;
    END
  END t_k[750]
  PIN t_k[751]
    DIRECTION OUTPUT ;
    USE SIGNAL ;
    PORT
      LAYER M5 ;
        RECT  20.304 0 20.328 0.084 ;
    END
  END t_k[751]
  PIN t_k[752]
    DIRECTION OUTPUT ;
    USE SIGNAL ;
    PORT
      LAYER M5 ;
        RECT  20.4 0 20.424 0.084 ;
    END
  END t_k[752]
  PIN t_k[753]
    DIRECTION OUTPUT ;
    USE SIGNAL ;
    PORT
      LAYER M5 ;
        RECT  20.496 0 20.52 0.084 ;
    END
  END t_k[753]
  PIN t_k[754]
    DIRECTION OUTPUT ;
    USE SIGNAL ;
    PORT
      LAYER M5 ;
        RECT  20.592 0 20.616 0.084 ;
    END
  END t_k[754]
  PIN t_k[755]
    DIRECTION OUTPUT ;
    USE SIGNAL ;
    PORT
      LAYER M5 ;
        RECT  20.688 0 20.712 0.084 ;
    END
  END t_k[755]
  PIN t_k[756]
    DIRECTION OUTPUT ;
    USE SIGNAL ;
    PORT
      LAYER M5 ;
        RECT  20.784 0 20.808 0.084 ;
    END
  END t_k[756]
  PIN t_k[757]
    DIRECTION OUTPUT ;
    USE SIGNAL ;
    PORT
      LAYER M5 ;
        RECT  20.88 0 20.904 0.084 ;
    END
  END t_k[757]
  PIN t_k[758]
    DIRECTION OUTPUT ;
    USE SIGNAL ;
    PORT
      LAYER M5 ;
        RECT  20.976 0 21 0.084 ;
    END
  END t_k[758]
  PIN t_k[759]
    DIRECTION OUTPUT ;
    USE SIGNAL ;
    PORT
      LAYER M5 ;
        RECT  21.072 0 21.096 0.084 ;
    END
  END t_k[759]
  PIN t_k[75]
    DIRECTION OUTPUT ;
    USE SIGNAL ;
    PORT
      LAYER M5 ;
        RECT  51.408 0 51.432 0.084 ;
    END
  END t_k[75]
  PIN t_k[760]
    DIRECTION OUTPUT ;
    USE SIGNAL ;
    PORT
      LAYER M5 ;
        RECT  21.168 0 21.192 0.084 ;
    END
  END t_k[760]
  PIN t_k[761]
    DIRECTION OUTPUT ;
    USE SIGNAL ;
    PORT
      LAYER M5 ;
        RECT  21.264 0 21.288 0.084 ;
    END
  END t_k[761]
  PIN t_k[762]
    DIRECTION OUTPUT ;
    USE SIGNAL ;
    PORT
      LAYER M5 ;
        RECT  21.36 0 21.384 0.084 ;
    END
  END t_k[762]
  PIN t_k[763]
    DIRECTION OUTPUT ;
    USE SIGNAL ;
    PORT
      LAYER M5 ;
        RECT  21.456 0 21.48 0.084 ;
    END
  END t_k[763]
  PIN t_k[764]
    DIRECTION OUTPUT ;
    USE SIGNAL ;
    PORT
      LAYER M5 ;
        RECT  21.552 0 21.576 0.084 ;
    END
  END t_k[764]
  PIN t_k[765]
    DIRECTION OUTPUT ;
    USE SIGNAL ;
    PORT
      LAYER M5 ;
        RECT  21.648 0 21.672 0.084 ;
    END
  END t_k[765]
  PIN t_k[766]
    DIRECTION OUTPUT ;
    USE SIGNAL ;
    PORT
      LAYER M5 ;
        RECT  21.744 0 21.768 0.084 ;
    END
  END t_k[766]
  PIN t_k[767]
    DIRECTION OUTPUT ;
    USE SIGNAL ;
    PORT
      LAYER M5 ;
        RECT  21.84 0 21.864 0.084 ;
    END
  END t_k[767]
  PIN t_k[768]
    DIRECTION OUTPUT ;
    USE SIGNAL ;
    PORT
      LAYER M5 ;
        RECT  21.936 0 21.96 0.084 ;
    END
  END t_k[768]
  PIN t_k[769]
    DIRECTION OUTPUT ;
    USE SIGNAL ;
    PORT
      LAYER M5 ;
        RECT  22.032 0 22.056 0.084 ;
    END
  END t_k[769]
  PIN t_k[76]
    DIRECTION OUTPUT ;
    USE SIGNAL ;
    PORT
      LAYER M5 ;
        RECT  51.504 0 51.528 0.084 ;
    END
  END t_k[76]
  PIN t_k[770]
    DIRECTION OUTPUT ;
    USE SIGNAL ;
    PORT
      LAYER M5 ;
        RECT  22.128 0 22.152 0.084 ;
    END
  END t_k[770]
  PIN t_k[771]
    DIRECTION OUTPUT ;
    USE SIGNAL ;
    PORT
      LAYER M5 ;
        RECT  22.224 0 22.248 0.084 ;
    END
  END t_k[771]
  PIN t_k[772]
    DIRECTION OUTPUT ;
    USE SIGNAL ;
    PORT
      LAYER M5 ;
        RECT  22.32 0 22.344 0.084 ;
    END
  END t_k[772]
  PIN t_k[773]
    DIRECTION OUTPUT ;
    USE SIGNAL ;
    PORT
      LAYER M5 ;
        RECT  22.416 0 22.44 0.084 ;
    END
  END t_k[773]
  PIN t_k[774]
    DIRECTION OUTPUT ;
    USE SIGNAL ;
    PORT
      LAYER M5 ;
        RECT  22.512 0 22.536 0.084 ;
    END
  END t_k[774]
  PIN t_k[775]
    DIRECTION OUTPUT ;
    USE SIGNAL ;
    PORT
      LAYER M5 ;
        RECT  22.608 0 22.632 0.084 ;
    END
  END t_k[775]
  PIN t_k[776]
    DIRECTION OUTPUT ;
    USE SIGNAL ;
    PORT
      LAYER M5 ;
        RECT  22.704 0 22.728 0.084 ;
    END
  END t_k[776]
  PIN t_k[777]
    DIRECTION OUTPUT ;
    USE SIGNAL ;
    PORT
      LAYER M5 ;
        RECT  22.8 0 22.824 0.084 ;
    END
  END t_k[777]
  PIN t_k[778]
    DIRECTION OUTPUT ;
    USE SIGNAL ;
    PORT
      LAYER M5 ;
        RECT  22.896 0 22.92 0.084 ;
    END
  END t_k[778]
  PIN t_k[779]
    DIRECTION OUTPUT ;
    USE SIGNAL ;
    PORT
      LAYER M3 ;
        RECT  24.156 0 24.174 0.037 ;
    END
  END t_k[779]
  PIN t_k[77]
    DIRECTION OUTPUT ;
    USE SIGNAL ;
    PORT
      LAYER M5 ;
        RECT  51.6 0 51.624 0.084 ;
    END
  END t_k[77]
  PIN t_k[780]
    DIRECTION OUTPUT ;
    USE SIGNAL ;
    PORT
      LAYER M3 ;
        RECT  24.228 0 24.246 0.037 ;
    END
  END t_k[780]
  PIN t_k[781]
    DIRECTION OUTPUT ;
    USE SIGNAL ;
    PORT
      LAYER M3 ;
        RECT  24.3 0 24.318 0.037 ;
    END
  END t_k[781]
  PIN t_k[782]
    DIRECTION OUTPUT ;
    USE SIGNAL ;
    PORT
      LAYER M3 ;
        RECT  24.372 0 24.39 0.037 ;
    END
  END t_k[782]
  PIN t_k[783]
    DIRECTION OUTPUT ;
    USE SIGNAL ;
    PORT
      LAYER M3 ;
        RECT  24.444 0 24.462 0.037 ;
    END
  END t_k[783]
  PIN t_k[784]
    DIRECTION OUTPUT ;
    USE SIGNAL ;
    PORT
      LAYER M3 ;
        RECT  24.516 0 24.534 0.037 ;
    END
  END t_k[784]
  PIN t_k[785]
    DIRECTION OUTPUT ;
    USE SIGNAL ;
    PORT
      LAYER M3 ;
        RECT  24.588 0 24.606 0.037 ;
    END
  END t_k[785]
  PIN t_k[786]
    DIRECTION OUTPUT ;
    USE SIGNAL ;
    PORT
      LAYER M3 ;
        RECT  24.66 0 24.678 0.037 ;
    END
  END t_k[786]
  PIN t_k[787]
    DIRECTION OUTPUT ;
    USE SIGNAL ;
    PORT
      LAYER M3 ;
        RECT  24.732 0 24.75 0.037 ;
    END
  END t_k[787]
  PIN t_k[788]
    DIRECTION OUTPUT ;
    USE SIGNAL ;
    PORT
      LAYER M3 ;
        RECT  24.804 0 24.822 0.037 ;
    END
  END t_k[788]
  PIN t_k[789]
    DIRECTION OUTPUT ;
    USE SIGNAL ;
    PORT
      LAYER M3 ;
        RECT  24.876 0 24.894 0.037 ;
    END
  END t_k[789]
  PIN t_k[78]
    DIRECTION OUTPUT ;
    USE SIGNAL ;
    PORT
      LAYER M5 ;
        RECT  51.696 0 51.72 0.084 ;
    END
  END t_k[78]
  PIN t_k[790]
    DIRECTION OUTPUT ;
    USE SIGNAL ;
    PORT
      LAYER M3 ;
        RECT  24.948 0 24.966 0.037 ;
    END
  END t_k[790]
  PIN t_k[791]
    DIRECTION OUTPUT ;
    USE SIGNAL ;
    PORT
      LAYER M3 ;
        RECT  25.02 0 25.038 0.037 ;
    END
  END t_k[791]
  PIN t_k[79]
    DIRECTION OUTPUT ;
    USE SIGNAL ;
    PORT
      LAYER M5 ;
        RECT  51.792 0 51.816 0.084 ;
    END
  END t_k[79]
  PIN t_k[7]
    DIRECTION OUTPUT ;
    USE SIGNAL ;
    PORT
      LAYER M3 ;
        RECT  31.356 0 31.374 0.037 ;
    END
  END t_k[7]
  PIN t_k[80]
    DIRECTION OUTPUT ;
    USE SIGNAL ;
    PORT
      LAYER M5 ;
        RECT  51.888 0 51.912 0.084 ;
    END
  END t_k[80]
  PIN t_k[81]
    DIRECTION OUTPUT ;
    USE SIGNAL ;
    PORT
      LAYER M5 ;
        RECT  51.984 0 52.008 0.084 ;
    END
  END t_k[81]
  PIN t_k[82]
    DIRECTION OUTPUT ;
    USE SIGNAL ;
    PORT
      LAYER M5 ;
        RECT  52.08 0 52.104 0.084 ;
    END
  END t_k[82]
  PIN t_k[83]
    DIRECTION OUTPUT ;
    USE SIGNAL ;
    PORT
      LAYER M5 ;
        RECT  52.176 0 52.2 0.084 ;
    END
  END t_k[83]
  PIN t_k[84]
    DIRECTION OUTPUT ;
    USE SIGNAL ;
    PORT
      LAYER M5 ;
        RECT  52.272 0 52.296 0.084 ;
    END
  END t_k[84]
  PIN t_k[85]
    DIRECTION OUTPUT ;
    USE SIGNAL ;
    PORT
      LAYER M5 ;
        RECT  52.368 0 52.392 0.084 ;
    END
  END t_k[85]
  PIN t_k[86]
    DIRECTION OUTPUT ;
    USE SIGNAL ;
    PORT
      LAYER M5 ;
        RECT  52.464 0 52.488 0.084 ;
    END
  END t_k[86]
  PIN t_k[87]
    DIRECTION OUTPUT ;
    USE SIGNAL ;
    PORT
      LAYER M5 ;
        RECT  52.56 0 52.584 0.084 ;
    END
  END t_k[87]
  PIN t_k[88]
    DIRECTION OUTPUT ;
    USE SIGNAL ;
    PORT
      LAYER M5 ;
        RECT  52.656 0 52.68 0.084 ;
    END
  END t_k[88]
  PIN t_k[89]
    DIRECTION OUTPUT ;
    USE SIGNAL ;
    PORT
      LAYER M5 ;
        RECT  52.752 0 52.776 0.084 ;
    END
  END t_k[89]
  PIN t_k[8]
    DIRECTION OUTPUT ;
    USE SIGNAL ;
    PORT
      LAYER M3 ;
        RECT  31.428 0 31.446 0.037 ;
    END
  END t_k[8]
  PIN t_k[90]
    DIRECTION OUTPUT ;
    USE SIGNAL ;
    PORT
      LAYER M5 ;
        RECT  52.848 0 52.872 0.084 ;
    END
  END t_k[90]
  PIN t_k[91]
    DIRECTION OUTPUT ;
    USE SIGNAL ;
    PORT
      LAYER M5 ;
        RECT  52.944 0 52.968 0.084 ;
    END
  END t_k[91]
  PIN t_k[92]
    DIRECTION OUTPUT ;
    USE SIGNAL ;
    PORT
      LAYER M5 ;
        RECT  53.04 0 53.064 0.084 ;
    END
  END t_k[92]
  PIN t_k[93]
    DIRECTION OUTPUT ;
    USE SIGNAL ;
    PORT
      LAYER M5 ;
        RECT  53.136 0 53.16 0.084 ;
    END
  END t_k[93]
  PIN t_k[94]
    DIRECTION OUTPUT ;
    USE SIGNAL ;
    PORT
      LAYER M5 ;
        RECT  53.232 0 53.256 0.084 ;
    END
  END t_k[94]
  PIN t_k[95]
    DIRECTION OUTPUT ;
    USE SIGNAL ;
    PORT
      LAYER M5 ;
        RECT  53.328 0 53.352 0.084 ;
    END
  END t_k[95]
  PIN t_k[96]
    DIRECTION OUTPUT ;
    USE SIGNAL ;
    PORT
      LAYER M5 ;
        RECT  53.424 0 53.448 0.084 ;
    END
  END t_k[96]
  PIN t_k[97]
    DIRECTION OUTPUT ;
    USE SIGNAL ;
    PORT
      LAYER M5 ;
        RECT  53.52 0 53.544 0.084 ;
    END
  END t_k[97]
  PIN t_k[98]
    DIRECTION OUTPUT ;
    USE SIGNAL ;
    PORT
      LAYER M5 ;
        RECT  53.616 0 53.64 0.084 ;
    END
  END t_k[98]
  PIN t_k[99]
    DIRECTION OUTPUT ;
    USE SIGNAL ;
    PORT
      LAYER M5 ;
        RECT  53.712 0 53.736 0.084 ;
    END
  END t_k[99]
  PIN t_k[9]
    DIRECTION OUTPUT ;
    USE SIGNAL ;
    PORT
      LAYER M3 ;
        RECT  31.5 0 31.518 0.037 ;
    END
  END t_k[9]
  PIN t_sn[0]
    DIRECTION OUTPUT ;
    USE SIGNAL ;
    PORT
      LAYER M3 ;
        RECT  25.092 0 25.11 0.037 ;
    END
  END t_sn[0]
  PIN t_sn[10]
    DIRECTION OUTPUT ;
    USE SIGNAL ;
    PORT
      LAYER M3 ;
        RECT  25.812 0 25.83 0.037 ;
    END
  END t_sn[10]
  PIN t_sn[11]
    DIRECTION OUTPUT ;
    USE SIGNAL ;
    PORT
      LAYER M3 ;
        RECT  25.884 0 25.902 0.037 ;
    END
  END t_sn[11]
  PIN t_sn[12]
    DIRECTION OUTPUT ;
    USE SIGNAL ;
    PORT
      LAYER M3 ;
        RECT  25.956 0 25.974 0.037 ;
    END
  END t_sn[12]
  PIN t_sn[13]
    DIRECTION OUTPUT ;
    USE SIGNAL ;
    PORT
      LAYER M3 ;
        RECT  26.028 0 26.046 0.037 ;
    END
  END t_sn[13]
  PIN t_sn[14]
    DIRECTION OUTPUT ;
    USE SIGNAL ;
    PORT
      LAYER M3 ;
        RECT  26.1 0 26.118 0.037 ;
    END
  END t_sn[14]
  PIN t_sn[15]
    DIRECTION OUTPUT ;
    USE SIGNAL ;
    PORT
      LAYER M3 ;
        RECT  26.172 0 26.19 0.037 ;
    END
  END t_sn[15]
  PIN t_sn[16]
    DIRECTION OUTPUT ;
    USE SIGNAL ;
    PORT
      LAYER M3 ;
        RECT  26.244 0 26.262 0.037 ;
    END
  END t_sn[16]
  PIN t_sn[17]
    DIRECTION OUTPUT ;
    USE SIGNAL ;
    PORT
      LAYER M3 ;
        RECT  26.316 0 26.334 0.037 ;
    END
  END t_sn[17]
  PIN t_sn[18]
    DIRECTION OUTPUT ;
    USE SIGNAL ;
    PORT
      LAYER M3 ;
        RECT  26.388 0 26.406 0.037 ;
    END
  END t_sn[18]
  PIN t_sn[19]
    DIRECTION OUTPUT ;
    USE SIGNAL ;
    PORT
      LAYER M3 ;
        RECT  26.46 0 26.478 0.037 ;
    END
  END t_sn[19]
  PIN t_sn[1]
    DIRECTION OUTPUT ;
    USE SIGNAL ;
    PORT
      LAYER M3 ;
        RECT  25.164 0 25.182 0.037 ;
    END
  END t_sn[1]
  PIN t_sn[20]
    DIRECTION OUTPUT ;
    USE SIGNAL ;
    PORT
      LAYER M3 ;
        RECT  26.532 0 26.55 0.037 ;
    END
  END t_sn[20]
  PIN t_sn[21]
    DIRECTION OUTPUT ;
    USE SIGNAL ;
    PORT
      LAYER M3 ;
        RECT  26.604 0 26.622 0.037 ;
    END
  END t_sn[21]
  PIN t_sn[22]
    DIRECTION OUTPUT ;
    USE SIGNAL ;
    PORT
      LAYER M3 ;
        RECT  26.676 0 26.694 0.037 ;
    END
  END t_sn[22]
  PIN t_sn[23]
    DIRECTION OUTPUT ;
    USE SIGNAL ;
    PORT
      LAYER M3 ;
        RECT  26.748 0 26.766 0.037 ;
    END
  END t_sn[23]
  PIN t_sn[24]
    DIRECTION OUTPUT ;
    USE SIGNAL ;
    PORT
      LAYER M3 ;
        RECT  26.82 0 26.838 0.037 ;
    END
  END t_sn[24]
  PIN t_sn[25]
    DIRECTION OUTPUT ;
    USE SIGNAL ;
    PORT
      LAYER M3 ;
        RECT  26.892 0 26.91 0.037 ;
    END
  END t_sn[25]
  PIN t_sn[26]
    DIRECTION OUTPUT ;
    USE SIGNAL ;
    PORT
      LAYER M3 ;
        RECT  26.964 0 26.982 0.037 ;
    END
  END t_sn[26]
  PIN t_sn[27]
    DIRECTION OUTPUT ;
    USE SIGNAL ;
    PORT
      LAYER M3 ;
        RECT  27.036 0 27.054 0.037 ;
    END
  END t_sn[27]
  PIN t_sn[28]
    DIRECTION OUTPUT ;
    USE SIGNAL ;
    PORT
      LAYER M3 ;
        RECT  27.108 0 27.126 0.037 ;
    END
  END t_sn[28]
  PIN t_sn[29]
    DIRECTION OUTPUT ;
    USE SIGNAL ;
    PORT
      LAYER M3 ;
        RECT  27.18 0 27.198 0.037 ;
    END
  END t_sn[29]
  PIN t_sn[2]
    DIRECTION OUTPUT ;
    USE SIGNAL ;
    PORT
      LAYER M3 ;
        RECT  25.236 0 25.254 0.037 ;
    END
  END t_sn[2]
  PIN t_sn[30]
    DIRECTION OUTPUT ;
    USE SIGNAL ;
    PORT
      LAYER M3 ;
        RECT  27.252 0 27.27 0.037 ;
    END
  END t_sn[30]
  PIN t_sn[31]
    DIRECTION OUTPUT ;
    USE SIGNAL ;
    PORT
      LAYER M3 ;
        RECT  27.324 0 27.342 0.037 ;
    END
  END t_sn[31]
  PIN t_sn[32]
    DIRECTION OUTPUT ;
    USE SIGNAL ;
    PORT
      LAYER M3 ;
        RECT  27.396 0 27.414 0.037 ;
    END
  END t_sn[32]
  PIN t_sn[33]
    DIRECTION OUTPUT ;
    USE SIGNAL ;
    PORT
      LAYER M3 ;
        RECT  27.468 0 27.486 0.037 ;
    END
  END t_sn[33]
  PIN t_sn[34]
    DIRECTION OUTPUT ;
    USE SIGNAL ;
    PORT
      LAYER M3 ;
        RECT  27.54 0 27.558 0.037 ;
    END
  END t_sn[34]
  PIN t_sn[35]
    DIRECTION OUTPUT ;
    USE SIGNAL ;
    PORT
      LAYER M3 ;
        RECT  27.612 0 27.63 0.037 ;
    END
  END t_sn[35]
  PIN t_sn[36]
    DIRECTION OUTPUT ;
    USE SIGNAL ;
    PORT
      LAYER M3 ;
        RECT  27.684 0 27.702 0.037 ;
    END
  END t_sn[36]
  PIN t_sn[37]
    DIRECTION OUTPUT ;
    USE SIGNAL ;
    PORT
      LAYER M3 ;
        RECT  27.756 0 27.774 0.037 ;
    END
  END t_sn[37]
  PIN t_sn[38]
    DIRECTION OUTPUT ;
    USE SIGNAL ;
    PORT
      LAYER M3 ;
        RECT  27.828 0 27.846 0.037 ;
    END
  END t_sn[38]
  PIN t_sn[39]
    DIRECTION OUTPUT ;
    USE SIGNAL ;
    PORT
      LAYER M3 ;
        RECT  27.9 0 27.918 0.037 ;
    END
  END t_sn[39]
  PIN t_sn[3]
    DIRECTION OUTPUT ;
    USE SIGNAL ;
    PORT
      LAYER M3 ;
        RECT  25.308 0 25.326 0.037 ;
    END
  END t_sn[3]
  PIN t_sn[40]
    DIRECTION OUTPUT ;
    USE SIGNAL ;
    PORT
      LAYER M3 ;
        RECT  27.972 0 27.99 0.037 ;
    END
  END t_sn[40]
  PIN t_sn[41]
    DIRECTION OUTPUT ;
    USE SIGNAL ;
    PORT
      LAYER M3 ;
        RECT  28.044 0 28.062 0.037 ;
    END
  END t_sn[41]
  PIN t_sn[42]
    DIRECTION OUTPUT ;
    USE SIGNAL ;
    PORT
      LAYER M3 ;
        RECT  28.116 0 28.134 0.037 ;
    END
  END t_sn[42]
  PIN t_sn[43]
    DIRECTION OUTPUT ;
    USE SIGNAL ;
    PORT
      LAYER M3 ;
        RECT  28.188 0 28.206 0.037 ;
    END
  END t_sn[43]
  PIN t_sn[44]
    DIRECTION OUTPUT ;
    USE SIGNAL ;
    PORT
      LAYER M3 ;
        RECT  28.26 0 28.278 0.037 ;
    END
  END t_sn[44]
  PIN t_sn[45]
    DIRECTION OUTPUT ;
    USE SIGNAL ;
    PORT
      LAYER M3 ;
        RECT  28.332 0 28.35 0.037 ;
    END
  END t_sn[45]
  PIN t_sn[46]
    DIRECTION OUTPUT ;
    USE SIGNAL ;
    PORT
      LAYER M3 ;
        RECT  28.404 0 28.422 0.037 ;
    END
  END t_sn[46]
  PIN t_sn[47]
    DIRECTION OUTPUT ;
    USE SIGNAL ;
    PORT
      LAYER M3 ;
        RECT  28.476 0 28.494 0.037 ;
    END
  END t_sn[47]
  PIN t_sn[48]
    DIRECTION OUTPUT ;
    USE SIGNAL ;
    PORT
      LAYER M3 ;
        RECT  28.548 0 28.566 0.037 ;
    END
  END t_sn[48]
  PIN t_sn[49]
    DIRECTION OUTPUT ;
    USE SIGNAL ;
    PORT
      LAYER M3 ;
        RECT  28.62 0 28.638 0.037 ;
    END
  END t_sn[49]
  PIN t_sn[4]
    DIRECTION OUTPUT ;
    USE SIGNAL ;
    PORT
      LAYER M3 ;
        RECT  25.38 0 25.398 0.037 ;
    END
  END t_sn[4]
  PIN t_sn[50]
    DIRECTION OUTPUT ;
    USE SIGNAL ;
    PORT
      LAYER M3 ;
        RECT  28.692 0 28.71 0.037 ;
    END
  END t_sn[50]
  PIN t_sn[51]
    DIRECTION OUTPUT ;
    USE SIGNAL ;
    PORT
      LAYER M3 ;
        RECT  21.852 0 21.87 0.037 ;
    END
  END t_sn[51]
  PIN t_sn[52]
    DIRECTION OUTPUT ;
    USE SIGNAL ;
    PORT
      LAYER M3 ;
        RECT  21.924 0 21.942 0.037 ;
    END
  END t_sn[52]
  PIN t_sn[53]
    DIRECTION OUTPUT ;
    USE SIGNAL ;
    PORT
      LAYER M3 ;
        RECT  21.996 0 22.014 0.037 ;
    END
  END t_sn[53]
  PIN t_sn[54]
    DIRECTION OUTPUT ;
    USE SIGNAL ;
    PORT
      LAYER M3 ;
        RECT  22.068 0 22.086 0.037 ;
    END
  END t_sn[54]
  PIN t_sn[55]
    DIRECTION OUTPUT ;
    USE SIGNAL ;
    PORT
      LAYER M3 ;
        RECT  22.14 0 22.158 0.037 ;
    END
  END t_sn[55]
  PIN t_sn[56]
    DIRECTION OUTPUT ;
    USE SIGNAL ;
    PORT
      LAYER M3 ;
        RECT  22.212 0 22.23 0.037 ;
    END
  END t_sn[56]
  PIN t_sn[57]
    DIRECTION OUTPUT ;
    USE SIGNAL ;
    PORT
      LAYER M3 ;
        RECT  22.284 0 22.302 0.037 ;
    END
  END t_sn[57]
  PIN t_sn[58]
    DIRECTION OUTPUT ;
    USE SIGNAL ;
    PORT
      LAYER M3 ;
        RECT  22.356 0 22.374 0.037 ;
    END
  END t_sn[58]
  PIN t_sn[59]
    DIRECTION OUTPUT ;
    USE SIGNAL ;
    PORT
      LAYER M3 ;
        RECT  22.428 0 22.446 0.037 ;
    END
  END t_sn[59]
  PIN t_sn[5]
    DIRECTION OUTPUT ;
    USE SIGNAL ;
    PORT
      LAYER M3 ;
        RECT  25.452 0 25.47 0.037 ;
    END
  END t_sn[5]
  PIN t_sn[60]
    DIRECTION OUTPUT ;
    USE SIGNAL ;
    PORT
      LAYER M3 ;
        RECT  22.5 0 22.518 0.037 ;
    END
  END t_sn[60]
  PIN t_sn[61]
    DIRECTION OUTPUT ;
    USE SIGNAL ;
    PORT
      LAYER M3 ;
        RECT  22.572 0 22.59 0.037 ;
    END
  END t_sn[61]
  PIN t_sn[62]
    DIRECTION OUTPUT ;
    USE SIGNAL ;
    PORT
      LAYER M3 ;
        RECT  22.644 0 22.662 0.037 ;
    END
  END t_sn[62]
  PIN t_sn[63]
    DIRECTION OUTPUT ;
    USE SIGNAL ;
    PORT
      LAYER M3 ;
        RECT  22.716 0 22.734 0.037 ;
    END
  END t_sn[63]
  PIN t_sn[6]
    DIRECTION OUTPUT ;
    USE SIGNAL ;
    PORT
      LAYER M3 ;
        RECT  25.524 0 25.542 0.037 ;
    END
  END t_sn[6]
  PIN t_sn[7]
    DIRECTION OUTPUT ;
    USE SIGNAL ;
    PORT
      LAYER M3 ;
        RECT  25.596 0 25.614 0.037 ;
    END
  END t_sn[7]
  PIN t_sn[8]
    DIRECTION OUTPUT ;
    USE SIGNAL ;
    PORT
      LAYER M3 ;
        RECT  25.668 0 25.686 0.037 ;
    END
  END t_sn[8]
  PIN t_sn[9]
    DIRECTION OUTPUT ;
    USE SIGNAL ;
    PORT
      LAYER M3 ;
        RECT  25.74 0 25.758 0.037 ;
    END
  END t_sn[9]
  PIN VDD
    DIRECTION INOUT ;
    USE POWER ;
    PORT
      LAYER M5 ;
        RECT  83.592 2.151 83.712 321.849 ;
        RECT  78.192 2.151 78.312 321.849 ;
        RECT  72.792 2.151 72.912 321.849 ;
        RECT  67.392 2.151 67.512 321.849 ;
        RECT  61.992 2.151 62.112 321.849 ;
        RECT  56.592 2.151 56.712 321.849 ;
        RECT  51.192 2.151 51.312 321.849 ;
        RECT  45.792 2.151 45.912 321.849 ;
        RECT  40.392 2.151 40.512 321.849 ;
        RECT  34.992 2.151 35.112 321.849 ;
        RECT  29.592 2.151 29.712 321.849 ;
        RECT  24.192 2.151 24.312 321.849 ;
        RECT  18.792 2.151 18.912 321.849 ;
        RECT  13.392 2.151 13.512 321.849 ;
        RECT  7.992 2.151 8.112 321.849 ;
        RECT  2.592 2.151 2.712 321.849 ;
    END
  END VDD
  PIN VSS
    DIRECTION INOUT ;
    USE GROUND ;
    PORT
      LAYER M5 ;
        RECT  83.4 2.137 83.52 321.863 ;
        RECT  78 2.137 78.12 321.863 ;
        RECT  72.6 2.137 72.72 321.863 ;
        RECT  67.2 2.137 67.32 321.863 ;
        RECT  61.8 2.137 61.92 321.863 ;
        RECT  56.4 2.137 56.52 321.863 ;
        RECT  51 2.137 51.12 321.863 ;
        RECT  45.6 2.137 45.72 321.863 ;
        RECT  40.2 2.137 40.32 321.863 ;
        RECT  34.8 2.137 34.92 321.863 ;
        RECT  29.4 2.137 29.52 321.863 ;
        RECT  24 2.137 24.12 321.863 ;
        RECT  18.6 2.137 18.72 321.863 ;
        RECT  13.2 2.137 13.32 321.863 ;
        RECT  7.8 2.137 7.92 321.863 ;
        RECT  2.4 2.137 2.52 321.863 ;
    END
  END VSS
  OBS
    LAYER RVTN ;
     RECT  2.16 2.16 84.24 2.295 ;
     RECT  2.16 2.565 84.24 2.835 ;
     RECT  2.16 3.105 84.24 3.375 ;
     RECT  2.16 3.645 84.24 3.915 ;
     RECT  2.16 4.185 84.24 4.455 ;
     RECT  2.16 4.725 84.24 4.995 ;
     RECT  2.16 5.265 84.24 5.535 ;
     RECT  2.16 5.805 84.24 6.075 ;
     RECT  2.16 6.345 84.24 6.615 ;
     RECT  2.16 6.885 84.24 7.155 ;
     RECT  2.16 7.425 84.24 7.695 ;
     RECT  2.16 7.965 84.24 8.235 ;
     RECT  2.16 8.505 84.24 8.775 ;
     RECT  2.16 9.045 84.24 9.315 ;
     RECT  2.16 9.585 84.24 9.855 ;
     RECT  2.16 10.125 84.24 10.395 ;
     RECT  2.16 10.665 84.24 10.935 ;
     RECT  2.16 11.205 84.24 11.475 ;
     RECT  2.16 11.745 84.24 12.015 ;
     RECT  2.16 12.285 84.24 12.555 ;
     RECT  2.16 12.825 84.24 13.095 ;
     RECT  2.16 13.365 84.24 13.635 ;
     RECT  2.16 13.905 84.24 14.175 ;
     RECT  2.16 14.445 84.24 14.715 ;
     RECT  2.16 14.985 84.24 15.255 ;
     RECT  2.16 15.525 84.24 15.795 ;
     RECT  2.16 16.065 84.24 16.335 ;
     RECT  2.16 16.605 84.24 16.875 ;
     RECT  2.16 17.145 84.24 17.415 ;
     RECT  2.16 17.685 84.24 17.955 ;
     RECT  2.16 18.225 84.24 18.495 ;
     RECT  2.16 18.765 84.24 19.035 ;
     RECT  2.16 19.305 84.24 19.575 ;
     RECT  2.16 19.845 84.24 20.115 ;
     RECT  2.16 20.385 84.24 20.655 ;
     RECT  2.16 20.925 84.24 21.195 ;
     RECT  2.16 21.465 84.24 21.735 ;
     RECT  2.16 22.005 84.24 22.275 ;
     RECT  2.16 22.545 84.24 22.815 ;
     RECT  2.16 23.085 84.24 23.355 ;
     RECT  2.16 23.625 84.24 23.895 ;
     RECT  2.16 24.165 84.24 24.435 ;
     RECT  2.16 24.705 84.24 24.975 ;
     RECT  2.16 25.245 84.24 25.515 ;
     RECT  2.16 25.785 84.24 26.055 ;
     RECT  2.16 26.325 84.24 26.595 ;
     RECT  2.16 26.865 84.24 27.135 ;
     RECT  2.16 27.405 84.24 27.675 ;
     RECT  2.16 27.945 84.24 28.215 ;
     RECT  2.16 28.485 84.24 28.755 ;
     RECT  2.16 29.025 84.24 29.295 ;
     RECT  2.16 29.565 84.24 29.835 ;
     RECT  2.16 30.105 84.24 30.375 ;
     RECT  2.16 30.645 84.24 30.915 ;
     RECT  2.16 31.185 84.24 31.455 ;
     RECT  2.16 31.725 84.24 31.995 ;
     RECT  2.16 32.265 84.24 32.535 ;
     RECT  2.16 32.805 84.24 33.075 ;
     RECT  2.16 33.345 84.24 33.615 ;
     RECT  2.16 33.885 84.24 34.155 ;
     RECT  2.16 34.425 84.24 34.695 ;
     RECT  2.16 34.965 84.24 35.235 ;
     RECT  2.16 35.505 84.24 35.775 ;
     RECT  2.16 36.045 84.24 36.315 ;
     RECT  2.16 36.585 84.24 36.855 ;
     RECT  2.16 37.125 84.24 37.395 ;
     RECT  2.16 37.665 84.24 37.935 ;
     RECT  2.16 38.205 84.24 38.475 ;
     RECT  2.16 38.745 84.24 39.015 ;
     RECT  2.16 39.285 84.24 39.555 ;
     RECT  2.16 39.825 84.24 40.095 ;
     RECT  2.16 40.365 84.24 40.635 ;
     RECT  2.16 40.905 84.24 41.175 ;
     RECT  2.16 41.445 84.24 41.715 ;
     RECT  2.16 41.985 84.24 42.255 ;
     RECT  2.16 42.525 84.24 42.795 ;
     RECT  2.16 43.065 84.24 43.335 ;
     RECT  2.16 43.605 84.24 43.875 ;
     RECT  2.16 44.145 84.24 44.415 ;
     RECT  2.16 44.685 84.24 44.955 ;
     RECT  2.16 45.225 84.24 45.495 ;
     RECT  2.16 45.765 84.24 46.035 ;
     RECT  2.16 46.305 84.24 46.575 ;
     RECT  2.16 46.845 84.24 47.115 ;
     RECT  2.16 47.385 84.24 47.655 ;
     RECT  2.16 47.925 84.24 48.195 ;
     RECT  2.16 48.465 84.24 48.735 ;
     RECT  2.16 49.005 84.24 49.275 ;
     RECT  2.16 49.545 84.24 49.815 ;
     RECT  2.16 50.085 84.24 50.355 ;
     RECT  2.16 50.625 84.24 50.895 ;
     RECT  2.16 51.165 84.24 51.435 ;
     RECT  2.16 51.705 84.24 51.975 ;
     RECT  2.16 52.245 84.24 52.515 ;
     RECT  2.16 52.785 84.24 53.055 ;
     RECT  2.16 53.325 84.24 53.595 ;
     RECT  2.16 53.865 84.24 54.135 ;
     RECT  2.16 54.405 84.24 54.675 ;
     RECT  2.16 54.945 84.24 55.215 ;
     RECT  2.16 55.485 84.24 55.755 ;
     RECT  2.16 56.025 84.24 56.295 ;
     RECT  2.16 56.565 84.24 56.835 ;
     RECT  2.16 57.105 84.24 57.375 ;
     RECT  2.16 57.645 84.24 57.915 ;
     RECT  2.16 58.185 84.24 58.455 ;
     RECT  2.16 58.725 84.24 58.995 ;
     RECT  2.16 59.265 84.24 59.535 ;
     RECT  2.16 59.805 84.24 60.075 ;
     RECT  2.16 60.345 84.24 60.615 ;
     RECT  2.16 60.885 84.24 61.155 ;
     RECT  2.16 61.425 84.24 61.695 ;
     RECT  2.16 61.965 84.24 62.235 ;
     RECT  2.16 62.505 84.24 62.775 ;
     RECT  2.16 63.045 84.24 63.315 ;
     RECT  2.16 63.585 84.24 63.855 ;
     RECT  2.16 64.125 84.24 64.395 ;
     RECT  2.16 64.665 84.24 64.935 ;
     RECT  2.16 65.205 84.24 65.475 ;
     RECT  2.16 65.745 84.24 66.015 ;
     RECT  2.16 66.285 84.24 66.555 ;
     RECT  2.16 66.825 84.24 67.095 ;
     RECT  2.16 67.365 84.24 67.635 ;
     RECT  2.16 67.905 84.24 68.175 ;
     RECT  2.16 68.445 84.24 68.715 ;
     RECT  2.16 68.985 84.24 69.255 ;
     RECT  2.16 69.525 84.24 69.795 ;
     RECT  2.16 70.065 84.24 70.335 ;
     RECT  2.16 70.605 84.24 70.875 ;
     RECT  2.16 71.145 84.24 71.415 ;
     RECT  2.16 71.685 84.24 71.955 ;
     RECT  2.16 72.225 84.24 72.495 ;
     RECT  2.16 72.765 84.24 73.035 ;
     RECT  2.16 73.305 84.24 73.575 ;
     RECT  2.16 73.845 84.24 74.115 ;
     RECT  2.16 74.385 84.24 74.655 ;
     RECT  2.16 74.925 84.24 75.195 ;
     RECT  2.16 75.465 84.24 75.735 ;
     RECT  2.16 76.005 84.24 76.275 ;
     RECT  2.16 76.545 84.24 76.815 ;
     RECT  2.16 77.085 84.24 77.355 ;
     RECT  2.16 77.625 84.24 77.895 ;
     RECT  2.16 78.165 84.24 78.435 ;
     RECT  2.16 78.705 84.24 78.975 ;
     RECT  2.16 79.245 84.24 79.515 ;
     RECT  2.16 79.785 84.24 80.055 ;
     RECT  2.16 80.325 84.24 80.595 ;
     RECT  2.16 80.865 84.24 81.135 ;
     RECT  2.16 81.405 84.24 81.675 ;
     RECT  2.16 81.945 84.24 82.215 ;
     RECT  2.16 82.485 84.24 82.755 ;
     RECT  2.16 83.025 84.24 83.295 ;
     RECT  2.16 83.565 84.24 83.835 ;
     RECT  2.16 84.105 84.24 84.375 ;
     RECT  2.16 84.645 84.24 84.915 ;
     RECT  2.16 85.185 84.24 85.455 ;
     RECT  2.16 85.725 84.24 85.995 ;
     RECT  2.16 86.265 84.24 86.535 ;
     RECT  2.16 86.805 84.24 87.075 ;
     RECT  2.16 87.345 84.24 87.615 ;
     RECT  2.16 87.885 84.24 88.155 ;
     RECT  2.16 88.425 84.24 88.695 ;
     RECT  2.16 88.965 84.24 89.235 ;
     RECT  2.16 89.505 84.24 89.775 ;
     RECT  2.16 90.045 84.24 90.315 ;
     RECT  2.16 90.585 84.24 90.855 ;
     RECT  2.16 91.125 84.24 91.395 ;
     RECT  2.16 91.665 84.24 91.935 ;
     RECT  2.16 92.205 84.24 92.475 ;
     RECT  2.16 92.745 84.24 93.015 ;
     RECT  2.16 93.285 84.24 93.555 ;
     RECT  2.16 93.825 84.24 94.095 ;
     RECT  2.16 94.365 84.24 94.635 ;
     RECT  2.16 94.905 84.24 95.175 ;
     RECT  2.16 95.445 84.24 95.715 ;
     RECT  2.16 95.985 84.24 96.255 ;
     RECT  2.16 96.525 84.24 96.795 ;
     RECT  2.16 97.065 84.24 97.335 ;
     RECT  2.16 97.605 84.24 97.875 ;
     RECT  2.16 98.145 84.24 98.415 ;
     RECT  2.16 98.685 84.24 98.955 ;
     RECT  2.16 99.225 84.24 99.495 ;
     RECT  2.16 99.765 84.24 100.035 ;
     RECT  2.16 100.305 84.24 100.575 ;
     RECT  2.16 100.845 84.24 101.115 ;
     RECT  2.16 101.385 84.24 101.655 ;
     RECT  2.16 101.925 84.24 102.195 ;
     RECT  2.16 102.465 84.24 102.735 ;
     RECT  2.16 103.005 84.24 103.275 ;
     RECT  2.16 103.545 84.24 103.815 ;
     RECT  2.16 104.085 84.24 104.355 ;
     RECT  2.16 104.625 84.24 104.895 ;
     RECT  2.16 105.165 84.24 105.435 ;
     RECT  2.16 105.705 84.24 105.975 ;
     RECT  2.16 106.245 84.24 106.515 ;
     RECT  2.16 106.785 84.24 107.055 ;
     RECT  2.16 107.325 84.24 107.595 ;
     RECT  2.16 107.865 84.24 108.135 ;
     RECT  2.16 108.405 84.24 108.675 ;
     RECT  2.16 108.945 84.24 109.215 ;
     RECT  2.16 109.485 84.24 109.755 ;
     RECT  2.16 110.025 84.24 110.295 ;
     RECT  2.16 110.565 84.24 110.835 ;
     RECT  2.16 111.105 84.24 111.375 ;
     RECT  2.16 111.645 84.24 111.915 ;
     RECT  2.16 112.185 84.24 112.455 ;
     RECT  2.16 112.725 84.24 112.995 ;
     RECT  2.16 113.265 84.24 113.535 ;
     RECT  2.16 113.805 84.24 114.075 ;
     RECT  2.16 114.345 84.24 114.615 ;
     RECT  2.16 114.885 84.24 115.155 ;
     RECT  2.16 115.425 84.24 115.695 ;
     RECT  2.16 115.965 84.24 116.235 ;
     RECT  2.16 116.505 84.24 116.775 ;
     RECT  2.16 117.045 84.24 117.315 ;
     RECT  2.16 117.585 84.24 117.855 ;
     RECT  2.16 118.125 84.24 118.395 ;
     RECT  2.16 118.665 84.24 118.935 ;
     RECT  2.16 119.205 84.24 119.475 ;
     RECT  2.16 119.745 84.24 120.015 ;
     RECT  2.16 120.285 84.24 120.555 ;
     RECT  2.16 120.825 84.24 121.095 ;
     RECT  2.16 121.365 84.24 121.635 ;
     RECT  2.16 121.905 84.24 122.175 ;
     RECT  2.16 122.445 84.24 122.715 ;
     RECT  2.16 122.985 84.24 123.255 ;
     RECT  2.16 123.525 84.24 123.795 ;
     RECT  2.16 124.065 84.24 124.335 ;
     RECT  2.16 124.605 84.24 124.875 ;
     RECT  2.16 125.145 84.24 125.415 ;
     RECT  2.16 125.685 84.24 125.955 ;
     RECT  2.16 126.225 84.24 126.495 ;
     RECT  2.16 126.765 84.24 127.035 ;
     RECT  2.16 127.305 84.24 127.575 ;
     RECT  2.16 127.845 84.24 128.115 ;
     RECT  2.16 128.385 84.24 128.655 ;
     RECT  2.16 128.925 84.24 129.195 ;
     RECT  2.16 129.465 84.24 129.735 ;
     RECT  2.16 130.005 84.24 130.275 ;
     RECT  2.16 130.545 84.24 130.815 ;
     RECT  2.16 131.085 84.24 131.355 ;
     RECT  2.16 131.625 84.24 131.895 ;
     RECT  2.16 132.165 84.24 132.435 ;
     RECT  2.16 132.705 84.24 132.975 ;
     RECT  2.16 133.245 84.24 133.515 ;
     RECT  2.16 133.785 84.24 134.055 ;
     RECT  2.16 134.325 84.24 134.595 ;
     RECT  2.16 134.865 84.24 135.135 ;
     RECT  2.16 135.405 84.24 135.675 ;
     RECT  2.16 135.945 84.24 136.215 ;
     RECT  2.16 136.485 84.24 136.755 ;
     RECT  2.16 137.025 84.24 137.295 ;
     RECT  2.16 137.565 84.24 137.835 ;
     RECT  2.16 138.105 84.24 138.375 ;
     RECT  2.16 138.645 84.24 138.915 ;
     RECT  2.16 139.185 84.24 139.455 ;
     RECT  2.16 139.725 84.24 139.995 ;
     RECT  2.16 140.265 84.24 140.535 ;
     RECT  2.16 140.805 84.24 141.075 ;
     RECT  2.16 141.345 84.24 141.615 ;
     RECT  2.16 141.885 84.24 142.155 ;
     RECT  2.16 142.425 84.24 142.695 ;
     RECT  2.16 142.965 84.24 143.235 ;
     RECT  2.16 143.505 84.24 143.775 ;
     RECT  2.16 144.045 84.24 144.315 ;
     RECT  2.16 144.585 84.24 144.855 ;
     RECT  2.16 145.125 84.24 145.395 ;
     RECT  2.16 145.665 84.24 145.935 ;
     RECT  2.16 146.205 84.24 146.475 ;
     RECT  2.16 146.745 84.24 147.015 ;
     RECT  2.16 147.285 84.24 147.555 ;
     RECT  2.16 147.825 84.24 148.095 ;
     RECT  2.16 148.365 84.24 148.635 ;
     RECT  2.16 148.905 84.24 149.175 ;
     RECT  2.16 149.445 84.24 149.715 ;
     RECT  2.16 149.985 84.24 150.255 ;
     RECT  2.16 150.525 84.24 150.795 ;
     RECT  2.16 151.065 84.24 151.335 ;
     RECT  2.16 151.605 84.24 151.875 ;
     RECT  2.16 152.145 84.24 152.415 ;
     RECT  2.16 152.685 84.24 152.955 ;
     RECT  2.16 153.225 84.24 153.495 ;
     RECT  2.16 153.765 84.24 154.035 ;
     RECT  2.16 154.305 84.24 154.575 ;
     RECT  2.16 154.845 84.24 155.115 ;
     RECT  2.16 155.385 84.24 155.655 ;
     RECT  2.16 155.925 84.24 156.195 ;
     RECT  2.16 156.465 84.24 156.735 ;
     RECT  2.16 157.005 84.24 157.275 ;
     RECT  2.16 157.545 84.24 157.815 ;
     RECT  2.16 158.085 84.24 158.355 ;
     RECT  2.16 158.625 84.24 158.895 ;
     RECT  2.16 159.165 84.24 159.435 ;
     RECT  2.16 159.705 84.24 159.975 ;
     RECT  2.16 160.245 84.24 160.515 ;
     RECT  2.16 160.785 84.24 161.055 ;
     RECT  2.16 161.325 84.24 161.595 ;
     RECT  2.16 161.865 84.24 162.135 ;
     RECT  2.16 162.405 84.24 162.675 ;
     RECT  2.16 162.945 84.24 163.215 ;
     RECT  2.16 163.485 84.24 163.755 ;
     RECT  2.16 164.025 84.24 164.295 ;
     RECT  2.16 164.565 84.24 164.835 ;
     RECT  2.16 165.105 84.24 165.375 ;
     RECT  2.16 165.645 84.24 165.915 ;
     RECT  2.16 166.185 84.24 166.455 ;
     RECT  2.16 166.725 84.24 166.995 ;
     RECT  2.16 167.265 84.24 167.535 ;
     RECT  2.16 167.805 84.24 168.075 ;
     RECT  2.16 168.345 84.24 168.615 ;
     RECT  2.16 168.885 84.24 169.155 ;
     RECT  2.16 169.425 84.24 169.695 ;
     RECT  2.16 169.965 84.24 170.235 ;
     RECT  2.16 170.505 84.24 170.775 ;
     RECT  2.16 171.045 84.24 171.315 ;
     RECT  2.16 171.585 84.24 171.855 ;
     RECT  2.16 172.125 84.24 172.395 ;
     RECT  2.16 172.665 84.24 172.935 ;
     RECT  2.16 173.205 84.24 173.475 ;
     RECT  2.16 173.745 84.24 174.015 ;
     RECT  2.16 174.285 84.24 174.555 ;
     RECT  2.16 174.825 84.24 175.095 ;
     RECT  2.16 175.365 84.24 175.635 ;
     RECT  2.16 175.905 84.24 176.175 ;
     RECT  2.16 176.445 84.24 176.715 ;
     RECT  2.16 176.985 84.24 177.255 ;
     RECT  2.16 177.525 84.24 177.795 ;
     RECT  2.16 178.065 84.24 178.335 ;
     RECT  2.16 178.605 84.24 178.875 ;
     RECT  2.16 179.145 84.24 179.415 ;
     RECT  2.16 179.685 84.24 179.955 ;
     RECT  2.16 180.225 84.24 180.495 ;
     RECT  2.16 180.765 84.24 181.035 ;
     RECT  2.16 181.305 84.24 181.575 ;
     RECT  2.16 181.845 84.24 182.115 ;
     RECT  2.16 182.385 84.24 182.655 ;
     RECT  2.16 182.925 84.24 183.195 ;
     RECT  2.16 183.465 84.24 183.735 ;
     RECT  2.16 184.005 84.24 184.275 ;
     RECT  2.16 184.545 84.24 184.815 ;
     RECT  2.16 185.085 84.24 185.355 ;
     RECT  2.16 185.625 84.24 185.895 ;
     RECT  2.16 186.165 84.24 186.435 ;
     RECT  2.16 186.705 84.24 186.975 ;
     RECT  2.16 187.245 84.24 187.515 ;
     RECT  2.16 187.785 84.24 188.055 ;
     RECT  2.16 188.325 84.24 188.595 ;
     RECT  2.16 188.865 84.24 189.135 ;
     RECT  2.16 189.405 84.24 189.675 ;
     RECT  2.16 189.945 84.24 190.215 ;
     RECT  2.16 190.485 84.24 190.755 ;
     RECT  2.16 191.025 84.24 191.295 ;
     RECT  2.16 191.565 84.24 191.835 ;
     RECT  2.16 192.105 84.24 192.375 ;
     RECT  2.16 192.645 84.24 192.915 ;
     RECT  2.16 193.185 84.24 193.455 ;
     RECT  2.16 193.725 84.24 193.995 ;
     RECT  2.16 194.265 84.24 194.535 ;
     RECT  2.16 194.805 84.24 195.075 ;
     RECT  2.16 195.345 84.24 195.615 ;
     RECT  2.16 195.885 84.24 196.155 ;
     RECT  2.16 196.425 84.24 196.695 ;
     RECT  2.16 196.965 84.24 197.235 ;
     RECT  2.16 197.505 84.24 197.775 ;
     RECT  2.16 198.045 84.24 198.315 ;
     RECT  2.16 198.585 84.24 198.855 ;
     RECT  2.16 199.125 84.24 199.395 ;
     RECT  2.16 199.665 84.24 199.935 ;
     RECT  2.16 200.205 84.24 200.475 ;
     RECT  2.16 200.745 84.24 201.015 ;
     RECT  2.16 201.285 84.24 201.555 ;
     RECT  2.16 201.825 84.24 202.095 ;
     RECT  2.16 202.365 84.24 202.635 ;
     RECT  2.16 202.905 84.24 203.175 ;
     RECT  2.16 203.445 84.24 203.715 ;
     RECT  2.16 203.985 84.24 204.255 ;
     RECT  2.16 204.525 84.24 204.795 ;
     RECT  2.16 205.065 84.24 205.335 ;
     RECT  2.16 205.605 84.24 205.875 ;
     RECT  2.16 206.145 84.24 206.415 ;
     RECT  2.16 206.685 84.24 206.955 ;
     RECT  2.16 207.225 84.24 207.495 ;
     RECT  2.16 207.765 84.24 208.035 ;
     RECT  2.16 208.305 84.24 208.575 ;
     RECT  2.16 208.845 84.24 209.115 ;
     RECT  2.16 209.385 84.24 209.655 ;
     RECT  2.16 209.925 84.24 210.195 ;
     RECT  2.16 210.465 84.24 210.735 ;
     RECT  2.16 211.005 84.24 211.275 ;
     RECT  2.16 211.545 84.24 211.815 ;
     RECT  2.16 212.085 84.24 212.355 ;
     RECT  2.16 212.625 84.24 212.895 ;
     RECT  2.16 213.165 84.24 213.435 ;
     RECT  2.16 213.705 84.24 213.975 ;
     RECT  2.16 214.245 84.24 214.515 ;
     RECT  2.16 214.785 84.24 215.055 ;
     RECT  2.16 215.325 84.24 215.595 ;
     RECT  2.16 215.865 84.24 216.135 ;
     RECT  2.16 216.405 84.24 216.675 ;
     RECT  2.16 216.945 84.24 217.215 ;
     RECT  2.16 217.485 84.24 217.755 ;
     RECT  2.16 218.025 84.24 218.295 ;
     RECT  2.16 218.565 84.24 218.835 ;
     RECT  2.16 219.105 84.24 219.375 ;
     RECT  2.16 219.645 84.24 219.915 ;
     RECT  2.16 220.185 84.24 220.455 ;
     RECT  2.16 220.725 84.24 220.995 ;
     RECT  2.16 221.265 84.24 221.535 ;
     RECT  2.16 221.805 84.24 222.075 ;
     RECT  2.16 222.345 84.24 222.615 ;
     RECT  2.16 222.885 84.24 223.155 ;
     RECT  2.16 223.425 84.24 223.695 ;
     RECT  2.16 223.965 84.24 224.235 ;
     RECT  2.16 224.505 84.24 224.775 ;
     RECT  2.16 225.045 84.24 225.315 ;
     RECT  2.16 225.585 84.24 225.855 ;
     RECT  2.16 226.125 84.24 226.395 ;
     RECT  2.16 226.665 84.24 226.935 ;
     RECT  2.16 227.205 84.24 227.475 ;
     RECT  2.16 227.745 84.24 228.015 ;
     RECT  2.16 228.285 84.24 228.555 ;
     RECT  2.16 228.825 84.24 229.095 ;
     RECT  2.16 229.365 84.24 229.635 ;
     RECT  2.16 229.905 84.24 230.175 ;
     RECT  2.16 230.445 84.24 230.715 ;
     RECT  2.16 230.985 84.24 231.255 ;
     RECT  2.16 231.525 84.24 231.795 ;
     RECT  2.16 232.065 84.24 232.335 ;
     RECT  2.16 232.605 84.24 232.875 ;
     RECT  2.16 233.145 84.24 233.415 ;
     RECT  2.16 233.685 84.24 233.955 ;
     RECT  2.16 234.225 84.24 234.495 ;
     RECT  2.16 234.765 84.24 235.035 ;
     RECT  2.16 235.305 84.24 235.575 ;
     RECT  2.16 235.845 84.24 236.115 ;
     RECT  2.16 236.385 84.24 236.655 ;
     RECT  2.16 236.925 84.24 237.195 ;
     RECT  2.16 237.465 84.24 237.735 ;
     RECT  2.16 238.005 84.24 238.275 ;
     RECT  2.16 238.545 84.24 238.815 ;
     RECT  2.16 239.085 84.24 239.355 ;
     RECT  2.16 239.625 84.24 239.895 ;
     RECT  2.16 240.165 84.24 240.435 ;
     RECT  2.16 240.705 84.24 240.975 ;
     RECT  2.16 241.245 84.24 241.515 ;
     RECT  2.16 241.785 84.24 242.055 ;
     RECT  2.16 242.325 84.24 242.595 ;
     RECT  2.16 242.865 84.24 243.135 ;
     RECT  2.16 243.405 84.24 243.675 ;
     RECT  2.16 243.945 84.24 244.215 ;
     RECT  2.16 244.485 84.24 244.755 ;
     RECT  2.16 245.025 84.24 245.295 ;
     RECT  2.16 245.565 84.24 245.835 ;
     RECT  2.16 246.105 84.24 246.375 ;
     RECT  2.16 246.645 84.24 246.915 ;
     RECT  2.16 247.185 84.24 247.455 ;
     RECT  2.16 247.725 84.24 247.995 ;
     RECT  2.16 248.265 84.24 248.535 ;
     RECT  2.16 248.805 84.24 249.075 ;
     RECT  2.16 249.345 84.24 249.615 ;
     RECT  2.16 249.885 84.24 250.155 ;
     RECT  2.16 250.425 84.24 250.695 ;
     RECT  2.16 250.965 84.24 251.235 ;
     RECT  2.16 251.505 84.24 251.775 ;
     RECT  2.16 252.045 84.24 252.315 ;
     RECT  2.16 252.585 84.24 252.855 ;
     RECT  2.16 253.125 84.24 253.395 ;
     RECT  2.16 253.665 84.24 253.935 ;
     RECT  2.16 254.205 84.24 254.475 ;
     RECT  2.16 254.745 84.24 255.015 ;
     RECT  2.16 255.285 84.24 255.555 ;
     RECT  2.16 255.825 84.24 256.095 ;
     RECT  2.16 256.365 84.24 256.635 ;
     RECT  2.16 256.905 84.24 257.175 ;
     RECT  2.16 257.445 84.24 257.715 ;
     RECT  2.16 257.985 84.24 258.255 ;
     RECT  2.16 258.525 84.24 258.795 ;
     RECT  2.16 259.065 84.24 259.335 ;
     RECT  2.16 259.605 84.24 259.875 ;
     RECT  2.16 260.145 84.24 260.415 ;
     RECT  2.16 260.685 84.24 260.955 ;
     RECT  2.16 261.225 84.24 261.495 ;
     RECT  2.16 261.765 84.24 262.035 ;
     RECT  2.16 262.305 84.24 262.575 ;
     RECT  2.16 262.845 84.24 263.115 ;
     RECT  2.16 263.385 84.24 263.655 ;
     RECT  2.16 263.925 84.24 264.195 ;
     RECT  2.16 264.465 84.24 264.735 ;
     RECT  2.16 265.005 84.24 265.275 ;
     RECT  2.16 265.545 84.24 265.815 ;
     RECT  2.16 266.085 84.24 266.355 ;
     RECT  2.16 266.625 84.24 266.895 ;
     RECT  2.16 267.165 84.24 267.435 ;
     RECT  2.16 267.705 84.24 267.975 ;
     RECT  2.16 268.245 84.24 268.515 ;
     RECT  2.16 268.785 84.24 269.055 ;
     RECT  2.16 269.325 84.24 269.595 ;
     RECT  2.16 269.865 84.24 270.135 ;
     RECT  2.16 270.405 84.24 270.675 ;
     RECT  2.16 270.945 84.24 271.215 ;
     RECT  2.16 271.485 84.24 271.755 ;
     RECT  2.16 272.025 84.24 272.295 ;
     RECT  2.16 272.565 84.24 272.835 ;
     RECT  2.16 273.105 84.24 273.375 ;
     RECT  2.16 273.645 84.24 273.915 ;
     RECT  2.16 274.185 84.24 274.455 ;
     RECT  2.16 274.725 84.24 274.995 ;
     RECT  2.16 275.265 84.24 275.535 ;
     RECT  2.16 275.805 84.24 276.075 ;
     RECT  2.16 276.345 84.24 276.615 ;
     RECT  2.16 276.885 84.24 277.155 ;
     RECT  2.16 277.425 84.24 277.695 ;
     RECT  2.16 277.965 84.24 278.235 ;
     RECT  2.16 278.505 84.24 278.775 ;
     RECT  2.16 279.045 84.24 279.315 ;
     RECT  2.16 279.585 84.24 279.855 ;
     RECT  2.16 280.125 84.24 280.395 ;
     RECT  2.16 280.665 84.24 280.935 ;
     RECT  2.16 281.205 84.24 281.475 ;
     RECT  2.16 281.745 84.24 282.015 ;
     RECT  2.16 282.285 84.24 282.555 ;
     RECT  2.16 282.825 84.24 283.095 ;
     RECT  2.16 283.365 84.24 283.635 ;
     RECT  2.16 283.905 84.24 284.175 ;
     RECT  2.16 284.445 84.24 284.715 ;
     RECT  2.16 284.985 84.24 285.255 ;
     RECT  2.16 285.525 84.24 285.795 ;
     RECT  2.16 286.065 84.24 286.335 ;
     RECT  2.16 286.605 84.24 286.875 ;
     RECT  2.16 287.145 84.24 287.415 ;
     RECT  2.16 287.685 84.24 287.955 ;
     RECT  2.16 288.225 84.24 288.495 ;
     RECT  2.16 288.765 84.24 289.035 ;
     RECT  2.16 289.305 84.24 289.575 ;
     RECT  2.16 289.845 84.24 290.115 ;
     RECT  2.16 290.385 84.24 290.655 ;
     RECT  2.16 290.925 84.24 291.195 ;
     RECT  2.16 291.465 84.24 291.735 ;
     RECT  2.16 292.005 84.24 292.275 ;
     RECT  2.16 292.545 84.24 292.815 ;
     RECT  2.16 293.085 84.24 293.355 ;
     RECT  2.16 293.625 84.24 293.895 ;
     RECT  2.16 294.165 84.24 294.435 ;
     RECT  2.16 294.705 84.24 294.975 ;
     RECT  2.16 295.245 84.24 295.515 ;
     RECT  2.16 295.785 84.24 296.055 ;
     RECT  2.16 296.325 84.24 296.595 ;
     RECT  2.16 296.865 84.24 297.135 ;
     RECT  2.16 297.405 84.24 297.675 ;
     RECT  2.16 297.945 84.24 298.215 ;
     RECT  2.16 298.485 84.24 298.755 ;
     RECT  2.16 299.025 84.24 299.295 ;
     RECT  2.16 299.565 84.24 299.835 ;
     RECT  2.16 300.105 84.24 300.375 ;
     RECT  2.16 300.645 84.24 300.915 ;
     RECT  2.16 301.185 84.24 301.455 ;
     RECT  2.16 301.725 84.24 301.995 ;
     RECT  2.16 302.265 84.24 302.535 ;
     RECT  2.16 302.805 84.24 303.075 ;
     RECT  2.16 303.345 84.24 303.615 ;
     RECT  2.16 303.885 84.24 304.155 ;
     RECT  2.16 304.425 84.24 304.695 ;
     RECT  2.16 304.965 84.24 305.235 ;
     RECT  2.16 305.505 84.24 305.775 ;
     RECT  2.16 306.045 84.24 306.315 ;
     RECT  2.16 306.585 84.24 306.855 ;
     RECT  2.16 307.125 84.24 307.395 ;
     RECT  2.16 307.665 84.24 307.935 ;
     RECT  2.16 308.205 84.24 308.475 ;
     RECT  2.16 308.745 84.24 309.015 ;
     RECT  2.16 309.285 84.24 309.555 ;
     RECT  2.16 309.825 84.24 310.095 ;
     RECT  2.16 310.365 84.24 310.635 ;
     RECT  2.16 310.905 84.24 311.175 ;
     RECT  2.16 311.445 84.24 311.715 ;
     RECT  2.16 311.985 84.24 312.255 ;
     RECT  2.16 312.525 84.24 312.795 ;
     RECT  2.16 313.065 84.24 313.335 ;
     RECT  2.16 313.605 84.24 313.875 ;
     RECT  2.16 314.145 84.24 314.415 ;
     RECT  2.16 314.685 84.24 314.955 ;
     RECT  2.16 315.225 84.24 315.495 ;
     RECT  2.16 315.765 84.24 316.035 ;
     RECT  2.16 316.305 84.24 316.575 ;
     RECT  2.16 316.845 84.24 317.115 ;
     RECT  2.16 317.385 84.24 317.655 ;
     RECT  2.16 317.925 84.24 318.195 ;
     RECT  2.16 318.465 84.24 318.735 ;
     RECT  2.16 319.005 84.24 319.275 ;
     RECT  2.16 319.545 84.24 319.815 ;
     RECT  2.16 320.085 84.24 320.355 ;
     RECT  2.16 320.625 84.24 320.895 ;
     RECT  2.16 321.165 84.24 321.435 ;
     RECT  2.16 321.705 84.24 321.84 ;
    LAYER RVTP ;
     RECT  2.16 2.295 84.24 2.565 ;
     RECT  2.16 2.835 84.24 3.105 ;
     RECT  2.16 3.375 84.24 3.645 ;
     RECT  2.16 3.915 84.24 4.185 ;
     RECT  2.16 4.455 84.24 4.725 ;
     RECT  2.16 4.995 84.24 5.265 ;
     RECT  2.16 5.535 84.24 5.805 ;
     RECT  2.16 6.075 84.24 6.345 ;
     RECT  2.16 6.615 84.24 6.885 ;
     RECT  2.16 7.155 84.24 7.425 ;
     RECT  2.16 7.695 84.24 7.965 ;
     RECT  2.16 8.235 84.24 8.505 ;
     RECT  2.16 8.775 84.24 9.045 ;
     RECT  2.16 9.315 84.24 9.585 ;
     RECT  2.16 9.855 84.24 10.125 ;
     RECT  2.16 10.395 84.24 10.665 ;
     RECT  2.16 10.935 84.24 11.205 ;
     RECT  2.16 11.475 84.24 11.745 ;
     RECT  2.16 12.015 84.24 12.285 ;
     RECT  2.16 12.555 84.24 12.825 ;
     RECT  2.16 13.095 84.24 13.365 ;
     RECT  2.16 13.635 84.24 13.905 ;
     RECT  2.16 14.175 84.24 14.445 ;
     RECT  2.16 14.715 84.24 14.985 ;
     RECT  2.16 15.255 84.24 15.525 ;
     RECT  2.16 15.795 84.24 16.065 ;
     RECT  2.16 16.335 84.24 16.605 ;
     RECT  2.16 16.875 84.24 17.145 ;
     RECT  2.16 17.415 84.24 17.685 ;
     RECT  2.16 17.955 84.24 18.225 ;
     RECT  2.16 18.495 84.24 18.765 ;
     RECT  2.16 19.035 84.24 19.305 ;
     RECT  2.16 19.575 84.24 19.845 ;
     RECT  2.16 20.115 84.24 20.385 ;
     RECT  2.16 20.655 84.24 20.925 ;
     RECT  2.16 21.195 84.24 21.465 ;
     RECT  2.16 21.735 84.24 22.005 ;
     RECT  2.16 22.275 84.24 22.545 ;
     RECT  2.16 22.815 84.24 23.085 ;
     RECT  2.16 23.355 84.24 23.625 ;
     RECT  2.16 23.895 84.24 24.165 ;
     RECT  2.16 24.435 84.24 24.705 ;
     RECT  2.16 24.975 84.24 25.245 ;
     RECT  2.16 25.515 84.24 25.785 ;
     RECT  2.16 26.055 84.24 26.325 ;
     RECT  2.16 26.595 84.24 26.865 ;
     RECT  2.16 27.135 84.24 27.405 ;
     RECT  2.16 27.675 84.24 27.945 ;
     RECT  2.16 28.215 84.24 28.485 ;
     RECT  2.16 28.755 84.24 29.025 ;
     RECT  2.16 29.295 84.24 29.565 ;
     RECT  2.16 29.835 84.24 30.105 ;
     RECT  2.16 30.375 84.24 30.645 ;
     RECT  2.16 30.915 84.24 31.185 ;
     RECT  2.16 31.455 84.24 31.725 ;
     RECT  2.16 31.995 84.24 32.265 ;
     RECT  2.16 32.535 84.24 32.805 ;
     RECT  2.16 33.075 84.24 33.345 ;
     RECT  2.16 33.615 84.24 33.885 ;
     RECT  2.16 34.155 84.24 34.425 ;
     RECT  2.16 34.695 84.24 34.965 ;
     RECT  2.16 35.235 84.24 35.505 ;
     RECT  2.16 35.775 84.24 36.045 ;
     RECT  2.16 36.315 84.24 36.585 ;
     RECT  2.16 36.855 84.24 37.125 ;
     RECT  2.16 37.395 84.24 37.665 ;
     RECT  2.16 37.935 84.24 38.205 ;
     RECT  2.16 38.475 84.24 38.745 ;
     RECT  2.16 39.015 84.24 39.285 ;
     RECT  2.16 39.555 84.24 39.825 ;
     RECT  2.16 40.095 84.24 40.365 ;
     RECT  2.16 40.635 84.24 40.905 ;
     RECT  2.16 41.175 84.24 41.445 ;
     RECT  2.16 41.715 84.24 41.985 ;
     RECT  2.16 42.255 84.24 42.525 ;
     RECT  2.16 42.795 84.24 43.065 ;
     RECT  2.16 43.335 84.24 43.605 ;
     RECT  2.16 43.875 84.24 44.145 ;
     RECT  2.16 44.415 84.24 44.685 ;
     RECT  2.16 44.955 84.24 45.225 ;
     RECT  2.16 45.495 84.24 45.765 ;
     RECT  2.16 46.035 84.24 46.305 ;
     RECT  2.16 46.575 84.24 46.845 ;
     RECT  2.16 47.115 84.24 47.385 ;
     RECT  2.16 47.655 84.24 47.925 ;
     RECT  2.16 48.195 84.24 48.465 ;
     RECT  2.16 48.735 84.24 49.005 ;
     RECT  2.16 49.275 84.24 49.545 ;
     RECT  2.16 49.815 84.24 50.085 ;
     RECT  2.16 50.355 84.24 50.625 ;
     RECT  2.16 50.895 84.24 51.165 ;
     RECT  2.16 51.435 84.24 51.705 ;
     RECT  2.16 51.975 84.24 52.245 ;
     RECT  2.16 52.515 84.24 52.785 ;
     RECT  2.16 53.055 84.24 53.325 ;
     RECT  2.16 53.595 84.24 53.865 ;
     RECT  2.16 54.135 84.24 54.405 ;
     RECT  2.16 54.675 84.24 54.945 ;
     RECT  2.16 55.215 84.24 55.485 ;
     RECT  2.16 55.755 84.24 56.025 ;
     RECT  2.16 56.295 84.24 56.565 ;
     RECT  2.16 56.835 84.24 57.105 ;
     RECT  2.16 57.375 84.24 57.645 ;
     RECT  2.16 57.915 84.24 58.185 ;
     RECT  2.16 58.455 84.24 58.725 ;
     RECT  2.16 58.995 84.24 59.265 ;
     RECT  2.16 59.535 84.24 59.805 ;
     RECT  2.16 60.075 84.24 60.345 ;
     RECT  2.16 60.615 84.24 60.885 ;
     RECT  2.16 61.155 84.24 61.425 ;
     RECT  2.16 61.695 84.24 61.965 ;
     RECT  2.16 62.235 84.24 62.505 ;
     RECT  2.16 62.775 84.24 63.045 ;
     RECT  2.16 63.315 84.24 63.585 ;
     RECT  2.16 63.855 84.24 64.125 ;
     RECT  2.16 64.395 84.24 64.665 ;
     RECT  2.16 64.935 84.24 65.205 ;
     RECT  2.16 65.475 84.24 65.745 ;
     RECT  2.16 66.015 84.24 66.285 ;
     RECT  2.16 66.555 84.24 66.825 ;
     RECT  2.16 67.095 84.24 67.365 ;
     RECT  2.16 67.635 84.24 67.905 ;
     RECT  2.16 68.175 84.24 68.445 ;
     RECT  2.16 68.715 84.24 68.985 ;
     RECT  2.16 69.255 84.24 69.525 ;
     RECT  2.16 69.795 84.24 70.065 ;
     RECT  2.16 70.335 84.24 70.605 ;
     RECT  2.16 70.875 84.24 71.145 ;
     RECT  2.16 71.415 84.24 71.685 ;
     RECT  2.16 71.955 84.24 72.225 ;
     RECT  2.16 72.495 84.24 72.765 ;
     RECT  2.16 73.035 84.24 73.305 ;
     RECT  2.16 73.575 84.24 73.845 ;
     RECT  2.16 74.115 84.24 74.385 ;
     RECT  2.16 74.655 84.24 74.925 ;
     RECT  2.16 75.195 84.24 75.465 ;
     RECT  2.16 75.735 84.24 76.005 ;
     RECT  2.16 76.275 84.24 76.545 ;
     RECT  2.16 76.815 84.24 77.085 ;
     RECT  2.16 77.355 84.24 77.625 ;
     RECT  2.16 77.895 84.24 78.165 ;
     RECT  2.16 78.435 84.24 78.705 ;
     RECT  2.16 78.975 84.24 79.245 ;
     RECT  2.16 79.515 84.24 79.785 ;
     RECT  2.16 80.055 84.24 80.325 ;
     RECT  2.16 80.595 84.24 80.865 ;
     RECT  2.16 81.135 84.24 81.405 ;
     RECT  2.16 81.675 84.24 81.945 ;
     RECT  2.16 82.215 84.24 82.485 ;
     RECT  2.16 82.755 84.24 83.025 ;
     RECT  2.16 83.295 84.24 83.565 ;
     RECT  2.16 83.835 84.24 84.105 ;
     RECT  2.16 84.375 84.24 84.645 ;
     RECT  2.16 84.915 84.24 85.185 ;
     RECT  2.16 85.455 84.24 85.725 ;
     RECT  2.16 85.995 84.24 86.265 ;
     RECT  2.16 86.535 84.24 86.805 ;
     RECT  2.16 87.075 84.24 87.345 ;
     RECT  2.16 87.615 84.24 87.885 ;
     RECT  2.16 88.155 84.24 88.425 ;
     RECT  2.16 88.695 84.24 88.965 ;
     RECT  2.16 89.235 84.24 89.505 ;
     RECT  2.16 89.775 84.24 90.045 ;
     RECT  2.16 90.315 84.24 90.585 ;
     RECT  2.16 90.855 84.24 91.125 ;
     RECT  2.16 91.395 84.24 91.665 ;
     RECT  2.16 91.935 84.24 92.205 ;
     RECT  2.16 92.475 84.24 92.745 ;
     RECT  2.16 93.015 84.24 93.285 ;
     RECT  2.16 93.555 84.24 93.825 ;
     RECT  2.16 94.095 84.24 94.365 ;
     RECT  2.16 94.635 84.24 94.905 ;
     RECT  2.16 95.175 84.24 95.445 ;
     RECT  2.16 95.715 84.24 95.985 ;
     RECT  2.16 96.255 84.24 96.525 ;
     RECT  2.16 96.795 84.24 97.065 ;
     RECT  2.16 97.335 84.24 97.605 ;
     RECT  2.16 97.875 84.24 98.145 ;
     RECT  2.16 98.415 84.24 98.685 ;
     RECT  2.16 98.955 84.24 99.225 ;
     RECT  2.16 99.495 84.24 99.765 ;
     RECT  2.16 100.035 84.24 100.305 ;
     RECT  2.16 100.575 84.24 100.845 ;
     RECT  2.16 101.115 84.24 101.385 ;
     RECT  2.16 101.655 84.24 101.925 ;
     RECT  2.16 102.195 84.24 102.465 ;
     RECT  2.16 102.735 84.24 103.005 ;
     RECT  2.16 103.275 84.24 103.545 ;
     RECT  2.16 103.815 84.24 104.085 ;
     RECT  2.16 104.355 84.24 104.625 ;
     RECT  2.16 104.895 84.24 105.165 ;
     RECT  2.16 105.435 84.24 105.705 ;
     RECT  2.16 105.975 84.24 106.245 ;
     RECT  2.16 106.515 84.24 106.785 ;
     RECT  2.16 107.055 84.24 107.325 ;
     RECT  2.16 107.595 84.24 107.865 ;
     RECT  2.16 108.135 84.24 108.405 ;
     RECT  2.16 108.675 84.24 108.945 ;
     RECT  2.16 109.215 84.24 109.485 ;
     RECT  2.16 109.755 84.24 110.025 ;
     RECT  2.16 110.295 84.24 110.565 ;
     RECT  2.16 110.835 84.24 111.105 ;
     RECT  2.16 111.375 84.24 111.645 ;
     RECT  2.16 111.915 84.24 112.185 ;
     RECT  2.16 112.455 84.24 112.725 ;
     RECT  2.16 112.995 84.24 113.265 ;
     RECT  2.16 113.535 84.24 113.805 ;
     RECT  2.16 114.075 84.24 114.345 ;
     RECT  2.16 114.615 84.24 114.885 ;
     RECT  2.16 115.155 84.24 115.425 ;
     RECT  2.16 115.695 84.24 115.965 ;
     RECT  2.16 116.235 84.24 116.505 ;
     RECT  2.16 116.775 84.24 117.045 ;
     RECT  2.16 117.315 84.24 117.585 ;
     RECT  2.16 117.855 84.24 118.125 ;
     RECT  2.16 118.395 84.24 118.665 ;
     RECT  2.16 118.935 84.24 119.205 ;
     RECT  2.16 119.475 84.24 119.745 ;
     RECT  2.16 120.015 84.24 120.285 ;
     RECT  2.16 120.555 84.24 120.825 ;
     RECT  2.16 121.095 84.24 121.365 ;
     RECT  2.16 121.635 84.24 121.905 ;
     RECT  2.16 122.175 84.24 122.445 ;
     RECT  2.16 122.715 84.24 122.985 ;
     RECT  2.16 123.255 84.24 123.525 ;
     RECT  2.16 123.795 84.24 124.065 ;
     RECT  2.16 124.335 84.24 124.605 ;
     RECT  2.16 124.875 84.24 125.145 ;
     RECT  2.16 125.415 84.24 125.685 ;
     RECT  2.16 125.955 84.24 126.225 ;
     RECT  2.16 126.495 84.24 126.765 ;
     RECT  2.16 127.035 84.24 127.305 ;
     RECT  2.16 127.575 84.24 127.845 ;
     RECT  2.16 128.115 84.24 128.385 ;
     RECT  2.16 128.655 84.24 128.925 ;
     RECT  2.16 129.195 84.24 129.465 ;
     RECT  2.16 129.735 84.24 130.005 ;
     RECT  2.16 130.275 84.24 130.545 ;
     RECT  2.16 130.815 84.24 131.085 ;
     RECT  2.16 131.355 84.24 131.625 ;
     RECT  2.16 131.895 84.24 132.165 ;
     RECT  2.16 132.435 84.24 132.705 ;
     RECT  2.16 132.975 84.24 133.245 ;
     RECT  2.16 133.515 84.24 133.785 ;
     RECT  2.16 134.055 84.24 134.325 ;
     RECT  2.16 134.595 84.24 134.865 ;
     RECT  2.16 135.135 84.24 135.405 ;
     RECT  2.16 135.675 84.24 135.945 ;
     RECT  2.16 136.215 84.24 136.485 ;
     RECT  2.16 136.755 84.24 137.025 ;
     RECT  2.16 137.295 84.24 137.565 ;
     RECT  2.16 137.835 84.24 138.105 ;
     RECT  2.16 138.375 84.24 138.645 ;
     RECT  2.16 138.915 84.24 139.185 ;
     RECT  2.16 139.455 84.24 139.725 ;
     RECT  2.16 139.995 84.24 140.265 ;
     RECT  2.16 140.535 84.24 140.805 ;
     RECT  2.16 141.075 84.24 141.345 ;
     RECT  2.16 141.615 84.24 141.885 ;
     RECT  2.16 142.155 84.24 142.425 ;
     RECT  2.16 142.695 84.24 142.965 ;
     RECT  2.16 143.235 84.24 143.505 ;
     RECT  2.16 143.775 84.24 144.045 ;
     RECT  2.16 144.315 84.24 144.585 ;
     RECT  2.16 144.855 84.24 145.125 ;
     RECT  2.16 145.395 84.24 145.665 ;
     RECT  2.16 145.935 84.24 146.205 ;
     RECT  2.16 146.475 84.24 146.745 ;
     RECT  2.16 147.015 84.24 147.285 ;
     RECT  2.16 147.555 84.24 147.825 ;
     RECT  2.16 148.095 84.24 148.365 ;
     RECT  2.16 148.635 84.24 148.905 ;
     RECT  2.16 149.175 84.24 149.445 ;
     RECT  2.16 149.715 84.24 149.985 ;
     RECT  2.16 150.255 84.24 150.525 ;
     RECT  2.16 150.795 84.24 151.065 ;
     RECT  2.16 151.335 84.24 151.605 ;
     RECT  2.16 151.875 84.24 152.145 ;
     RECT  2.16 152.415 84.24 152.685 ;
     RECT  2.16 152.955 84.24 153.225 ;
     RECT  2.16 153.495 84.24 153.765 ;
     RECT  2.16 154.035 84.24 154.305 ;
     RECT  2.16 154.575 84.24 154.845 ;
     RECT  2.16 155.115 84.24 155.385 ;
     RECT  2.16 155.655 84.24 155.925 ;
     RECT  2.16 156.195 84.24 156.465 ;
     RECT  2.16 156.735 84.24 157.005 ;
     RECT  2.16 157.275 84.24 157.545 ;
     RECT  2.16 157.815 84.24 158.085 ;
     RECT  2.16 158.355 84.24 158.625 ;
     RECT  2.16 158.895 84.24 159.165 ;
     RECT  2.16 159.435 84.24 159.705 ;
     RECT  2.16 159.975 84.24 160.245 ;
     RECT  2.16 160.515 84.24 160.785 ;
     RECT  2.16 161.055 84.24 161.325 ;
     RECT  2.16 161.595 84.24 161.865 ;
     RECT  2.16 162.135 84.24 162.405 ;
     RECT  2.16 162.675 84.24 162.945 ;
     RECT  2.16 163.215 84.24 163.485 ;
     RECT  2.16 163.755 84.24 164.025 ;
     RECT  2.16 164.295 84.24 164.565 ;
     RECT  2.16 164.835 84.24 165.105 ;
     RECT  2.16 165.375 84.24 165.645 ;
     RECT  2.16 165.915 84.24 166.185 ;
     RECT  2.16 166.455 84.24 166.725 ;
     RECT  2.16 166.995 84.24 167.265 ;
     RECT  2.16 167.535 84.24 167.805 ;
     RECT  2.16 168.075 84.24 168.345 ;
     RECT  2.16 168.615 84.24 168.885 ;
     RECT  2.16 169.155 84.24 169.425 ;
     RECT  2.16 169.695 84.24 169.965 ;
     RECT  2.16 170.235 84.24 170.505 ;
     RECT  2.16 170.775 84.24 171.045 ;
     RECT  2.16 171.315 84.24 171.585 ;
     RECT  2.16 171.855 84.24 172.125 ;
     RECT  2.16 172.395 84.24 172.665 ;
     RECT  2.16 172.935 84.24 173.205 ;
     RECT  2.16 173.475 84.24 173.745 ;
     RECT  2.16 174.015 84.24 174.285 ;
     RECT  2.16 174.555 84.24 174.825 ;
     RECT  2.16 175.095 84.24 175.365 ;
     RECT  2.16 175.635 84.24 175.905 ;
     RECT  2.16 176.175 84.24 176.445 ;
     RECT  2.16 176.715 84.24 176.985 ;
     RECT  2.16 177.255 84.24 177.525 ;
     RECT  2.16 177.795 84.24 178.065 ;
     RECT  2.16 178.335 84.24 178.605 ;
     RECT  2.16 178.875 84.24 179.145 ;
     RECT  2.16 179.415 84.24 179.685 ;
     RECT  2.16 179.955 84.24 180.225 ;
     RECT  2.16 180.495 84.24 180.765 ;
     RECT  2.16 181.035 84.24 181.305 ;
     RECT  2.16 181.575 84.24 181.845 ;
     RECT  2.16 182.115 84.24 182.385 ;
     RECT  2.16 182.655 84.24 182.925 ;
     RECT  2.16 183.195 84.24 183.465 ;
     RECT  2.16 183.735 84.24 184.005 ;
     RECT  2.16 184.275 84.24 184.545 ;
     RECT  2.16 184.815 84.24 185.085 ;
     RECT  2.16 185.355 84.24 185.625 ;
     RECT  2.16 185.895 84.24 186.165 ;
     RECT  2.16 186.435 84.24 186.705 ;
     RECT  2.16 186.975 84.24 187.245 ;
     RECT  2.16 187.515 84.24 187.785 ;
     RECT  2.16 188.055 84.24 188.325 ;
     RECT  2.16 188.595 84.24 188.865 ;
     RECT  2.16 189.135 84.24 189.405 ;
     RECT  2.16 189.675 84.24 189.945 ;
     RECT  2.16 190.215 84.24 190.485 ;
     RECT  2.16 190.755 84.24 191.025 ;
     RECT  2.16 191.295 84.24 191.565 ;
     RECT  2.16 191.835 84.24 192.105 ;
     RECT  2.16 192.375 84.24 192.645 ;
     RECT  2.16 192.915 84.24 193.185 ;
     RECT  2.16 193.455 84.24 193.725 ;
     RECT  2.16 193.995 84.24 194.265 ;
     RECT  2.16 194.535 84.24 194.805 ;
     RECT  2.16 195.075 84.24 195.345 ;
     RECT  2.16 195.615 84.24 195.885 ;
     RECT  2.16 196.155 84.24 196.425 ;
     RECT  2.16 196.695 84.24 196.965 ;
     RECT  2.16 197.235 84.24 197.505 ;
     RECT  2.16 197.775 84.24 198.045 ;
     RECT  2.16 198.315 84.24 198.585 ;
     RECT  2.16 198.855 84.24 199.125 ;
     RECT  2.16 199.395 84.24 199.665 ;
     RECT  2.16 199.935 84.24 200.205 ;
     RECT  2.16 200.475 84.24 200.745 ;
     RECT  2.16 201.015 84.24 201.285 ;
     RECT  2.16 201.555 84.24 201.825 ;
     RECT  2.16 202.095 84.24 202.365 ;
     RECT  2.16 202.635 84.24 202.905 ;
     RECT  2.16 203.175 84.24 203.445 ;
     RECT  2.16 203.715 84.24 203.985 ;
     RECT  2.16 204.255 84.24 204.525 ;
     RECT  2.16 204.795 84.24 205.065 ;
     RECT  2.16 205.335 84.24 205.605 ;
     RECT  2.16 205.875 84.24 206.145 ;
     RECT  2.16 206.415 84.24 206.685 ;
     RECT  2.16 206.955 84.24 207.225 ;
     RECT  2.16 207.495 84.24 207.765 ;
     RECT  2.16 208.035 84.24 208.305 ;
     RECT  2.16 208.575 84.24 208.845 ;
     RECT  2.16 209.115 84.24 209.385 ;
     RECT  2.16 209.655 84.24 209.925 ;
     RECT  2.16 210.195 84.24 210.465 ;
     RECT  2.16 210.735 84.24 211.005 ;
     RECT  2.16 211.275 84.24 211.545 ;
     RECT  2.16 211.815 84.24 212.085 ;
     RECT  2.16 212.355 84.24 212.625 ;
     RECT  2.16 212.895 84.24 213.165 ;
     RECT  2.16 213.435 84.24 213.705 ;
     RECT  2.16 213.975 84.24 214.245 ;
     RECT  2.16 214.515 84.24 214.785 ;
     RECT  2.16 215.055 84.24 215.325 ;
     RECT  2.16 215.595 84.24 215.865 ;
     RECT  2.16 216.135 84.24 216.405 ;
     RECT  2.16 216.675 84.24 216.945 ;
     RECT  2.16 217.215 84.24 217.485 ;
     RECT  2.16 217.755 84.24 218.025 ;
     RECT  2.16 218.295 84.24 218.565 ;
     RECT  2.16 218.835 84.24 219.105 ;
     RECT  2.16 219.375 84.24 219.645 ;
     RECT  2.16 219.915 84.24 220.185 ;
     RECT  2.16 220.455 84.24 220.725 ;
     RECT  2.16 220.995 84.24 221.265 ;
     RECT  2.16 221.535 84.24 221.805 ;
     RECT  2.16 222.075 84.24 222.345 ;
     RECT  2.16 222.615 84.24 222.885 ;
     RECT  2.16 223.155 84.24 223.425 ;
     RECT  2.16 223.695 84.24 223.965 ;
     RECT  2.16 224.235 84.24 224.505 ;
     RECT  2.16 224.775 84.24 225.045 ;
     RECT  2.16 225.315 84.24 225.585 ;
     RECT  2.16 225.855 84.24 226.125 ;
     RECT  2.16 226.395 84.24 226.665 ;
     RECT  2.16 226.935 84.24 227.205 ;
     RECT  2.16 227.475 84.24 227.745 ;
     RECT  2.16 228.015 84.24 228.285 ;
     RECT  2.16 228.555 84.24 228.825 ;
     RECT  2.16 229.095 84.24 229.365 ;
     RECT  2.16 229.635 84.24 229.905 ;
     RECT  2.16 230.175 84.24 230.445 ;
     RECT  2.16 230.715 84.24 230.985 ;
     RECT  2.16 231.255 84.24 231.525 ;
     RECT  2.16 231.795 84.24 232.065 ;
     RECT  2.16 232.335 84.24 232.605 ;
     RECT  2.16 232.875 84.24 233.145 ;
     RECT  2.16 233.415 84.24 233.685 ;
     RECT  2.16 233.955 84.24 234.225 ;
     RECT  2.16 234.495 84.24 234.765 ;
     RECT  2.16 235.035 84.24 235.305 ;
     RECT  2.16 235.575 84.24 235.845 ;
     RECT  2.16 236.115 84.24 236.385 ;
     RECT  2.16 236.655 84.24 236.925 ;
     RECT  2.16 237.195 84.24 237.465 ;
     RECT  2.16 237.735 84.24 238.005 ;
     RECT  2.16 238.275 84.24 238.545 ;
     RECT  2.16 238.815 84.24 239.085 ;
     RECT  2.16 239.355 84.24 239.625 ;
     RECT  2.16 239.895 84.24 240.165 ;
     RECT  2.16 240.435 84.24 240.705 ;
     RECT  2.16 240.975 84.24 241.245 ;
     RECT  2.16 241.515 84.24 241.785 ;
     RECT  2.16 242.055 84.24 242.325 ;
     RECT  2.16 242.595 84.24 242.865 ;
     RECT  2.16 243.135 84.24 243.405 ;
     RECT  2.16 243.675 84.24 243.945 ;
     RECT  2.16 244.215 84.24 244.485 ;
     RECT  2.16 244.755 84.24 245.025 ;
     RECT  2.16 245.295 84.24 245.565 ;
     RECT  2.16 245.835 84.24 246.105 ;
     RECT  2.16 246.375 84.24 246.645 ;
     RECT  2.16 246.915 84.24 247.185 ;
     RECT  2.16 247.455 84.24 247.725 ;
     RECT  2.16 247.995 84.24 248.265 ;
     RECT  2.16 248.535 84.24 248.805 ;
     RECT  2.16 249.075 84.24 249.345 ;
     RECT  2.16 249.615 84.24 249.885 ;
     RECT  2.16 250.155 84.24 250.425 ;
     RECT  2.16 250.695 84.24 250.965 ;
     RECT  2.16 251.235 84.24 251.505 ;
     RECT  2.16 251.775 84.24 252.045 ;
     RECT  2.16 252.315 84.24 252.585 ;
     RECT  2.16 252.855 84.24 253.125 ;
     RECT  2.16 253.395 84.24 253.665 ;
     RECT  2.16 253.935 84.24 254.205 ;
     RECT  2.16 254.475 84.24 254.745 ;
     RECT  2.16 255.015 84.24 255.285 ;
     RECT  2.16 255.555 84.24 255.825 ;
     RECT  2.16 256.095 84.24 256.365 ;
     RECT  2.16 256.635 84.24 256.905 ;
     RECT  2.16 257.175 84.24 257.445 ;
     RECT  2.16 257.715 84.24 257.985 ;
     RECT  2.16 258.255 84.24 258.525 ;
     RECT  2.16 258.795 84.24 259.065 ;
     RECT  2.16 259.335 84.24 259.605 ;
     RECT  2.16 259.875 84.24 260.145 ;
     RECT  2.16 260.415 84.24 260.685 ;
     RECT  2.16 260.955 84.24 261.225 ;
     RECT  2.16 261.495 84.24 261.765 ;
     RECT  2.16 262.035 84.24 262.305 ;
     RECT  2.16 262.575 84.24 262.845 ;
     RECT  2.16 263.115 84.24 263.385 ;
     RECT  2.16 263.655 84.24 263.925 ;
     RECT  2.16 264.195 84.24 264.465 ;
     RECT  2.16 264.735 84.24 265.005 ;
     RECT  2.16 265.275 84.24 265.545 ;
     RECT  2.16 265.815 84.24 266.085 ;
     RECT  2.16 266.355 84.24 266.625 ;
     RECT  2.16 266.895 84.24 267.165 ;
     RECT  2.16 267.435 84.24 267.705 ;
     RECT  2.16 267.975 84.24 268.245 ;
     RECT  2.16 268.515 84.24 268.785 ;
     RECT  2.16 269.055 84.24 269.325 ;
     RECT  2.16 269.595 84.24 269.865 ;
     RECT  2.16 270.135 84.24 270.405 ;
     RECT  2.16 270.675 84.24 270.945 ;
     RECT  2.16 271.215 84.24 271.485 ;
     RECT  2.16 271.755 84.24 272.025 ;
     RECT  2.16 272.295 84.24 272.565 ;
     RECT  2.16 272.835 84.24 273.105 ;
     RECT  2.16 273.375 84.24 273.645 ;
     RECT  2.16 273.915 84.24 274.185 ;
     RECT  2.16 274.455 84.24 274.725 ;
     RECT  2.16 274.995 84.24 275.265 ;
     RECT  2.16 275.535 84.24 275.805 ;
     RECT  2.16 276.075 84.24 276.345 ;
     RECT  2.16 276.615 84.24 276.885 ;
     RECT  2.16 277.155 84.24 277.425 ;
     RECT  2.16 277.695 84.24 277.965 ;
     RECT  2.16 278.235 84.24 278.505 ;
     RECT  2.16 278.775 84.24 279.045 ;
     RECT  2.16 279.315 84.24 279.585 ;
     RECT  2.16 279.855 84.24 280.125 ;
     RECT  2.16 280.395 84.24 280.665 ;
     RECT  2.16 280.935 84.24 281.205 ;
     RECT  2.16 281.475 84.24 281.745 ;
     RECT  2.16 282.015 84.24 282.285 ;
     RECT  2.16 282.555 84.24 282.825 ;
     RECT  2.16 283.095 84.24 283.365 ;
     RECT  2.16 283.635 84.24 283.905 ;
     RECT  2.16 284.175 84.24 284.445 ;
     RECT  2.16 284.715 84.24 284.985 ;
     RECT  2.16 285.255 84.24 285.525 ;
     RECT  2.16 285.795 84.24 286.065 ;
     RECT  2.16 286.335 84.24 286.605 ;
     RECT  2.16 286.875 84.24 287.145 ;
     RECT  2.16 287.415 84.24 287.685 ;
     RECT  2.16 287.955 84.24 288.225 ;
     RECT  2.16 288.495 84.24 288.765 ;
     RECT  2.16 289.035 84.24 289.305 ;
     RECT  2.16 289.575 84.24 289.845 ;
     RECT  2.16 290.115 84.24 290.385 ;
     RECT  2.16 290.655 84.24 290.925 ;
     RECT  2.16 291.195 84.24 291.465 ;
     RECT  2.16 291.735 84.24 292.005 ;
     RECT  2.16 292.275 84.24 292.545 ;
     RECT  2.16 292.815 84.24 293.085 ;
     RECT  2.16 293.355 84.24 293.625 ;
     RECT  2.16 293.895 84.24 294.165 ;
     RECT  2.16 294.435 84.24 294.705 ;
     RECT  2.16 294.975 84.24 295.245 ;
     RECT  2.16 295.515 84.24 295.785 ;
     RECT  2.16 296.055 84.24 296.325 ;
     RECT  2.16 296.595 84.24 296.865 ;
     RECT  2.16 297.135 84.24 297.405 ;
     RECT  2.16 297.675 84.24 297.945 ;
     RECT  2.16 298.215 84.24 298.485 ;
     RECT  2.16 298.755 84.24 299.025 ;
     RECT  2.16 299.295 84.24 299.565 ;
     RECT  2.16 299.835 84.24 300.105 ;
     RECT  2.16 300.375 84.24 300.645 ;
     RECT  2.16 300.915 84.24 301.185 ;
     RECT  2.16 301.455 84.24 301.725 ;
     RECT  2.16 301.995 84.24 302.265 ;
     RECT  2.16 302.535 84.24 302.805 ;
     RECT  2.16 303.075 84.24 303.345 ;
     RECT  2.16 303.615 84.24 303.885 ;
     RECT  2.16 304.155 84.24 304.425 ;
     RECT  2.16 304.695 84.24 304.965 ;
     RECT  2.16 305.235 84.24 305.505 ;
     RECT  2.16 305.775 84.24 306.045 ;
     RECT  2.16 306.315 84.24 306.585 ;
     RECT  2.16 306.855 84.24 307.125 ;
     RECT  2.16 307.395 84.24 307.665 ;
     RECT  2.16 307.935 84.24 308.205 ;
     RECT  2.16 308.475 84.24 308.745 ;
     RECT  2.16 309.015 84.24 309.285 ;
     RECT  2.16 309.555 84.24 309.825 ;
     RECT  2.16 310.095 84.24 310.365 ;
     RECT  2.16 310.635 84.24 310.905 ;
     RECT  2.16 311.175 84.24 311.445 ;
     RECT  2.16 311.715 84.24 311.985 ;
     RECT  2.16 312.255 84.24 312.525 ;
     RECT  2.16 312.795 84.24 313.065 ;
     RECT  2.16 313.335 84.24 313.605 ;
     RECT  2.16 313.875 84.24 314.145 ;
     RECT  2.16 314.415 84.24 314.685 ;
     RECT  2.16 314.955 84.24 315.225 ;
     RECT  2.16 315.495 84.24 315.765 ;
     RECT  2.16 316.035 84.24 316.305 ;
     RECT  2.16 316.575 84.24 316.845 ;
     RECT  2.16 317.115 84.24 317.385 ;
     RECT  2.16 317.655 84.24 317.925 ;
     RECT  2.16 318.195 84.24 318.465 ;
     RECT  2.16 318.735 84.24 319.005 ;
     RECT  2.16 319.275 84.24 319.545 ;
     RECT  2.16 319.815 84.24 320.085 ;
     RECT  2.16 320.355 84.24 320.625 ;
     RECT  2.16 320.895 84.24 321.165 ;
     RECT  2.16 321.435 84.24 321.705 ;
    LAYER M1 ;
     RECT  2.16 2.151 84.24 321.849 ;
    LAYER M2 ;
     RECT  2.16 2.151 21.091 321.849 ;
     RECT  20.803 1.116 21.559 1.134 ;
     RECT  21.091 1.926 21.559 321.849 ;
     RECT  21.847 0.108 21.991 0.126 ;
     RECT  21.991 0.036 22.063 0.126 ;
     RECT  22.063 0.036 22.279 0.198 ;
     RECT  21.559 1.116 22.279 321.849 ;
     RECT  22.279 0.036 22.703 321.849 ;
     RECT  22.703 0.036 24.043 0.09 ;
     RECT  22.703 0.846 24.043 321.849 ;
     RECT  24.043 0.036 27.671 321.849 ;
     RECT  27.671 0.108 27.707 321.849 ;
     RECT  27.707 0.18 28.543 321.849 ;
     RECT  28.543 0.108 28.615 321.849 ;
     RECT  28.615 0.036 29.507 321.849 ;
     RECT  29.507 0.108 30.271 321.849 ;
     RECT  30.271 0.036 36.131 321.849 ;
     RECT  36.131 0.18 37.147 321.849 ;
     RECT  37.147 0.036 40.163 321.849 ;
     RECT  40.163 0.036 41.791 0.279 ;
     RECT  40.163 1.152 41.791 321.849 ;
     RECT  41.791 0.036 42.431 321.849 ;
     RECT  42.431 0.036 42.683 0.198 ;
     RECT  42.431 1.152 42.971 321.849 ;
     RECT  42.971 1.224 43.295 321.849 ;
     RECT  42.683 0.036 43.735 0.054 ;
     RECT  43.295 1.341 44.023 321.849 ;
     RECT  43.735 0.036 44.095 0.324 ;
     RECT  44.023 1.26 44.131 321.849 ;
     RECT  44.095 0.036 44.195 0.396 ;
     RECT  44.131 1.152 44.267 321.849 ;
     RECT  44.195 0.036 44.663 0.198 ;
     RECT  44.267 1.224 45.211 321.849 ;
     RECT  44.663 0.036 45.535 0.162 ;
     RECT  45.211 1.152 45.607 321.849 ;
     RECT  45.607 1.071 45.923 321.849 ;
     RECT  45.535 0.036 45.995 0.324 ;
     RECT  45.995 0.036 46.759 0.126 ;
     RECT  46.759 0.036 46.975 0.198 ;
     RECT  46.975 0.036 47.435 0.279 ;
     RECT  47.435 0.036 47.651 0.198 ;
     RECT  47.651 0.036 48.811 0.126 ;
     RECT  48.811 0.036 49.019 0.198 ;
     RECT  49.019 0.036 49.999 0.126 ;
     RECT  49.999 0.036 50.323 0.198 ;
     RECT  50.323 0.036 50.431 0.279 ;
     RECT  50.431 0.036 50.539 0.324 ;
     RECT  45.923 1.152 50.539 321.849 ;
     RECT  50.539 0.036 51.323 321.849 ;
     RECT  51.323 0.036 52.375 0.324 ;
     RECT  51.323 1.152 52.375 321.849 ;
     RECT  52.375 0.036 52.511 321.849 ;
     RECT  52.511 0.036 53.743 0.198 ;
     RECT  53.743 0.036 53.879 0.279 ;
     RECT  53.879 0.036 54.491 0.234 ;
     RECT  54.491 0.036 55.435 0.126 ;
     RECT  55.435 0.036 55.687 0.162 ;
     RECT  52.511 1.152 56.183 321.849 ;
     RECT  55.687 0.036 56.191 0.198 ;
     RECT  56.183 1.224 56.219 321.849 ;
     RECT  56.219 1.296 56.327 321.849 ;
     RECT  56.191 0.036 56.363 0.279 ;
     RECT  56.363 0.036 56.399 0.198 ;
     RECT  56.327 1.386 56.435 321.849 ;
     RECT  56.399 0.036 57.127 0.126 ;
     RECT  56.435 1.422 57.271 321.849 ;
     RECT  57.271 1.341 57.307 321.849 ;
     RECT  57.307 1.26 57.343 321.849 ;
     RECT  57.127 0.036 57.407 0.198 ;
     RECT  57.343 1.152 57.443 321.849 ;
     RECT  57.407 0.108 57.479 0.198 ;
     RECT  57.443 1.26 57.551 321.849 ;
     RECT  57.559 0.378 57.631 0.396 ;
     RECT  57.631 0.378 58.243 0.432 ;
     RECT  58.243 0.036 58.675 0.432 ;
     RECT  58.675 0.036 58.783 0.549 ;
     RECT  57.551 1.422 58.783 321.849 ;
     RECT  58.783 0.036 60.683 321.849 ;
     RECT  60.683 0.036 61.447 0.396 ;
     RECT  60.683 1.152 61.447 321.849 ;
     RECT  61.447 0.036 69.539 321.849 ;
     RECT  69.539 0.261 70.043 321.849 ;
     RECT  70.043 0.261 70.187 0.864 ;
     RECT  70.187 0.261 70.259 0.279 ;
     RECT  70.043 1.728 70.367 321.849 ;
     RECT  70.367 1.8 70.835 321.849 ;
     RECT  70.555 0.036 70.907 0.054 ;
     RECT  70.835 2.106 70.907 321.849 ;
     RECT  70.907 2.151 84.24 321.849 ;
    LAYER M3 ;
     RECT  21.852 0.012 22.734 0.067 ;
     RECT  21.852 0.067 22.986 0.091 ;
     RECT  24.156 0.012 71.91 0.091 ;
     RECT  21.564 0.091 22.986 0.139 ;
     RECT  21.564 0.139 23.058 0.427 ;
     RECT  23.868 0.091 71.91 0.427 ;
     RECT  20.124 0.571 20.142 0.619 ;
     RECT  20.124 0.619 20.322 1.111 ;
     RECT  20.124 1.111 20.826 1.243 ;
     RECT  21.564 0.427 71.91 1.243 ;
     RECT  20.124 1.243 71.91 1.723 ;
     RECT  19.908 1.723 71.91 2.143 ;
     RECT  2.415 2.143 2.505 2.413 ;
     RECT  7.815 2.143 7.905 2.413 ;
     RECT  13.215 2.143 13.305 2.413 ;
     RECT  18.615 2.143 18.705 2.413 ;
     RECT  19.908 2.143 72.705 2.413 ;
     RECT  78.015 2.143 78.105 2.413 ;
     RECT  83.415 2.143 83.505 2.413 ;
     RECT  19.908 2.413 72.897 2.633 ;
     RECT  19.908 2.633 71.766 2.803 ;
     RECT  19.836 2.803 71.766 2.903 ;
     RECT  19.836 2.903 71.694 2.939 ;
     RECT  20.016 2.939 71.694 3.299 ;
     RECT  69.3 3.299 71.406 3.371 ;
     RECT  20.016 3.299 68.526 3.407 ;
     RECT  20.844 3.407 68.526 3.437 ;
     RECT  20.88 3.437 68.382 3.443 ;
     RECT  71.388 3.371 71.406 3.479 ;
     RECT  20.88 3.443 68.166 3.569 ;
     RECT  20.016 3.407 20.034 3.581 ;
     RECT  20.88 3.569 58.626 3.605 ;
     RECT  69.3 3.371 69.966 3.641 ;
     RECT  58.464 3.605 58.626 3.713 ;
     RECT  58.464 3.713 58.482 3.821 ;
     RECT  59.544 3.569 68.166 3.839 ;
     RECT  59.544 3.839 65.43 3.875 ;
     RECT  69.552 3.641 69.966 3.875 ;
     RECT  59.832 3.875 65.43 3.911 ;
     RECT  69.552 3.875 69.93 3.947 ;
     RECT  20.88 3.605 57.438 3.983 ;
     RECT  59.832 3.911 64.746 3.983 ;
     RECT  66.888 3.839 68.166 3.983 ;
     RECT  59.832 3.983 64.458 4.013 ;
     RECT  60.948 4.013 64.458 4.019 ;
     RECT  69.804 3.947 69.93 4.019 ;
     RECT  61.524 4.019 64.458 4.109 ;
     RECT  69.804 4.019 69.822 4.109 ;
     RECT  61.815 4.109 64.458 4.145 ;
     RECT  20.88 3.983 57.402 4.157 ;
     RECT  59.832 4.013 59.85 4.157 ;
     RECT  66.888 3.983 67.497 4.157 ;
     RECT  20.88 4.157 57.15 4.397 ;
     RECT  61.815 4.145 64.422 4.685 ;
     RECT  61.815 4.685 63.882 4.721 ;
     RECT  20.88 4.397 56.898 4.765 ;
     RECT  63 4.721 63.882 4.793 ;
     RECT  63.864 4.793 63.882 4.829 ;
     RECT  20.772 4.765 56.898 4.991 ;
     RECT  63 4.793 63.126 5.021 ;
     RECT  63.108 5.021 63.126 5.027 ;
     RECT  20.772 4.991 55.638 5.063 ;
     RECT  56.415 4.991 56.898 5.063 ;
     RECT  55.368 5.063 55.638 5.333 ;
     RECT  55.62 5.333 55.638 5.369 ;
     RECT  20.772 5.063 54.45 6.143 ;
     RECT  20.772 6.143 40.806 6.845 ;
     RECT  20.88 6.845 40.806 7.159 ;
     RECT  41.58 6.143 54.45 7.159 ;
     RECT  20.88 7.159 54.45 7.961 ;
     RECT  20.988 7.961 54.45 8.339 ;
     RECT  20.988 8.339 54.09 8.429 ;
     RECT  20.988 8.429 53.982 8.851 ;
     RECT  20.772 8.851 53.982 9.653 ;
     RECT  21.348 9.653 53.982 10.589 ;
     RECT  21.744 10.589 53.982 10.661 ;
     RECT  21.744 10.661 39.042 10.769 ;
     RECT  22.248 10.769 39.042 10.859 ;
     RECT  39.852 10.661 53.982 10.967 ;
     RECT  22.248 10.859 38.934 11.515 ;
     RECT  21.744 11.515 38.934 11.785 ;
     RECT  21.744 11.785 39.006 12.019 ;
     RECT  21.708 12.019 39.006 12.091 ;
     RECT  21.636 12.091 39.006 12.181 ;
     RECT  21.42 12.181 39.006 12.595 ;
     RECT  39.96 10.967 53.982 12.631 ;
     RECT  39.78 12.631 53.982 12.721 ;
     RECT  21.276 12.595 39.006 12.749 ;
     RECT  39.744 12.721 53.982 13.019 ;
     RECT  39.744 13.019 40.497 13.837 ;
     RECT  41.256 13.019 53.658 13.837 ;
     RECT  39.744 13.837 53.658 13.901 ;
     RECT  21.672 12.749 38.934 14.251 ;
     RECT  39.744 13.901 53.622 14.251 ;
     RECT  21.276 14.251 53.622 14.521 ;
     RECT  21.24 14.521 53.622 14.675 ;
     RECT  21.456 14.675 53.622 14.945 ;
     RECT  21.636 14.945 53.622 14.957 ;
     RECT  22.212 14.957 53.622 15.179 ;
     RECT  22.212 15.179 53.586 15.323 ;
     RECT  23.724 15.323 53.586 15.341 ;
     RECT  22.212 15.323 22.986 15.359 ;
     RECT  22.716 15.359 22.842 15.485 ;
     RECT  22.716 15.485 22.734 15.629 ;
     RECT  23.868 15.341 53.586 15.719 ;
     RECT  54.036 15.961 54.198 16.013 ;
     RECT  23.868 15.719 53.19 16.259 ;
     RECT  54.036 16.013 54.054 16.529 ;
     RECT  23.868 16.259 53.154 17.339 ;
     RECT  23.94 17.339 53.154 17.483 ;
     RECT  23.94 17.483 41.742 17.519 ;
     RECT  23.94 17.519 24.297 17.879 ;
     RECT  42.516 17.483 53.154 18.229 ;
     RECT  25.092 17.519 41.742 18.301 ;
     RECT  42.48 18.229 53.154 18.301 ;
     RECT  54.396 18.235 54.414 18.419 ;
     RECT  24.015 17.879 24.297 18.931 ;
     RECT  25.092 18.301 53.154 18.931 ;
     RECT  54.18 18.535 54.198 18.959 ;
     RECT  24.015 18.931 53.154 19.075 ;
     RECT  24.015 19.075 53.838 19.229 ;
     RECT  24.015 19.229 53.154 19.499 ;
     RECT  25.2 19.499 52.83 19.535 ;
     RECT  24.015 19.499 24.462 19.643 ;
     RECT  46.692 19.535 52.83 20.309 ;
     RECT  25.2 19.535 45.897 20.389 ;
     RECT  46.692 20.309 52.362 20.389 ;
     RECT  25.2 20.389 52.362 20.579 ;
     RECT  25.2 20.579 45.897 21.197 ;
     RECT  25.2 21.197 42.57 21.389 ;
     RECT  43.344 21.197 45.897 21.389 ;
     RECT  25.272 21.389 42.57 21.461 ;
     RECT  25.272 21.461 41.31 21.659 ;
     RECT  46.728 20.579 52.362 21.659 ;
     RECT  25.272 21.659 40.914 21.695 ;
     RECT  46.728 21.659 46.818 21.695 ;
     RECT  25.524 21.695 40.914 21.929 ;
     RECT  42.048 21.461 42.57 21.929 ;
     RECT  46.728 21.695 46.746 21.929 ;
     RECT  43.416 21.389 45.897 22.001 ;
     RECT  45.615 22.001 45.897 22.045 ;
     RECT  43.416 22.001 44.658 22.157 ;
     RECT  44.316 22.157 44.658 22.199 ;
     RECT  44.316 22.199 44.55 22.235 ;
     RECT  45.615 22.045 46.062 22.469 ;
     RECT  32.22 21.929 40.914 22.477 ;
     RECT  42.048 21.929 42.318 22.477 ;
     RECT  45.615 22.469 45.954 22.739 ;
     RECT  25.524 21.929 31.41 22.855 ;
     RECT  32.22 22.477 42.318 22.855 ;
     RECT  45.615 22.739 45.897 22.891 ;
     RECT  25.524 22.855 42.318 23.009 ;
     RECT  25.524 23.009 37.602 23.045 ;
     RECT  44.316 22.235 44.334 23.045 ;
     RECT  43.416 22.157 43.434 23.161 ;
     RECT  32.472 23.045 37.602 23.165 ;
     RECT  47.664 21.659 52.362 23.279 ;
     RECT  38.34 23.009 42.318 23.359 ;
     RECT  43.2 23.161 43.434 23.359 ;
     RECT  38.34 23.359 43.434 23.371 ;
     RECT  38.34 23.371 43.578 23.395 ;
     RECT  44.388 23.359 44.514 23.549 ;
     RECT  47.664 23.279 52.218 23.549 ;
     RECT  44.496 23.549 44.514 23.563 ;
     RECT  45.36 22.891 45.897 23.563 ;
     RECT  44.496 23.563 45.897 23.621 ;
     RECT  25.524 23.045 31.734 23.791 ;
     RECT  32.472 23.165 37.566 23.791 ;
     RECT  25.524 23.791 37.566 23.819 ;
     RECT  45.108 23.621 45.897 23.819 ;
     RECT  25.524 23.819 37.422 23.927 ;
     RECT  38.34 23.395 43.614 23.947 ;
     RECT  37.404 23.927 37.422 23.981 ;
     RECT  25.524 23.927 36.522 24.089 ;
     RECT  38.16 23.947 43.614 24.089 ;
     RECT  38.16 24.089 43.29 24.125 ;
     RECT  38.736 24.125 38.754 24.197 ;
     RECT  39.672 24.125 43.29 24.359 ;
     RECT  42.804 24.359 42.966 24.467 ;
     RECT  39.672 24.359 42.066 24.503 ;
     RECT  42.804 24.467 42.822 24.503 ;
     RECT  40.14 24.503 40.497 24.509 ;
     RECT  41.76 24.503 42.066 24.526 ;
     RECT  25.524 24.089 36.126 24.539 ;
     RECT  41.76 24.526 41.994 24.629 ;
     RECT  41.76 24.629 41.922 24.665 ;
     RECT  41.868 24.665 41.922 24.701 ;
     RECT  41.904 24.701 41.922 24.773 ;
     RECT  25.704 24.539 36.126 24.809 ;
     RECT  33.588 24.809 36.126 24.899 ;
     RECT  47.664 23.549 51.462 24.935 ;
     RECT  25.704 24.809 32.49 25.277 ;
     RECT  47.88 24.935 51.462 25.285 ;
     RECT  52.2 23.549 52.218 25.285 ;
     RECT  32.364 25.277 32.49 25.349 ;
     RECT  47.88 25.285 52.218 25.439 ;
     RECT  25.704 25.277 31.266 25.555 ;
     RECT  25.56 25.555 31.266 25.565 ;
     RECT  25.56 25.565 31.086 25.583 ;
     RECT  25.56 25.583 29.754 25.709 ;
     RECT  32.4 25.349 32.49 25.861 ;
     RECT  33.732 24.899 36.126 25.861 ;
     RECT  32.4 25.861 36.126 25.889 ;
     RECT  48.204 25.439 51.822 25.979 ;
     RECT  33.192 25.889 36.126 26.015 ;
     RECT  47.34 25.963 47.358 26.015 ;
     RECT  33.912 26.015 36.126 26.051 ;
     RECT  48.744 25.979 51.822 26.123 ;
     RECT  48.816 26.123 49.41 26.237 ;
     RECT  50.148 26.123 51.822 26.237 ;
     RECT  50.292 26.237 51.822 26.249 ;
     RECT  49.392 26.237 49.41 26.285 ;
     RECT  35.82 26.051 36.126 26.393 ;
     RECT  50.292 26.249 51.297 26.393 ;
     RECT  31.068 25.583 31.086 26.401 ;
     RECT  25.56 25.709 29.697 26.429 ;
     RECT  30.6 26.401 31.086 26.491 ;
     RECT  25.956 26.429 29.697 26.519 ;
     RECT  35.82 26.393 35.838 26.591 ;
     RECT  26.208 26.519 29.697 26.599 ;
     RECT  30.564 26.491 31.086 26.599 ;
     RECT  31.896 26.131 31.914 26.663 ;
     RECT  26.208 26.599 31.086 26.789 ;
     RECT  33.912 26.051 35.097 26.789 ;
     RECT  26.64 26.789 31.086 27.059 ;
     RECT  26.748 27.059 31.086 27.211 ;
     RECT  26.748 27.211 31.194 27.707 ;
     RECT  26.748 27.707 30.006 27.725 ;
     RECT  30.744 27.707 31.194 27.743 ;
     RECT  31.068 27.743 31.194 27.751 ;
     RECT  31.068 27.751 31.23 27.869 ;
     RECT  31.212 27.869 31.23 27.905 ;
     RECT  26.748 27.725 29.898 27.917 ;
     RECT  27.36 27.917 29.898 28.139 ;
     RECT  29.088 28.139 29.898 28.211 ;
     RECT  27.36 28.139 28.314 28.247 ;
     RECT  27.36 28.247 28.206 28.283 ;
     RECT  27.504 28.283 27.522 28.409 ;
     RECT  29.088 28.211 29.697 28.409 ;
     RECT  2.415 2.413 2.697 321.587 ;
     RECT  7.815 2.413 8.097 321.587 ;
     RECT  13.215 2.413 13.497 321.587 ;
     RECT  18.615 2.413 18.897 321.587 ;
     RECT  24.015 19.643 24.297 321.587 ;
     RECT  29.415 28.409 29.697 321.587 ;
     RECT  34.815 26.789 35.097 321.587 ;
     RECT  40.215 24.509 40.497 321.587 ;
     RECT  45.615 23.819 45.897 321.587 ;
     RECT  51.015 26.393 51.297 321.587 ;
     RECT  56.415 5.063 56.697 321.587 ;
     RECT  61.815 4.721 62.097 321.587 ;
     RECT  67.215 4.157 67.497 321.587 ;
     RECT  72.615 2.633 72.897 321.587 ;
     RECT  78.015 2.413 78.297 321.587 ;
     RECT  83.415 2.413 83.697 321.587 ;
     RECT  2.415 321.587 2.505 321.857 ;
     RECT  7.815 321.587 7.905 321.857 ;
     RECT  13.215 321.587 13.305 321.857 ;
     RECT  18.615 321.587 18.705 321.857 ;
     RECT  24.015 321.587 24.105 321.857 ;
     RECT  29.415 321.587 29.505 321.857 ;
     RECT  34.815 321.587 34.905 321.857 ;
     RECT  40.215 321.587 40.305 321.857 ;
     RECT  45.615 321.587 45.705 321.857 ;
     RECT  51.015 321.587 51.105 321.857 ;
     RECT  56.415 321.587 56.505 321.857 ;
     RECT  61.815 321.587 61.905 321.857 ;
     RECT  67.215 321.587 67.305 321.857 ;
     RECT  72.615 321.587 72.705 321.857 ;
     RECT  78.015 321.587 78.105 321.857 ;
     RECT  83.415 321.587 83.505 321.857 ;
    LAYER M4 ;
     RECT  2.408 2.148 2.512 321.852 ;
     RECT  2.512 2.418 2.704 321.582 ;
     RECT  7.808 2.148 7.912 321.852 ;
     RECT  7.912 2.418 8.104 321.582 ;
     RECT  13.208 2.148 13.312 321.852 ;
     RECT  13.312 2.418 13.504 321.582 ;
     RECT  18.608 2.148 18.712 321.852 ;
     RECT  18.712 2.418 18.904 321.582 ;
     RECT  20.005 0.576 20.101 0.6 ;
     RECT  19.897 1.728 20.149 1.752 ;
     RECT  20.101 0.576 20.153 0.648 ;
     RECT  20.153 0.624 20.333 0.648 ;
     RECT  20.149 1.728 20.581 2.328 ;
     RECT  20.005 3.552 20.581 3.576 ;
     RECT  20.581 1.728 20.977 3.576 ;
     RECT  20.977 1.632 21.121 3.576 ;
     RECT  21.121 1.248 21.404 3.576 ;
     RECT  21.349 0.24 21.445 0.264 ;
     RECT  21.404 1.248 21.445 4.104 ;
     RECT  21.445 0.24 21.491 4.104 ;
     RECT  21.491 0.24 21.509 3.72 ;
     RECT  21.265 14.256 21.625 14.28 ;
     RECT  21.625 14.256 21.773 14.952 ;
     RECT  21.509 0.096 22.021 3.72 ;
     RECT  20.761 5.712 22.165 5.736 ;
     RECT  22.021 0.048 22.169 3.72 ;
     RECT  21.409 7.968 22.565 7.992 ;
     RECT  22.165 4.752 22.669 5.736 ;
     RECT  21.773 14.928 22.781 14.952 ;
     RECT  22.777 12 22.925 12.024 ;
     RECT  22.669 4.752 23.173 5.784 ;
     RECT  22.169 0.096 23.353 3.72 ;
     RECT  23.173 4.704 23.353 6.024 ;
     RECT  23.137 13.056 23.42 13.08 ;
     RECT  23.353 0.096 23.713 6.024 ;
     RECT  22.957 15.312 23.749 15.336 ;
     RECT  23.713 0.096 24.008 6.312 ;
     RECT  22.525 9.648 24.008 9.672 ;
     RECT  23.461 11.136 24.008 11.16 ;
     RECT  23.42 13.056 24.008 13.272 ;
     RECT  23.749 14.688 24.008 15.336 ;
     RECT  24.008 0.096 24.112 321.852 ;
     RECT  24.112 0.096 24.304 321.582 ;
     RECT  24.304 14.688 24.419 15 ;
     RECT  24.304 0.096 24.613 6.84 ;
     RECT  24.304 12.624 24.689 13.08 ;
     RECT  24.613 0.048 24.697 6.84 ;
     RECT  24.304 7.872 25.091 11.448 ;
     RECT  24.304 16.416 25.139 17.112 ;
     RECT  24.304 18.96 25.139 20.088 ;
     RECT  25.139 18.96 25.18 18.984 ;
     RECT  25.139 16.416 25.229 16.44 ;
     RECT  25.091 10.368 25.265 11.448 ;
     RECT  24.419 14.928 25.441 15 ;
     RECT  24.689 12.624 25.621 12.792 ;
     RECT  25.265 10.368 25.625 11.256 ;
     RECT  25.621 12.528 25.657 12.792 ;
     RECT  25.441 14.832 25.661 15 ;
     RECT  25.139 20.064 25.667 20.088 ;
     RECT  25.091 7.872 25.769 7.896 ;
     RECT  25.661 14.928 25.841 15 ;
     RECT  24.697 0.048 25.945 6.792 ;
     RECT  25.945 0.048 26.005 6.888 ;
     RECT  25.621 22.224 26.161 22.776 ;
     RECT  26.161 22.176 26.413 22.776 ;
     RECT  26.005 0.048 26.453 7.704 ;
     RECT  25.091 8.88 26.557 8.904 ;
     RECT  25.765 18.432 26.629 18.456 ;
     RECT  26.629 18.144 26.701 18.456 ;
     RECT  26.413 22.176 26.701 23.352 ;
     RECT  26.701 22.176 26.737 23.88 ;
     RECT  26.557 8.88 26.773 9.048 ;
     RECT  26.737 21.984 26.801 23.88 ;
     RECT  25.841 14.976 26.821 15 ;
     RECT  26.801 21.984 26.849 23.928 ;
     RECT  26.821 14.256 26.989 15 ;
     RECT  26.269 15.984 26.989 16.008 ;
     RECT  26.453 0.096 27.061 7.704 ;
     RECT  26.773 8.88 27.061 9.144 ;
     RECT  25.625 10.896 27.061 11.256 ;
     RECT  25.657 12.528 27.061 12.84 ;
     RECT  27.061 10.896 27.137 12.84 ;
     RECT  27.061 0.096 27.209 9.144 ;
     RECT  27.209 0.096 27.281 7.992 ;
     RECT  27.209 9.12 27.301 9.144 ;
     RECT  27.137 10.896 27.301 12.552 ;
     RECT  27.301 9.12 27.353 12.552 ;
     RECT  26.701 18.144 27.353 19.416 ;
     RECT  26.849 21.984 27.385 22.824 ;
     RECT  27.353 9.12 27.425 12.456 ;
     RECT  26.989 14.256 27.569 16.008 ;
     RECT  26.953 20.496 27.637 20.52 ;
     RECT  27.385 21.696 27.637 22.824 ;
     RECT  26.849 23.856 27.673 23.928 ;
     RECT  27.281 0.096 27.749 7.08 ;
     RECT  27.025 17.04 27.781 17.064 ;
     RECT  27.353 18.144 27.781 18.744 ;
     RECT  27.637 20.496 27.923 22.824 ;
     RECT  27.673 23.856 27.971 24.168 ;
     RECT  27.923 22.752 28.001 22.824 ;
     RECT  27.425 9.552 28.037 12.456 ;
     RECT  27.569 14.4 28.037 16.008 ;
     RECT  28.037 15.936 28.069 16.008 ;
     RECT  27.781 17.04 28.069 18.744 ;
     RECT  28.069 15.936 28.145 18.744 ;
     RECT  26.665 25.152 28.181 25.176 ;
     RECT  28.145 16.224 28.217 18.744 ;
     RECT  27.749 0.144 28.261 7.08 ;
     RECT  26.737 27.888 28.285 27.912 ;
     RECT  27.923 20.496 28.361 21.72 ;
     RECT  28.037 9.552 28.433 9.72 ;
     RECT  28.285 27.888 28.609 28.008 ;
     RECT  28.037 10.704 28.645 12.456 ;
     RECT  28.001 22.8 28.693 22.824 ;
     RECT  27.971 23.856 28.693 23.88 ;
     RECT  28.261 0.144 28.844 7.992 ;
     RECT  28.844 0.144 29.005 9.384 ;
     RECT  28.645 10.704 29.036 12.792 ;
     RECT  28.361 20.784 29.041 21.72 ;
     RECT  28.693 22.8 29.041 23.88 ;
     RECT  28.609 27.696 29.185 28.008 ;
     RECT  29.005 0.096 29.408 9.384 ;
     RECT  29.036 10.704 29.408 13.368 ;
     RECT  28.037 14.4 29.408 14.76 ;
     RECT  28.217 16.224 29.408 18.456 ;
     RECT  28.609 19.536 29.408 19.656 ;
     RECT  29.041 20.784 29.408 23.88 ;
     RECT  29.401 25.44 29.408 25.464 ;
     RECT  29.185 27.648 29.408 28.008 ;
     RECT  29.408 0.096 29.512 321.852 ;
     RECT  29.512 0.096 29.704 321.582 ;
     RECT  29.704 14.736 29.909 25.56 ;
     RECT  29.909 14.736 29.939 21.72 ;
     RECT  29.704 27.648 30.017 27.72 ;
     RECT  29.939 14.736 30.053 17.928 ;
     RECT  30.053 14.928 30.124 17.928 ;
     RECT  29.704 10.8 30.341 13.08 ;
     RECT  30.017 27.648 30.341 27.672 ;
     RECT  29.704 9.264 30.385 9.72 ;
     RECT  30.341 10.848 30.485 13.08 ;
     RECT  30.124 16.368 30.629 17.928 ;
     RECT  29.704 0.096 30.733 7.992 ;
     RECT  30.385 9.264 30.733 9.528 ;
     RECT  29.909 23.04 30.773 25.56 ;
     RECT  29.939 19.344 30.845 19.464 ;
     RECT  30.629 17.904 30.901 17.928 ;
     RECT  30.629 16.368 30.917 16.44 ;
     RECT  30.773 24.528 30.953 25.56 ;
     RECT  30.733 0.096 31.093 9.528 ;
     RECT  30.124 14.928 31.201 14.952 ;
     RECT  29.939 20.496 31.237 21.72 ;
     RECT  30.773 23.04 31.237 23.064 ;
     RECT  30.953 24.912 31.277 25.56 ;
     RECT  30.485 10.848 31.453 10.872 ;
     RECT  31.201 14.928 31.453 15.24 ;
     RECT  31.453 10.8 31.477 10.872 ;
     RECT  31.477 10.8 31.537 10.92 ;
     RECT  31.237 20.496 31.565 23.064 ;
     RECT  31.093 0.048 31.813 9.528 ;
     RECT  30.901 17.904 31.817 18.264 ;
     RECT  31.813 0.048 31.849 9.72 ;
     RECT  31.453 14.88 31.921 15.24 ;
     RECT  31.849 0.048 31.933 9.816 ;
     RECT  30.845 19.344 31.957 19.368 ;
     RECT  31.565 20.496 31.957 22.104 ;
     RECT  31.933 0.048 31.961 9.144 ;
     RECT  30.485 12.192 31.961 13.08 ;
     RECT  31.961 12.48 31.997 13.08 ;
     RECT  31.997 12.768 32.029 13.08 ;
     RECT  31.921 14.208 32.029 15.24 ;
     RECT  31.957 19.344 32.033 22.104 ;
     RECT  32.029 12.768 32.149 15.24 ;
     RECT  30.917 16.368 32.149 16.392 ;
     RECT  32.149 12.768 32.209 16.392 ;
     RECT  31.537 10.848 32.245 10.92 ;
     RECT  32.033 20.16 32.249 22.104 ;
     RECT  31.961 0.048 32.285 7.896 ;
     RECT  31.277 24.912 32.393 24.936 ;
     RECT  32.425 25.68 32.509 25.704 ;
     RECT  32.285 7.776 32.609 7.896 ;
     RECT  32.245 10.848 32.645 11.496 ;
     RECT  32.389 23.904 32.749 23.928 ;
     RECT  32.677 10.8 32.861 10.824 ;
     RECT  32.749 23.328 33.005 23.928 ;
     RECT  32.209 12.768 33.059 16.584 ;
     RECT  31.961 9.12 33.217 9.144 ;
     RECT  32.285 0.048 33.253 6.792 ;
     RECT  32.609 7.872 33.253 7.896 ;
     RECT  33.253 7.872 33.301 8.136 ;
     RECT  33.217 9.12 33.301 9.864 ;
     RECT  33.059 12.768 33.301 13.08 ;
     RECT  33.059 14.112 33.329 16.584 ;
     RECT  32.209 17.616 33.329 17.64 ;
     RECT  33.329 14.112 33.401 15.528 ;
     RECT  32.249 20.16 33.401 21.528 ;
     RECT  33.301 7.872 33.484 9.864 ;
     RECT  33.253 0.048 33.617 6.84 ;
     RECT  33.401 20.16 33.617 20.184 ;
     RECT  33.005 23.376 33.721 23.928 ;
     RECT  33.901 19.872 33.973 19.896 ;
     RECT  33.329 16.56 34.045 16.584 ;
     RECT  33.973 19.776 34.045 19.896 ;
     RECT  34.045 19.392 34.165 19.896 ;
     RECT  33.401 21.36 34.189 21.528 ;
     RECT  33.301 11.952 34.501 13.08 ;
     RECT  34.501 11.904 34.513 13.08 ;
     RECT  33.401 14.784 34.549 15.528 ;
     RECT  34.045 16.56 34.549 17.016 ;
     RECT  34.189 21.36 34.765 22.248 ;
     RECT  33.617 0.048 34.808 5.784 ;
     RECT  33.617 6.816 34.808 6.84 ;
     RECT  33.484 7.872 34.808 8.616 ;
     RECT  33.484 9.696 34.808 9.864 ;
     RECT  34.513 11.76 34.808 13.08 ;
     RECT  34.549 14.784 34.808 17.016 ;
     RECT  34.165 18.768 34.808 19.896 ;
     RECT  34.765 21.36 34.808 22.344 ;
     RECT  33.721 23.376 34.808 25.224 ;
     RECT  34.808 0.048 34.912 321.852 ;
     RECT  34.912 0.048 35.104 321.582 ;
     RECT  35.104 0.048 35.26 9 ;
     RECT  35.104 23.376 35.267 25.176 ;
     RECT  35.267 25.152 35.308 25.176 ;
     RECT  35.104 21.504 35.381 21.528 ;
     RECT  35.26 7.968 35.525 9 ;
     RECT  35.104 14.88 35.597 16.632 ;
     RECT  35.26 0.048 35.813 6.936 ;
     RECT  35.267 23.376 35.993 23.688 ;
     RECT  35.104 19.776 36.029 19.8 ;
     RECT  35.597 15.408 36.065 16.632 ;
     RECT  35.525 8.16 36.277 9 ;
     RECT  35.104 11.952 36.373 13.176 ;
     RECT  36.373 11.952 36.419 13.848 ;
     RECT  36.065 15.408 36.433 15.432 ;
     RECT  36.277 8.16 36.467 9.72 ;
     RECT  35.104 10.848 36.517 10.872 ;
     RECT  36.419 11.952 36.517 12.552 ;
     RECT  36.419 13.536 36.517 13.848 ;
     RECT  36.467 8.16 36.533 9 ;
     RECT  36.517 13.536 36.563 14.232 ;
     RECT  36.533 8.976 36.569 9 ;
     RECT  36.517 10.848 36.677 12.552 ;
     RECT  36.065 16.608 36.709 16.632 ;
     RECT  36.673 23.136 36.709 23.16 ;
     RECT  35.104 18.528 36.745 18.552 ;
     RECT  36.709 16.608 36.821 16.92 ;
     RECT  36.745 18.144 36.925 18.552 ;
     RECT  36.925 18.144 37.001 19.32 ;
     RECT  37.001 18.528 37.033 19.32 ;
     RECT  36.677 10.848 37.105 10.872 ;
     RECT  37.033 18.528 37.105 19.848 ;
     RECT  36.677 11.952 37.361 12.552 ;
     RECT  36.709 22.896 37.393 23.16 ;
     RECT  35.813 0.048 37.573 6.312 ;
     RECT  37.105 10.416 37.577 10.872 ;
     RECT  37.393 22.896 37.613 23.976 ;
     RECT  37.573 0.048 37.649 7.032 ;
     RECT  37.105 18.528 37.789 19.896 ;
     RECT  37.537 15.648 37.825 15.816 ;
     RECT  36.821 16.896 37.861 16.92 ;
     RECT  37.613 22.896 37.865 22.92 ;
     RECT  37.361 11.952 37.925 12.216 ;
     RECT  37.925 11.376 38.009 12.216 ;
     RECT  37.825 15.456 38.041 15.816 ;
     RECT  37.613 23.952 38.149 23.976 ;
     RECT  38.149 23.952 38.189 24.12 ;
     RECT  38.041 15.456 38.197 15.864 ;
     RECT  37.861 16.896 38.197 17.16 ;
     RECT  38.197 15.456 38.284 17.496 ;
     RECT  38.284 15.456 38.297 15.816 ;
     RECT  36.997 21.744 38.405 21.768 ;
     RECT  37.789 18.528 38.441 19.992 ;
     RECT  37.573 8.4 38.473 8.424 ;
     RECT  36.563 13.824 38.545 14.232 ;
     RECT  38.441 19.44 38.621 19.992 ;
     RECT  38.284 17.472 38.689 17.496 ;
     RECT  38.689 17.472 38.729 18.456 ;
     RECT  38.297 15.648 38.801 15.816 ;
     RECT  38.621 19.872 38.801 19.992 ;
     RECT  38.545 13.824 38.837 14.52 ;
     RECT  37.649 0.144 38.945 7.032 ;
     RECT  38.761 22.752 38.945 22.776 ;
     RECT  38.009 12.192 39.017 12.216 ;
     RECT  38.801 19.92 39.053 19.992 ;
     RECT  39.085 22.8 39.233 22.824 ;
     RECT  38.945 0.144 39.365 6.024 ;
     RECT  38.837 13.92 39.409 14.52 ;
     RECT  38.801 15.648 39.409 15.672 ;
     RECT  38.729 18.288 40.093 18.456 ;
     RECT  38.189 24.096 40.129 24.12 ;
     RECT  39.365 0.096 40.208 6.024 ;
     RECT  38.945 7.008 40.208 7.032 ;
     RECT  38.473 8.256 40.208 8.424 ;
     RECT  39.337 10.272 40.208 10.296 ;
     RECT  39.409 13.92 40.208 15.672 ;
     RECT  40.093 18.288 40.208 18.792 ;
     RECT  39.053 19.968 40.208 19.992 ;
     RECT  40.129 24.096 40.208 24.504 ;
     RECT  40.208 0.096 40.312 321.852 ;
     RECT  40.312 0.096 40.504 321.582 ;
     RECT  40.504 18.432 40.673 18.792 ;
     RECT  40.504 22.56 40.787 22.584 ;
     RECT  40.504 0.096 41.245 6.024 ;
     RECT  40.673 18.432 41.605 18.456 ;
     RECT  41.245 0.048 41.609 6.024 ;
     RECT  40.504 19.92 41.681 21.192 ;
     RECT  41.609 0.096 41.708 6.024 ;
     RECT  40.504 13.92 41.713 13.944 ;
     RECT  40.504 14.976 41.713 15 ;
     RECT  41.713 13.92 41.753 15 ;
     RECT  41.708 0.096 41.795 6.264 ;
     RECT  41.753 13.92 41.845 14.664 ;
     RECT  40.504 10.8 41.891 10.824 ;
     RECT  41.605 18.336 41.929 18.456 ;
     RECT  40.504 23.616 41.929 24.504 ;
     RECT  41.929 23.424 42.041 24.504 ;
     RECT  42.041 24.48 42.077 24.504 ;
     RECT  42.044 15.888 42.109 15.912 ;
     RECT  42.109 15.888 42.131 16.44 ;
     RECT  40.504 9.648 42.185 9.672 ;
     RECT  41.605 8.544 42.293 8.568 ;
     RECT  41.681 21.168 42.653 21.192 ;
     RECT  40.504 12.336 42.685 12.36 ;
     RECT  41.681 19.92 42.725 19.944 ;
     RECT  42.131 16.32 42.833 16.44 ;
     RECT  41.929 18.336 42.973 18.792 ;
     RECT  42.685 11.952 43.009 12.36 ;
     RECT  41.845 13.728 43.225 14.664 ;
     RECT  43.009 11.952 43.292 12.744 ;
     RECT  41.795 0.096 43.333 6.024 ;
     RECT  43.292 11.136 43.333 12.744 ;
     RECT  43.333 10.752 43.379 12.744 ;
     RECT  42.973 9.072 43.513 9.144 ;
     RECT  42.973 18.336 43.513 19.08 ;
     RECT  42.041 23.424 43.549 23.448 ;
     RECT  43.549 23.376 43.585 23.448 ;
     RECT  43.225 13.728 43.625 14.856 ;
     RECT  43.585 23.376 43.633 23.592 ;
     RECT  43.333 0.096 43.765 6.648 ;
     RECT  43.379 12 43.877 12.744 ;
     RECT  43.513 9.072 43.907 9.384 ;
     RECT  43.513 18.048 43.907 19.08 ;
     RECT  43.625 14.832 43.909 14.856 ;
     RECT  42.833 16.32 43.909 16.344 ;
     RECT  43.625 13.728 43.949 13.848 ;
     RECT  43.765 21.648 44.012 21.672 ;
     RECT  43.907 9.072 44.017 9.144 ;
     RECT  43.957 20.304 44.044 20.328 ;
     RECT  43.379 10.752 44.081 10.776 ;
     RECT  44.012 21.648 44.093 22.152 ;
     RECT  44.093 22.128 44.099 22.152 ;
     RECT  44.081 10.272 44.165 10.776 ;
     RECT  43.909 14.832 44.237 17.112 ;
     RECT  43.877 12 44.377 12.024 ;
     RECT  44.017 8.928 44.413 9.144 ;
     RECT  43.765 0.096 44.453 6.744 ;
     RECT  44.237 15.456 44.489 17.112 ;
     RECT  43.907 18.48 44.633 19.08 ;
     RECT  44.453 0.144 44.701 6.744 ;
     RECT  44.633 18.48 44.876 19.032 ;
     RECT  44.413 8.544 45.061 9.144 ;
     RECT  44.701 0.144 45.109 7.128 ;
     RECT  45.061 8.544 45.109 9.384 ;
     RECT  43.949 13.824 45.205 13.848 ;
     RECT  45.205 13.392 45.253 13.848 ;
     RECT  45.109 0.144 45.301 9.384 ;
     RECT  44.165 10.752 45.301 10.776 ;
     RECT  45.253 13.008 45.349 13.848 ;
     RECT  45.301 0.144 45.421 10.776 ;
     RECT  44.377 11.76 45.421 12.024 ;
     RECT  45.421 0.048 45.569 12.024 ;
     RECT  45.569 0.144 45.608 12.024 ;
     RECT  45.349 13.008 45.608 14.424 ;
     RECT  44.489 15.456 45.608 16.344 ;
     RECT  44.876 17.808 45.608 19.032 ;
     RECT  43.633 23.568 45.608 23.592 ;
     RECT  45.608 0.144 45.712 321.852 ;
     RECT  45.712 0.144 45.904 321.582 ;
     RECT  45.904 9.072 46.001 9.816 ;
     RECT  45.904 0.144 46.019 7.992 ;
     RECT  45.904 18.192 46.019 19.416 ;
     RECT  46.019 0.192 46.115 7.992 ;
     RECT  46.115 0.48 46.307 7.992 ;
     RECT  46.307 1.728 46.595 7.992 ;
     RECT  46.595 1.728 46.691 7.32 ;
     RECT  46.019 18.48 46.721 19.416 ;
     RECT  45.904 11.232 46.829 17.112 ;
     RECT  46.001 9.072 46.897 9.72 ;
     RECT  46.829 13.296 47.005 17.112 ;
     RECT  46.721 18.48 47.005 18.984 ;
     RECT  46.307 0.48 47.081 0.696 ;
     RECT  47.005 13.296 47.153 18.984 ;
     RECT  47.081 0.48 47.369 0.552 ;
     RECT  47.153 13.824 47.585 18.984 ;
     RECT  45.904 23.568 47.651 23.592 ;
     RECT  46.829 11.232 47.905 11.976 ;
     RECT  46.897 8.544 47.945 9.72 ;
     RECT  47.948 22.176 47.977 22.2 ;
     RECT  47.977 22.176 48.035 22.872 ;
     RECT  47.905 11.232 48.085 12.024 ;
     RECT  47.585 13.824 48.14 15.24 ;
     RECT  48.14 13.776 48.161 15.24 ;
     RECT  45.904 20.832 48.161 20.856 ;
     RECT  48.161 13.776 48.181 14.664 ;
     RECT  48.085 11.136 48.229 12.024 ;
     RECT  47.369 0.528 48.301 0.552 ;
     RECT  46.691 1.728 48.301 6.888 ;
     RECT  48.301 0.528 48.325 6.888 ;
     RECT  47.945 8.544 48.325 9.096 ;
     RECT  48.229 10.848 48.325 12.024 ;
     RECT  48.325 0.528 48.373 7.032 ;
     RECT  48.325 8.4 48.373 9.096 ;
     RECT  48.373 0.528 48.467 9.096 ;
     RECT  47.605 24.864 48.625 24.888 ;
     RECT  47.329 25.968 48.773 25.992 ;
     RECT  48.467 7.872 48.809 9.096 ;
     RECT  48.181 13.056 48.809 14.664 ;
     RECT  47.585 16.8 48.845 18.984 ;
     RECT  48.467 0.528 48.877 6.888 ;
     RECT  48.325 10.272 48.901 12.024 ;
     RECT  48.877 0.048 48.917 6.888 ;
     RECT  48.809 9.072 48.949 9.096 ;
     RECT  48.917 0.048 49.025 5.736 ;
     RECT  48.809 13.824 49.043 14.664 ;
     RECT  48.949 9.072 49.061 9.144 ;
     RECT  48.901 10.272 49.169 12.072 ;
     RECT  48.625 23.952 49.169 24.888 ;
     RECT  49.169 10.848 49.241 12.072 ;
     RECT  49.169 23.952 49.349 24.552 ;
     RECT  48.035 22.848 49.381 22.872 ;
     RECT  49.349 23.952 49.381 23.976 ;
     RECT  49.043 13.968 49.417 14.664 ;
     RECT  49.273 9.408 49.427 9.72 ;
     RECT  48.845 17.616 49.436 18.984 ;
     RECT  49.381 22.848 49.465 23.976 ;
     RECT  49.427 9.408 49.475 9.432 ;
     RECT  49.436 17.616 49.477 19.704 ;
     RECT  48.809 7.872 49.501 7.992 ;
     RECT  49.477 17.616 49.523 20.568 ;
     RECT  49.465 22.848 49.529 22.872 ;
     RECT  49.501 7.968 49.565 7.992 ;
     RECT  49.025 0.528 49.619 5.736 ;
     RECT  49.523 20.544 49.637 20.568 ;
     RECT  49.523 17.616 49.673 18.936 ;
     RECT  49.241 10.848 49.825 11.784 ;
     RECT  48.805 26.208 50.137 26.232 ;
     RECT  48.917 6.864 50.281 6.888 ;
     RECT  49.417 13.968 50.453 14.856 ;
     RECT  49.825 11.76 50.569 11.784 ;
     RECT  50.453 13.104 50.569 14.856 ;
     RECT  50.281 6.768 50.629 6.888 ;
     RECT  49.453 16.272 50.641 16.392 ;
     RECT  49.619 1.152 50.677 5.736 ;
     RECT  49.673 18.48 50.725 18.936 ;
     RECT  50.725 18.24 50.749 18.936 ;
     RECT  50.677 0.528 50.773 5.736 ;
     RECT  50.629 6.768 50.785 6.936 ;
     RECT  50.149 8.544 50.785 8.76 ;
     RECT  50.773 0.48 50.869 5.736 ;
     RECT  50.785 6.768 50.869 8.76 ;
     RECT  50.869 0.192 50.917 8.76 ;
     RECT  50.917 0.096 51.008 8.76 ;
     RECT  51.001 10.32 51.008 10.344 ;
     RECT  50.569 11.76 51.008 14.856 ;
     RECT  50.641 15.984 51.008 16.392 ;
     RECT  50.749 18.24 51.008 19.656 ;
     RECT  50.341 21.12 51.008 21.144 ;
     RECT  49.465 23.952 51.008 23.976 ;
     RECT  50.137 25.68 51.008 26.232 ;
     RECT  51.008 0.096 51.11 321.852 ;
     RECT  51.11 0.144 51.112 321.852 ;
     RECT  51.112 0.144 51.304 321.582 ;
     RECT  51.304 8.544 51.443 8.76 ;
     RECT  51.304 18.24 51.581 18.264 ;
     RECT  51.304 19.632 51.905 19.656 ;
     RECT  51.304 10.224 51.971 10.344 ;
     RECT  51.304 16.368 52.013 16.392 ;
     RECT  51.304 0.144 52.297 5.592 ;
     RECT  51.971 10.224 52.337 10.248 ;
     RECT  51.304 7.392 52.357 7.416 ;
     RECT  52.357 6.864 52.403 7.416 ;
     RECT  51.304 11.76 52.405 12.504 ;
     RECT  52.297 0.096 52.409 5.592 ;
     RECT  52.403 6.864 52.445 6.888 ;
     RECT  52.405 11.76 52.451 13.128 ;
     RECT  51.304 14.592 52.451 14.616 ;
     RECT  51.443 8.736 52.481 8.76 ;
     RECT  52.451 13.104 52.769 13.128 ;
     RECT  52.409 0.144 52.945 5.592 ;
     RECT  52.873 6.816 52.945 6.84 ;
     RECT  52.945 0.144 52.985 6.84 ;
     RECT  53.509 10.272 53.597 10.296 ;
     RECT  52.985 0.144 53.629 6.264 ;
     RECT  52.451 11.76 53.891 11.784 ;
     RECT  53.629 0.048 54.035 6.264 ;
     RECT  53.557 15.408 54.131 15.432 ;
     RECT  54.169 15.984 54.253 16.008 ;
     RECT  54.035 0.048 54.281 5.592 ;
     RECT  54.341 18.24 54.425 18.264 ;
     RECT  54.281 0.048 55.145 5.016 ;
     RECT  55.145 0.576 56.408 5.016 ;
     RECT  56.408 0.576 56.512 321.852 ;
     RECT  56.512 0.576 56.581 321.582 ;
     RECT  56.581 0.288 56.704 321.582 ;
     RECT  56.704 0.288 56.869 5.016 ;
     RECT  56.869 0.192 57.061 5.016 ;
     RECT  57.061 0.096 57.085 5.016 ;
     RECT  57.085 0.048 57.305 5.016 ;
     RECT  57.305 0.096 57.341 5.016 ;
     RECT  57.341 0.096 57.557 0.6 ;
     RECT  57.557 0.576 57.701 0.6 ;
     RECT  57.341 1.776 59.389 5.016 ;
     RECT  59.389 1.152 59.717 5.016 ;
     RECT  59.717 1.776 60.865 5.016 ;
     RECT  60.757 0.048 61.121 0.072 ;
     RECT  60.865 1.152 61.517 5.016 ;
     RECT  61.517 1.392 61.808 5.016 ;
     RECT  61.808 1.392 61.912 321.852 ;
     RECT  61.912 1.392 62.104 321.582 ;
     RECT  62.104 1.392 62.701 5.016 ;
     RECT  62.701 0.576 62.881 5.016 ;
     RECT  62.881 0.096 62.993 5.016 ;
     RECT  62.993 0.576 63.029 5.016 ;
     RECT  63.029 0.576 63.137 4.152 ;
     RECT  63.137 1.152 63.857 4.152 ;
     RECT  63.857 1.392 65.653 4.152 ;
     RECT  65.653 0.624 65.941 4.152 ;
     RECT  65.941 0.048 67.208 4.152 ;
     RECT  67.208 0.048 67.312 321.852 ;
     RECT  67.312 0.048 67.504 321.582 ;
     RECT  67.504 0.048 67.601 3.672 ;
     RECT  67.601 1.152 67.817 3.672 ;
     RECT  67.601 0.048 68.033 0.072 ;
     RECT  67.817 1.392 68.177 3.672 ;
     RECT  68.177 1.392 68.537 3.432 ;
     RECT  68.537 1.392 69.401 3.336 ;
     RECT  69.401 1.392 70.121 3.192 ;
     RECT  70.121 2.304 70.193 3.192 ;
     RECT  70.193 2.304 70.301 2.904 ;
     RECT  70.301 2.736 70.589 2.904 ;
     RECT  70.589 2.736 70.661 2.76 ;
     RECT  72.608 2.148 72.712 321.852 ;
     RECT  72.712 2.418 72.904 321.582 ;
     RECT  78.008 2.148 78.112 321.852 ;
     RECT  78.112 2.418 78.304 321.582 ;
     RECT  83.408 2.148 83.512 321.852 ;
     RECT  83.512 2.418 83.704 321.582 ;
    LAYER M5 ;
     RECT  19.92 0.016 57.48 0.659 ;
     RECT  19.92 0.659 21.96 1.427 ;
     RECT  19.92 1.427 21.864 1.475 ;
     RECT  60.96 1.381 60.984 1.621 ;
     RECT  19.92 1.475 21.576 1.763 ;
     RECT  22.992 0.659 57.48 1.763 ;
     RECT  20.304 1.763 21.576 1.811 ;
     RECT  23.088 1.763 57.48 1.811 ;
     RECT  23.184 1.811 57.48 1.859 ;
     RECT  66.624 1.621 66.648 2.053 ;
     RECT  66.576 2.053 66.648 2.101 ;
     RECT  60.96 1.621 61.704 2.137 ;
     RECT  62.688 1.429 62.712 2.137 ;
     RECT  66.576 2.101 66.696 2.137 ;
     RECT  2.4 2.137 2.52 2.151 ;
     RECT  7.8 2.137 7.92 2.151 ;
     RECT  13.2 2.137 13.32 2.151 ;
     RECT  18.6 2.137 18.72 2.151 ;
     RECT  66.576 2.137 67.32 2.151 ;
     RECT  72.6 2.137 72.72 2.151 ;
     RECT  78 2.137 78.12 2.151 ;
     RECT  83.4 2.137 83.52 2.151 ;
     RECT  66.576 2.151 67.512 2.197 ;
     RECT  23.28 1.859 57.48 2.243 ;
     RECT  23.76 2.243 57.48 2.245 ;
     RECT  60.96 2.137 62.712 2.339 ;
     RECT  66.528 2.197 67.512 2.341 ;
     RECT  65.472 2.149 65.496 2.533 ;
     RECT  23.76 2.245 57.576 2.579 ;
     RECT  60.96 2.339 62.328 2.627 ;
     RECT  64.752 2.533 65.496 2.677 ;
     RECT  66.48 2.341 67.512 2.677 ;
     RECT  23.76 2.579 57.48 2.819 ;
     RECT  20.592 1.811 21.576 2.915 ;
     RECT  23.76 2.819 57.096 2.915 ;
     RECT  60.96 2.627 62.112 2.915 ;
     RECT  21.264 2.915 21.576 2.963 ;
     RECT  64.752 2.677 67.512 2.963 ;
     RECT  24 2.915 57.096 3.107 ;
     RECT  64.896 2.963 67.512 3.203 ;
     RECT  25.344 3.107 57.096 3.251 ;
     RECT  25.344 3.251 54.696 3.299 ;
     RECT  66.816 3.203 67.512 3.347 ;
     RECT  43.872 3.299 54.696 3.443 ;
     RECT  25.344 3.299 42.888 3.491 ;
     RECT  64.896 3.203 64.92 3.491 ;
     RECT  25.92 3.491 42.888 3.539 ;
     RECT  61.488 2.915 62.112 3.587 ;
     RECT  21.456 2.963 21.576 3.731 ;
     RECT  56.256 3.251 57 3.779 ;
     RECT  43.872 3.443 54.6 3.971 ;
     RECT  21.456 3.731 21.48 4.115 ;
     RECT  58.704 2.821 58.728 4.115 ;
     RECT  43.872 3.971 54.408 4.211 ;
     RECT  56.256 3.779 56.712 4.213 ;
     RECT  43.872 4.211 52.296 4.451 ;
     RECT  55.824 4.213 56.712 4.451 ;
     RECT  26.016 3.539 42.072 4.501 ;
     RECT  25.392 4.501 42.072 4.547 ;
     RECT  45.12 4.451 52.296 4.547 ;
     RECT  25.392 4.547 41.496 4.787 ;
     RECT  45.264 4.547 52.296 4.979 ;
     RECT  40.2 4.787 41.496 5.123 ;
     RECT  43.872 4.451 44.136 5.125 ;
     RECT  25.392 4.787 38.76 5.171 ;
     RECT  37.872 5.171 38.76 5.315 ;
     RECT  40.2 5.123 41.4 5.459 ;
     RECT  45.312 4.979 52.296 5.459 ;
     RECT  25.392 5.171 36.36 5.747 ;
     RECT  40.2 5.459 40.512 5.989 ;
     RECT  26.016 5.747 36.36 6.323 ;
     RECT  37.872 5.315 38.136 6.323 ;
     RECT  45.312 5.459 51.96 6.517 ;
     RECT  43.776 5.125 44.136 6.755 ;
     RECT  24 3.107 24.312 6.805 ;
     RECT  45.12 6.517 51.96 6.853 ;
     RECT  45.12 6.853 52.392 6.899 ;
     RECT  39.312 5.989 40.512 7.043 ;
     RECT  48.144 6.899 52.392 7.427 ;
     RECT  26.016 6.323 35.832 7.715 ;
     RECT  45.12 6.899 47.16 7.859 ;
     RECT  24 6.805 24.648 7.861 ;
     RECT  45.312 7.859 47.16 8.533 ;
     RECT  48.144 7.427 51.96 8.533 ;
     RECT  26.784 7.715 35.832 8.965 ;
     RECT  26.784 8.965 36.456 9.155 ;
     RECT  43.872 6.755 44.136 9.395 ;
     RECT  24 7.861 25.08 9.491 ;
     RECT  33.312 9.155 36.456 9.731 ;
     RECT  45.312 8.533 51.96 9.731 ;
     RECT  33.312 9.731 35.832 9.779 ;
     RECT  45.312 9.731 45.912 9.827 ;
     RECT  44.112 9.395 44.136 10.307 ;
     RECT  53.52 4.211 54.408 10.307 ;
     RECT  48.144 9.731 51.96 10.355 ;
     RECT  41.76 6.229 41.784 10.789 ;
     RECT  41.76 10.789 41.88 10.835 ;
     RECT  26.832 9.155 32.184 10.883 ;
     RECT  24 9.491 24.312 11.125 ;
     RECT  45.6 9.827 45.912 11.365 ;
     RECT  47.136 9.731 47.16 11.365 ;
     RECT  34.8 9.779 35.832 11.509 ;
     RECT  53.856 10.307 54.408 11.795 ;
     RECT  33.312 9.779 33.72 11.893 ;
     RECT  34.8 11.509 36.552 11.893 ;
     RECT  45.6 11.365 47.16 11.987 ;
     RECT  33.312 11.893 36.552 12.035 ;
     RECT  43.344 10.741 43.368 12.035 ;
     RECT  48.144 10.355 51.312 12.035 ;
     RECT  48.912 12.035 51.312 12.083 ;
     RECT  26.832 10.883 29.712 12.467 ;
     RECT  34.512 12.035 36.552 12.899 ;
     RECT  45.6 11.987 46.008 12.997 ;
     RECT  34.8 12.899 36.552 13.187 ;
     RECT  23.472 11.125 24.312 13.283 ;
     RECT  30.912 10.883 32.184 13.669 ;
     RECT  33.312 12.035 33.336 13.669 ;
     RECT  41.856 10.835 41.88 13.717 ;
     RECT  41.856 13.717 42.12 13.763 ;
     RECT  48.192 13.045 48.216 13.811 ;
     RECT  49.248 12.083 51.312 13.813 ;
     RECT  45.264 12.997 46.008 13.859 ;
     RECT  40.2 7.043 40.512 14.197 ;
     RECT  36.384 13.187 36.552 14.243 ;
     RECT  26.832 12.467 26.856 14.291 ;
     RECT  49.008 13.813 51.312 14.291 ;
     RECT  52.416 12.469 52.44 14.627 ;
     RECT  24 13.283 24.312 14.677 ;
     RECT  45.6 13.859 46.008 14.773 ;
     RECT  47.136 11.987 47.16 14.773 ;
     RECT  30.912 13.669 33.336 14.867 ;
     RECT  30.912 14.867 32.52 14.915 ;
     RECT  24 14.677 24.408 14.963 ;
     RECT  39.792 14.197 40.512 15.011 ;
     RECT  34.8 13.187 35.112 15.013 ;
     RECT  36.384 14.243 36.408 15.013 ;
     RECT  34.8 15.013 36.408 15.443 ;
     RECT  54.096 11.795 54.408 15.443 ;
     RECT  45.6 14.773 47.16 15.445 ;
     RECT  30.912 14.915 32.184 15.539 ;
     RECT  27.888 12.467 29.712 15.829 ;
     RECT  30.912 15.539 31.416 15.829 ;
     RECT  34.8 15.443 35.448 16.019 ;
     RECT  54.192 15.443 54.408 16.019 ;
     RECT  24 14.963 24.312 16.405 ;
     RECT  44.928 15.445 47.16 16.499 ;
     RECT  37.968 11.365 37.992 16.645 ;
     RECT  47.136 16.499 47.16 17.123 ;
     RECT  27.888 15.829 31.416 17.267 ;
     RECT  44.928 16.499 45.912 17.843 ;
     RECT  45.6 17.843 45.912 18.181 ;
     RECT  30.912 17.267 31.416 18.275 ;
     RECT  54.384 16.019 54.408 18.275 ;
     RECT  42.096 13.763 42.12 18.325 ;
     RECT  43.872 18.037 43.896 18.325 ;
     RECT  41.616 18.325 42.12 18.371 ;
     RECT  27.888 17.267 29.712 18.421 ;
     RECT  41.616 18.371 41.64 18.467 ;
     RECT  49.248 14.291 49.272 18.469 ;
     RECT  50.352 14.291 51.312 18.469 ;
     RECT  37.968 16.645 38.232 18.563 ;
     RECT  27.312 18.421 29.712 18.565 ;
     RECT  34.8 16.019 35.112 18.757 ;
     RECT  43.584 18.325 43.896 18.805 ;
     RECT  37.968 18.563 37.992 18.947 ;
     RECT  27.312 18.565 29.928 19.427 ;
     RECT  34.176 18.757 35.112 19.427 ;
     RECT  45.6 18.181 46.008 19.427 ;
     RECT  27.888 19.427 29.928 19.571 ;
     RECT  24 16.405 25.128 20.053 ;
     RECT  24 20.053 25.656 20.099 ;
     RECT  43.584 18.805 43.992 20.339 ;
     RECT  49.248 18.469 51.312 21.155 ;
     RECT  43.584 20.339 43.608 22.117 ;
     RECT  48 20.821 48.024 22.211 ;
     RECT  25.632 20.099 25.656 22.259 ;
     RECT  40.2 15.011 40.512 22.549 ;
     RECT  27.888 19.571 29.712 22.691 ;
     RECT  28.464 22.691 29.712 22.835 ;
     RECT  31.344 22.069 31.368 23.075 ;
     RECT  28.704 22.835 29.712 23.411 ;
     RECT  43.584 22.117 44.088 23.411 ;
     RECT  49.248 21.155 49.416 23.411 ;
     RECT  44.064 23.411 44.088 23.603 ;
     RECT  51 21.155 51.312 23.941 ;
     RECT  34.8 19.427 35.112 24.181 ;
     RECT  40.2 22.549 40.776 24.515 ;
     RECT  49.248 23.411 49.272 24.563 ;
     RECT  27.936 24.133 27.96 25.187 ;
     RECT  34.8 24.181 35.256 25.187 ;
     RECT  29.4 23.411 29.712 25.525 ;
     RECT  32.448 21.493 32.472 25.715 ;
     RECT  50.736 23.941 51.312 25.715 ;
     RECT  47.616 23.557 47.64 26.003 ;
     RECT  29.4 25.525 29.832 27.731 ;
     RECT  2.4 2.151 2.712 321.849 ;
     RECT  7.8 2.151 8.112 321.849 ;
     RECT  13.2 2.151 13.512 321.849 ;
     RECT  18.6 2.151 18.912 321.849 ;
     RECT  24 20.099 24.312 321.849 ;
     RECT  29.4 27.731 29.712 321.849 ;
     RECT  34.8 25.187 35.112 321.849 ;
     RECT  40.2 24.515 40.512 321.849 ;
     RECT  45.6 19.427 45.912 321.849 ;
     RECT  51 25.715 51.312 321.849 ;
     RECT  56.4 4.451 56.712 321.849 ;
     RECT  61.8 3.587 62.112 321.849 ;
     RECT  67.2 3.347 67.512 321.849 ;
     RECT  72.6 2.151 72.912 321.849 ;
     RECT  78 2.151 78.312 321.849 ;
     RECT  83.4 2.151 83.712 321.849 ;
     RECT  2.4 321.849 2.52 321.863 ;
     RECT  7.8 321.849 7.92 321.863 ;
     RECT  13.2 321.849 13.32 321.863 ;
     RECT  18.6 321.849 18.72 321.863 ;
     RECT  24 321.849 24.12 321.863 ;
     RECT  29.4 321.849 29.52 321.863 ;
     RECT  34.8 321.849 34.92 321.863 ;
     RECT  40.2 321.849 40.32 321.863 ;
     RECT  45.6 321.849 45.72 321.863 ;
     RECT  51 321.849 51.12 321.863 ;
     RECT  56.4 321.849 56.52 321.863 ;
     RECT  61.8 321.849 61.92 321.863 ;
     RECT  67.2 321.849 67.32 321.863 ;
     RECT  72.6 321.849 72.72 321.863 ;
     RECT  78 321.849 78.12 321.863 ;
     RECT  83.4 321.849 83.52 321.863 ;
  END
END dsfd_capt_ctl
END LIBRARY
